VERSION 5.7 ;
BUSBITCHARS "[]" ;
DIVIDERCHAR "/" ;


UNITS
  DATABASE MICRONS 1000 ;
END UNITS


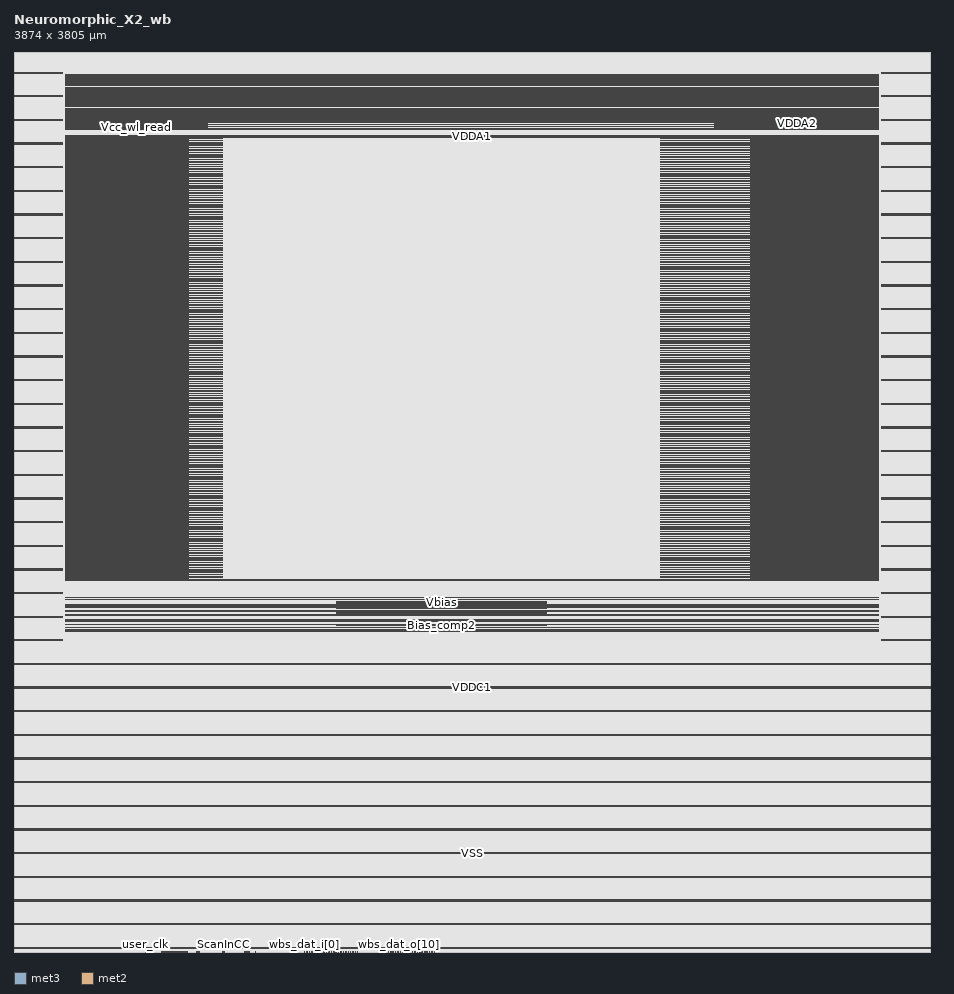
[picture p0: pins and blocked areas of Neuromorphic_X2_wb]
MACRO Neuromorphic_X2_wb
  CLASS BLOCK ;
  ORIGIN 0 0 ;
  FOREIGN Neuromorphic_X2_wb 0 0 ;
  SIZE 3874 BY 3805 ;
  PIN VSS
    DIRECTION INOUT ;
    USE GROUND ;
    PORT
      LAYER met3 ;
        RECT 216.895 3444.195 3656.935 3445.195 ;
    END
    PORT
      LAYER met3 ;
        RECT 216.8 3450.445 3656.84 3451.445 ;
    END
    PORT
      LAYER met3 ;
        RECT 216.99 1575.065 3656.935 1576.065 ;
    END
    PORT
      LAYER met3 ;
        RECT 216.99 1569.495 3656.935 1570.495 ;
    END
    PORT
      LAYER met3 ;
        RECT 0 415 3874 416.8 ;
    END
    PORT
      LAYER met3 ;
        RECT 0 815 3874 816.8 ;
    END
    PORT
      LAYER met3 ;
        RECT 0 915 3874 916.8 ;
    END
    PORT
      LAYER met3 ;
        RECT 0 1015 3874 1016.8 ;
    END
    PORT
      LAYER met3 ;
        RECT 0 1115 3874 1116.8 ;
    END
    PORT
      LAYER met3 ;
        RECT 0 515 3874 516.8 ;
    END
    PORT
      LAYER met3 ;
        RECT 0 615 3874 616.8 ;
    END
    PORT
      LAYER met3 ;
        RECT 0 715 3874 716.8 ;
    END
    PORT
      LAYER met3 ;
        RECT 0 15 3874 16.8 ;
    END
    PORT
      LAYER met3 ;
        RECT 0 115 3874 116.8 ;
    END
    PORT
      LAYER met3 ;
        RECT 0 215 3874 216.8 ;
    END
    PORT
      LAYER met3 ;
        RECT 0 315 3874 316.8 ;
    END
    PORT
      LAYER met3 ;
        RECT 0 3715 205 3716.8 ;
    END
    PORT
      LAYER met3 ;
        RECT 3669 3715 3874 3716.8 ;
    END
    PORT
      LAYER met3 ;
        RECT 0 3615 205 3616.8 ;
    END
    PORT
      LAYER met3 ;
        RECT 3669 3615 3874 3616.8 ;
    END
    PORT
      LAYER met3 ;
        RECT 0 3515 205 3516.8 ;
    END
    PORT
      LAYER met3 ;
        RECT 3669 3515 3874 3516.8 ;
    END
    PORT
      LAYER met3 ;
        RECT 0 3415 205 3416.8 ;
    END
    PORT
      LAYER met3 ;
        RECT 3669 3415 3874 3416.8 ;
    END
    PORT
      LAYER met3 ;
        RECT 0 3315 205 3316.8 ;
    END
    PORT
      LAYER met3 ;
        RECT 3669 3315 3874 3316.8 ;
    END
    PORT
      LAYER met3 ;
        RECT 0 3215 205 3216.8 ;
    END
    PORT
      LAYER met3 ;
        RECT 3669 3215 3874 3216.8 ;
    END
    PORT
      LAYER met3 ;
        RECT 0 3115 205 3116.8 ;
    END
    PORT
      LAYER met3 ;
        RECT 3669 3115 3874 3116.8 ;
    END
    PORT
      LAYER met3 ;
        RECT 0 3015 205 3016.8 ;
    END
    PORT
      LAYER met3 ;
        RECT 3669 3015 3874 3016.8 ;
    END
    PORT
      LAYER met3 ;
        RECT 0 2915 205 2916.8 ;
    END
    PORT
      LAYER met3 ;
        RECT 3669 2915 3874 2916.8 ;
    END
    PORT
      LAYER met3 ;
        RECT 0 2815 205 2816.8 ;
    END
    PORT
      LAYER met3 ;
        RECT 3669 2815 3874 2816.8 ;
    END
    PORT
      LAYER met3 ;
        RECT 0 2715 205 2716.8 ;
    END
    PORT
      LAYER met3 ;
        RECT 3669 2715 3874 2716.8 ;
    END
    PORT
      LAYER met3 ;
        RECT 0 2615 205 2616.8 ;
    END
    PORT
      LAYER met3 ;
        RECT 3669 2615 3874 2616.8 ;
    END
    PORT
      LAYER met3 ;
        RECT 0 2515 205 2516.8 ;
    END
    PORT
      LAYER met3 ;
        RECT 3669 2515 3874 2516.8 ;
    END
    PORT
      LAYER met3 ;
        RECT 0 2415 205 2416.8 ;
    END
    PORT
      LAYER met3 ;
        RECT 3669 2415 3874 2416.8 ;
    END
    PORT
      LAYER met3 ;
        RECT 0 2315 205 2316.8 ;
    END
    PORT
      LAYER met3 ;
        RECT 3669 2315 3874 2316.8 ;
    END
    PORT
      LAYER met3 ;
        RECT 0 2215 205 2216.8 ;
    END
    PORT
      LAYER met3 ;
        RECT 3669 2215 3874 2216.8 ;
    END
    PORT
      LAYER met3 ;
        RECT 0 2115 205 2116.8 ;
    END
    PORT
      LAYER met3 ;
        RECT 3669 2115 3874 2116.8 ;
    END
    PORT
      LAYER met3 ;
        RECT 0 2015 205 2016.8 ;
    END
    PORT
      LAYER met3 ;
        RECT 3669 2015 3874 2016.8 ;
    END
    PORT
      LAYER met3 ;
        RECT 0 1715 205 1716.8 ;
    END
    PORT
      LAYER met3 ;
        RECT 0 1815 205 1816.8 ;
    END
    PORT
      LAYER met3 ;
        RECT 0 1915 205 1916.8 ;
    END
    PORT
      LAYER met3 ;
        RECT 0 1315 205 1316.8 ;
    END
    PORT
      LAYER met3 ;
        RECT 0 1415 205 1416.8 ;
    END
    PORT
      LAYER met3 ;
        RECT 0 1515 205 1516.8 ;
    END
    PORT
      LAYER met3 ;
        RECT 0 1615 205 1616.8 ;
    END
    PORT
      LAYER met3 ;
        RECT 3669 1415 3874 1416.8 ;
    END
    PORT
      LAYER met3 ;
        RECT 3669 1515 3874 1516.8 ;
    END
    PORT
      LAYER met3 ;
        RECT 3669 1615 3874 1616.8 ;
    END
    PORT
      LAYER met3 ;
        RECT 3669 1715 3874 1716.8 ;
    END
    PORT
      LAYER met3 ;
        RECT 3669 1815 3874 1816.8 ;
    END
    PORT
      LAYER met3 ;
        RECT 3669 1915 3874 1916.8 ;
    END
    PORT
      LAYER met3 ;
        RECT 3669 1315 3874 1316.8 ;
    END
    PORT
      LAYER met3 ;
        RECT 0 1215 3874 1216.8 ;
    END
    PORT
      LAYER met3 ;
        RECT 216.99 1465.725 3656.935 1467.225 ;
    END
    PORT
      LAYER met3 ;
        RECT 216.99 1457.28 3656.935 1458.78 ;
    END
    PORT
      LAYER met3 ;
        RECT 216.99 1421.265 3656.935 1422.765 ;
    END
    PORT
      LAYER met3 ;
        RECT 216.99 1357.08 3656.935 1358.58 ;
    END
    PORT
      LAYER met3 ;
        RECT 216.99 1371.215 3656.935 1372.715 ;
    END
    PORT
      LAYER met3 ;
        RECT 216.99 1490.735 3656.935 1492.235 ;
    END
    PORT
      LAYER met3 ;
        RECT 216.99 1497.995 3656.935 1499.495 ;
    END
    PORT
      LAYER met3 ;
        RECT 216.99 1441.55 3656.935 1443.05 ;
    END
    PORT
      LAYER met3 ;
        RECT 216.895 3566.285 3656.84 3567.285 ;
    END
    PORT
      LAYER met3 ;
        RECT 216.895 3586.705 3656.84 3587.705 ;
    END
    PORT
      LAYER met3 ;
        RECT 216.895 3588.705 3656.84 3589.705 ;
    END
    PORT
      LAYER met3 ;
        RECT 216.895 3592.705 3656.84 3593.705 ;
    END
    PORT
      LAYER met3 ;
        RECT 216.895 3594.705 3656.84 3595.705 ;
    END
    PORT
      LAYER met3 ;
        RECT 216.895 3596.705 3656.84 3597.705 ;
    END
    PORT
      LAYER met3 ;
        RECT 216.895 3615.96 3656.84 3616.96 ;
    END
    PORT
      LAYER met3 ;
        RECT 216.895 3617.96 3656.84 3618.96 ;
    END
    PORT
      LAYER met3 ;
        RECT 216.895 3621.96 3656.84 3622.96 ;
    END
    PORT
      LAYER met3 ;
        RECT 216.895 3623.96 3656.84 3624.96 ;
    END
    PORT
      LAYER met3 ;
        RECT 216.895 3625.96 3656.84 3626.96 ;
    END
    PORT
      LAYER met3 ;
        RECT 216.895 3645.495 3656.84 3646.495 ;
    END
    PORT
      LAYER met3 ;
        RECT 216.895 3647.495 3656.84 3648.495 ;
    END
    PORT
      LAYER met3 ;
        RECT 216.895 3649.495 3656.84 3650.495 ;
    END
    PORT
      LAYER met3 ;
        RECT 216.895 3651.495 3656.84 3652.495 ;
    END
    PORT
      LAYER met3 ;
        RECT 216.895 3653.495 3656.84 3654.495 ;
    END
    PORT
      LAYER met3 ;
        RECT 216.895 3663.04 3656.84 3664.04 ;
    END
    PORT
      LAYER met3 ;
        RECT 216.895 3682.355 3656.84 3683.355 ;
    END
    PORT
      LAYER met3 ;
        RECT 216.895 3684.355 3656.84 3685.355 ;
    END
    PORT
      LAYER met3 ;
        RECT 216.895 3686.355 3656.84 3687.355 ;
    END
    PORT
      LAYER met3 ;
        RECT 216.895 3688.355 3656.84 3689.355 ;
    END
    PORT
      LAYER met3 ;
        RECT 216.895 3692.72 3656.84 3693.72 ;
    END
    PORT
      LAYER met3 ;
        RECT 216.895 3696.72 3656.84 3697.72 ;
    END
    PORT
      LAYER met3 ;
        RECT 216.895 3707.535 3656.84 3708.535 ;
    END
    PORT
      LAYER met3 ;
        RECT 216.895 3532.02 3656.84 3533.02 ;
    END
    PORT
      LAYER met3 ;
        RECT 216.895 3534.02 3656.84 3535.02 ;
    END
    PORT
      LAYER met3 ;
        RECT 216.895 3526.02 3656.84 3527.02 ;
    END
    PORT
      LAYER met3 ;
        RECT 216.895 3528.02 3656.84 3529.02 ;
    END
    PORT
      LAYER met3 ;
        RECT 216.895 3556.285 3656.84 3557.285 ;
    END
    PORT
      LAYER met3 ;
        RECT 216.895 3558.285 3656.84 3559.285 ;
    END
    PORT
      LAYER met3 ;
        RECT 216.895 3560.285 3656.84 3561.285 ;
    END
    PORT
      LAYER met3 ;
        RECT 216.895 3564.285 3656.84 3565.285 ;
    END
    PORT
      LAYER met3 ;
        RECT 216.895 3478.52 3656.84 3479.52 ;
    END
    PORT
      LAYER met3 ;
        RECT 216.895 3580.705 3656.84 3581.705 ;
    END
    PORT
      LAYER met3 ;
        RECT 216.895 3582.705 3656.84 3583.705 ;
    END
    PORT
      LAYER met3 ;
        RECT 216.895 3584.705 3656.84 3585.705 ;
    END
    PORT
      LAYER met3 ;
        RECT 216.895 3572.705 3656.84 3573.705 ;
    END
    PORT
      LAYER met3 ;
        RECT 216.895 3544.285 3656.84 3545.285 ;
    END
    PORT
      LAYER met3 ;
        RECT 216.895 3546.285 3656.84 3547.285 ;
    END
    PORT
      LAYER met3 ;
        RECT 216.895 3548.285 3656.84 3549.285 ;
    END
    PORT
      LAYER met3 ;
        RECT 216.895 3552.285 3656.84 3553.285 ;
    END
    PORT
      LAYER met3 ;
        RECT 216.895 3554.285 3656.84 3555.285 ;
    END
    PORT
      LAYER met3 ;
        RECT 216.895 3542.285 3656.84 3543.285 ;
    END
    PORT
      LAYER met3 ;
        RECT 216.895 3514.02 3656.84 3515.02 ;
    END
    PORT
      LAYER met3 ;
        RECT 216.895 3516.02 3656.84 3517.02 ;
    END
    PORT
      LAYER met3 ;
        RECT 216.895 3520.02 3656.84 3521.02 ;
    END
    PORT
      LAYER met3 ;
        RECT 216.895 3522.02 3656.84 3523.02 ;
    END
    PORT
      LAYER met3 ;
        RECT 216.895 3512.02 3656.84 3513.02 ;
    END
    PORT
      LAYER met3 ;
        RECT 216.895 3633.495 3656.84 3634.495 ;
    END
    PORT
      LAYER met3 ;
        RECT 216.895 3635.495 3656.84 3636.495 ;
    END
    PORT
      LAYER met3 ;
        RECT 216.895 3637.495 3656.84 3638.495 ;
    END
    PORT
      LAYER met3 ;
        RECT 216.895 3639.495 3656.84 3640.495 ;
    END
    PORT
      LAYER met3 ;
        RECT 216.895 3641.495 3656.84 3642.495 ;
    END
    PORT
      LAYER met3 ;
        RECT 216.895 3631.495 3656.84 3632.495 ;
    END
    PORT
      LAYER met3 ;
        RECT 216.895 3603.96 3656.84 3604.96 ;
    END
    PORT
      LAYER met3 ;
        RECT 216.895 3605.96 3656.84 3606.96 ;
    END
    PORT
      LAYER met3 ;
        RECT 216.895 3609.96 3656.84 3610.96 ;
    END
    PORT
      LAYER met3 ;
        RECT 216.895 3611.96 3656.84 3612.96 ;
    END
    PORT
      LAYER met3 ;
        RECT 216.895 3613.96 3656.84 3614.96 ;
    END
    PORT
      LAYER met3 ;
        RECT 216.895 3601.96 3656.84 3602.96 ;
    END
    PORT
      LAYER met3 ;
        RECT 216.895 3574.705 3656.84 3575.705 ;
    END
    PORT
      LAYER met3 ;
        RECT 216.895 3576.705 3656.84 3577.705 ;
    END
    PORT
      LAYER met3 ;
        RECT 2731.99 1806.965 3656.935 1807.305 ;
        RECT 2731.99 1923.445 3656.935 1923.785 ;
        RECT 2731.99 2039.925 3656.935 2040.265 ;
        RECT 2731.99 2156.405 3656.935 2156.745 ;
        RECT 2731.99 2272.885 3656.935 2273.225 ;
        RECT 2731.99 2389.365 3656.935 2389.705 ;
        RECT 2731.99 2505.845 3656.935 2506.185 ;
        RECT 2731.99 2622.325 3656.935 2622.665 ;
        RECT 2731.99 2738.805 3656.935 2739.145 ;
        RECT 2731.99 2855.285 3656.935 2855.625 ;
        RECT 2731.99 2971.765 3656.935 2972.105 ;
        RECT 2731.99 3088.245 3656.935 3088.585 ;
        RECT 2731.99 3204.725 3656.935 3205.065 ;
        RECT 2731.99 3321.205 3656.935 3321.545 ;
        RECT 2731.99 3437.685 3656.935 3438.025 ;
    END
    PORT
      LAYER met3 ;
        RECT 2731.99 1799.685 3656.935 1800.025 ;
        RECT 2731.99 1916.165 3656.935 1916.505 ;
        RECT 2731.99 2032.645 3656.935 2032.985 ;
        RECT 2731.99 2149.125 3656.935 2149.465 ;
        RECT 2731.99 2265.605 3656.935 2265.945 ;
        RECT 2731.99 2382.085 3656.935 2382.425 ;
        RECT 2731.99 2498.565 3656.935 2498.905 ;
        RECT 2731.99 2615.045 3656.935 2615.385 ;
        RECT 2731.99 2731.525 3656.935 2731.865 ;
        RECT 2731.99 2848.005 3656.935 2848.345 ;
        RECT 2731.99 2964.485 3656.935 2964.825 ;
        RECT 2731.99 3080.965 3656.935 3081.305 ;
        RECT 2731.99 3197.445 3656.935 3197.785 ;
        RECT 2731.99 3313.925 3656.935 3314.265 ;
        RECT 2731.99 3430.405 3656.935 3430.745 ;
    END
    PORT
      LAYER met3 ;
        RECT 2731.99 1792.405 3656.935 1792.745 ;
        RECT 2731.99 1908.885 3656.935 1909.225 ;
        RECT 2731.99 2025.365 3656.935 2025.705 ;
        RECT 2731.99 2141.845 3656.935 2142.185 ;
        RECT 2731.99 2258.325 3656.935 2258.665 ;
        RECT 2731.99 2374.805 3656.935 2375.145 ;
        RECT 2731.99 2491.285 3656.935 2491.625 ;
        RECT 2731.99 2607.765 3656.935 2608.105 ;
        RECT 2731.99 2724.245 3656.935 2724.585 ;
        RECT 2731.99 2840.725 3656.935 2841.065 ;
        RECT 2731.99 2957.205 3656.935 2957.545 ;
        RECT 2731.99 3073.685 3656.935 3074.025 ;
        RECT 2731.99 3190.165 3656.935 3190.505 ;
        RECT 2731.99 3306.645 3656.935 3306.985 ;
        RECT 2731.99 3423.125 3656.935 3423.465 ;
    END
    PORT
      LAYER met3 ;
        RECT 2731.99 1785.125 3656.935 1785.465 ;
        RECT 2731.99 1901.605 3656.935 1901.945 ;
        RECT 2731.99 2018.085 3656.935 2018.425 ;
        RECT 2731.99 2134.565 3656.935 2134.905 ;
        RECT 2731.99 2251.045 3656.935 2251.385 ;
        RECT 2731.99 2367.525 3656.935 2367.865 ;
        RECT 2731.99 2484.005 3656.935 2484.345 ;
        RECT 2731.99 2600.485 3656.935 2600.825 ;
        RECT 2731.99 2716.965 3656.935 2717.305 ;
        RECT 2731.99 2833.445 3656.935 2833.785 ;
        RECT 2731.99 2949.925 3656.935 2950.265 ;
        RECT 2731.99 3066.405 3656.935 3066.745 ;
        RECT 2731.99 3182.885 3656.935 3183.225 ;
        RECT 2731.99 3299.365 3656.935 3299.705 ;
        RECT 2731.99 3415.845 3656.935 3416.185 ;
    END
    PORT
      LAYER met3 ;
        RECT 2731.99 1777.845 3656.935 1778.185 ;
        RECT 2731.99 1894.325 3656.935 1894.665 ;
        RECT 2731.99 2010.805 3656.935 2011.145 ;
        RECT 2731.99 2127.285 3656.935 2127.625 ;
        RECT 2731.99 2243.765 3656.935 2244.105 ;
        RECT 2731.99 2360.245 3656.935 2360.585 ;
        RECT 2731.99 2476.725 3656.935 2477.065 ;
        RECT 2731.99 2593.205 3656.935 2593.545 ;
        RECT 2731.99 2709.685 3656.935 2710.025 ;
        RECT 2731.99 2826.165 3656.935 2826.505 ;
        RECT 2731.99 2942.645 3656.935 2942.985 ;
        RECT 2731.99 3059.125 3656.935 3059.465 ;
        RECT 2731.99 3175.605 3656.935 3175.945 ;
        RECT 2731.99 3292.085 3656.935 3292.425 ;
        RECT 2731.99 3408.565 3656.935 3408.905 ;
    END
    PORT
      LAYER met3 ;
        RECT 2731.99 1770.565 3656.935 1770.905 ;
        RECT 2731.99 1887.045 3656.935 1887.385 ;
        RECT 2731.99 2003.525 3656.935 2003.865 ;
        RECT 2731.99 2120.005 3656.935 2120.345 ;
        RECT 2731.99 2236.485 3656.935 2236.825 ;
        RECT 2731.99 2352.965 3656.935 2353.305 ;
        RECT 2731.99 2469.445 3656.935 2469.785 ;
        RECT 2731.99 2585.925 3656.935 2586.265 ;
        RECT 2731.99 2702.405 3656.935 2702.745 ;
        RECT 2731.99 2818.885 3656.935 2819.225 ;
        RECT 2731.99 2935.365 3656.935 2935.705 ;
        RECT 2731.99 3051.845 3656.935 3052.185 ;
        RECT 2731.99 3168.325 3656.935 3168.665 ;
        RECT 2731.99 3284.805 3656.935 3285.145 ;
        RECT 2731.99 3401.285 3656.935 3401.625 ;
    END
    PORT
      LAYER met3 ;
        RECT 2731.99 1763.285 3656.935 1763.625 ;
        RECT 2731.99 1879.765 3656.935 1880.105 ;
        RECT 2731.99 1996.245 3656.935 1996.585 ;
        RECT 2731.99 2112.725 3656.935 2113.065 ;
        RECT 2731.99 2229.205 3656.935 2229.545 ;
        RECT 2731.99 2345.685 3656.935 2346.025 ;
        RECT 2731.99 2462.165 3656.935 2462.505 ;
        RECT 2731.99 2578.645 3656.935 2578.985 ;
        RECT 2731.99 2695.125 3656.935 2695.465 ;
        RECT 2731.99 2811.605 3656.935 2811.945 ;
        RECT 2731.99 2928.085 3656.935 2928.425 ;
        RECT 2731.99 3044.565 3656.935 3044.905 ;
        RECT 2731.99 3161.045 3656.935 3161.385 ;
        RECT 2731.99 3277.525 3656.935 3277.865 ;
        RECT 2731.99 3394.005 3656.935 3394.345 ;
    END
    PORT
      LAYER met3 ;
        RECT 2731.99 1756.005 3656.935 1756.345 ;
        RECT 2731.99 1872.485 3656.935 1872.825 ;
        RECT 2731.99 1988.965 3656.935 1989.305 ;
        RECT 2731.99 2105.445 3656.935 2105.785 ;
        RECT 2731.99 2221.925 3656.935 2222.265 ;
        RECT 2731.99 2338.405 3656.935 2338.745 ;
        RECT 2731.99 2454.885 3656.935 2455.225 ;
        RECT 2731.99 2571.365 3656.935 2571.705 ;
        RECT 2731.99 2687.845 3656.935 2688.185 ;
        RECT 2731.99 2804.325 3656.935 2804.665 ;
        RECT 2731.99 2920.805 3656.935 2921.145 ;
        RECT 2731.99 3037.285 3656.935 3037.625 ;
        RECT 2731.99 3153.765 3656.935 3154.105 ;
        RECT 2731.99 3270.245 3656.935 3270.585 ;
        RECT 2731.99 3386.725 3656.935 3387.065 ;
    END
    PORT
      LAYER met3 ;
        RECT 2731.99 1748.725 3656.935 1749.065 ;
        RECT 2731.99 1865.205 3656.935 1865.545 ;
        RECT 2731.99 1981.685 3656.935 1982.025 ;
        RECT 2731.99 2098.165 3656.935 2098.505 ;
        RECT 2731.99 2214.645 3656.935 2214.985 ;
        RECT 2731.99 2331.125 3656.935 2331.465 ;
        RECT 2731.99 2447.605 3656.935 2447.945 ;
        RECT 2731.99 2564.085 3656.935 2564.425 ;
        RECT 2731.99 2680.565 3656.935 2680.905 ;
        RECT 2731.99 2797.045 3656.935 2797.385 ;
        RECT 2731.99 2913.525 3656.935 2913.865 ;
        RECT 2731.99 3030.005 3656.935 3030.345 ;
        RECT 2731.99 3146.485 3656.935 3146.825 ;
        RECT 2731.99 3262.965 3656.935 3263.305 ;
        RECT 2731.99 3379.445 3656.935 3379.785 ;
    END
    PORT
      LAYER met3 ;
        RECT 2731.99 1741.445 3656.935 1741.785 ;
        RECT 2731.99 1857.925 3656.935 1858.265 ;
        RECT 2731.99 1974.405 3656.935 1974.745 ;
        RECT 2731.99 2090.885 3656.935 2091.225 ;
        RECT 2731.99 2207.365 3656.935 2207.705 ;
        RECT 2731.99 2323.845 3656.935 2324.185 ;
        RECT 2731.99 2440.325 3656.935 2440.665 ;
        RECT 2731.99 2556.805 3656.935 2557.145 ;
        RECT 2731.99 2673.285 3656.935 2673.625 ;
        RECT 2731.99 2789.765 3656.935 2790.105 ;
        RECT 2731.99 2906.245 3656.935 2906.585 ;
        RECT 2731.99 3022.725 3656.935 3023.065 ;
        RECT 2731.99 3139.205 3656.935 3139.545 ;
        RECT 2731.99 3255.685 3656.935 3256.025 ;
        RECT 2731.99 3372.165 3656.935 3372.505 ;
    END
    PORT
      LAYER met3 ;
        RECT 2731.99 1734.165 3656.935 1734.505 ;
        RECT 2731.99 1850.645 3656.935 1850.985 ;
        RECT 2731.99 1967.125 3656.935 1967.465 ;
        RECT 2731.99 2083.605 3656.935 2083.945 ;
        RECT 2731.99 2200.085 3656.935 2200.425 ;
        RECT 2731.99 2316.565 3656.935 2316.905 ;
        RECT 2731.99 2433.045 3656.935 2433.385 ;
        RECT 2731.99 2549.525 3656.935 2549.865 ;
        RECT 2731.99 2666.005 3656.935 2666.345 ;
        RECT 2731.99 2782.485 3656.935 2782.825 ;
        RECT 2731.99 2898.965 3656.935 2899.305 ;
        RECT 2731.99 3015.445 3656.935 3015.785 ;
        RECT 2731.99 3131.925 3656.935 3132.265 ;
        RECT 2731.99 3248.405 3656.935 3248.745 ;
        RECT 2731.99 3364.885 3656.935 3365.225 ;
    END
    PORT
      LAYER met3 ;
        RECT 2731.99 1726.885 3656.935 1727.225 ;
        RECT 2731.99 1843.365 3656.935 1843.705 ;
        RECT 2731.99 1959.845 3656.935 1960.185 ;
        RECT 2731.99 2076.325 3656.935 2076.665 ;
        RECT 2731.99 2192.805 3656.935 2193.145 ;
        RECT 2731.99 2309.285 3656.935 2309.625 ;
        RECT 2731.99 2425.765 3656.935 2426.105 ;
        RECT 2731.99 2542.245 3656.935 2542.585 ;
        RECT 2731.99 2658.725 3656.935 2659.065 ;
        RECT 2731.99 2775.205 3656.935 2775.545 ;
        RECT 2731.99 2891.685 3656.935 2892.025 ;
        RECT 2731.99 3008.165 3656.935 3008.505 ;
        RECT 2731.99 3124.645 3656.935 3124.985 ;
        RECT 2731.99 3241.125 3656.935 3241.465 ;
        RECT 2731.99 3357.605 3656.935 3357.945 ;
    END
    PORT
      LAYER met3 ;
        RECT 2731.99 1719.605 3656.935 1719.945 ;
        RECT 2731.99 1836.085 3656.935 1836.425 ;
        RECT 2731.99 1952.565 3656.935 1952.905 ;
        RECT 2731.99 2069.045 3656.935 2069.385 ;
        RECT 2731.99 2185.525 3656.935 2185.865 ;
        RECT 2731.99 2302.005 3656.935 2302.345 ;
        RECT 2731.99 2418.485 3656.935 2418.825 ;
        RECT 2731.99 2534.965 3656.935 2535.305 ;
        RECT 2731.99 2651.445 3656.935 2651.785 ;
        RECT 2731.99 2767.925 3656.935 2768.265 ;
        RECT 2731.99 2884.405 3656.935 2884.745 ;
        RECT 2731.99 3000.885 3656.935 3001.225 ;
        RECT 2731.99 3117.365 3656.935 3117.705 ;
        RECT 2731.99 3233.845 3656.935 3234.185 ;
        RECT 2731.99 3350.325 3656.935 3350.665 ;
    END
    PORT
      LAYER met3 ;
        RECT 2731.99 1712.325 3656.935 1712.665 ;
        RECT 2731.99 1828.805 3656.935 1829.145 ;
        RECT 2731.99 1945.285 3656.935 1945.625 ;
        RECT 2731.99 2061.765 3656.935 2062.105 ;
        RECT 2731.99 2178.245 3656.935 2178.585 ;
        RECT 2731.99 2294.725 3656.935 2295.065 ;
        RECT 2731.99 2411.205 3656.935 2411.545 ;
        RECT 2731.99 2527.685 3656.935 2528.025 ;
        RECT 2731.99 2644.165 3656.935 2644.505 ;
        RECT 2731.99 2760.645 3656.935 2760.985 ;
        RECT 2731.99 2877.125 3656.935 2877.465 ;
        RECT 2731.99 2993.605 3656.935 2993.945 ;
        RECT 2731.99 3110.085 3656.935 3110.425 ;
        RECT 2731.99 3226.565 3656.935 3226.905 ;
        RECT 2731.99 3343.045 3656.935 3343.385 ;
    END
    PORT
      LAYER met3 ;
        RECT 2731.99 1705.045 3656.935 1705.385 ;
        RECT 2731.99 1821.525 3656.935 1821.865 ;
        RECT 2731.99 1938.005 3656.935 1938.345 ;
        RECT 2731.99 2054.485 3656.935 2054.825 ;
        RECT 2731.99 2170.965 3656.935 2171.305 ;
        RECT 2731.99 2287.445 3656.935 2287.785 ;
        RECT 2731.99 2403.925 3656.935 2404.265 ;
        RECT 2731.99 2520.405 3656.935 2520.745 ;
        RECT 2731.99 2636.885 3656.935 2637.225 ;
        RECT 2731.99 2753.365 3656.935 2753.705 ;
        RECT 2731.99 2869.845 3656.935 2870.185 ;
        RECT 2731.99 2986.325 3656.935 2986.665 ;
        RECT 2731.99 3102.805 3656.935 3103.145 ;
        RECT 2731.99 3219.285 3656.935 3219.625 ;
        RECT 2731.99 3335.765 3656.935 3336.105 ;
    END
    PORT
      LAYER met3 ;
        RECT 2731.99 1697.765 3656.935 1698.105 ;
        RECT 2731.99 1814.245 3656.935 1814.585 ;
        RECT 2731.99 1930.725 3656.935 1931.065 ;
        RECT 2731.99 2047.205 3656.935 2047.545 ;
        RECT 2731.99 2163.685 3656.935 2164.025 ;
        RECT 2731.99 2280.165 3656.935 2280.505 ;
        RECT 2731.99 2396.645 3656.935 2396.985 ;
        RECT 2731.99 2513.125 3656.935 2513.465 ;
        RECT 2731.99 2629.605 3656.935 2629.945 ;
        RECT 2731.99 2746.085 3656.935 2746.425 ;
        RECT 2731.99 2862.565 3656.935 2862.905 ;
        RECT 2731.99 2979.045 3656.935 2979.385 ;
        RECT 2731.99 3095.525 3656.935 3095.865 ;
        RECT 2731.99 3212.005 3656.935 3212.345 ;
        RECT 2731.99 3328.485 3656.935 3328.825 ;
    END
    PORT
      LAYER met3 ;
        RECT 216.99 1807.11 881.99 1807.45 ;
        RECT 216.99 1923.59 881.99 1923.93 ;
        RECT 216.99 2040.07 881.99 2040.41 ;
        RECT 216.99 2156.55 881.99 2156.89 ;
        RECT 216.99 2273.03 881.99 2273.37 ;
        RECT 216.99 2389.51 881.99 2389.85 ;
        RECT 216.99 2505.99 881.99 2506.33 ;
        RECT 216.99 2622.47 881.99 2622.81 ;
        RECT 216.99 2738.95 881.99 2739.29 ;
        RECT 216.99 2855.43 881.99 2855.77 ;
        RECT 216.99 2971.91 881.99 2972.25 ;
        RECT 216.99 3088.39 881.99 3088.73 ;
        RECT 216.99 3204.87 881.99 3205.21 ;
        RECT 216.99 3321.35 881.99 3321.69 ;
        RECT 216.99 3437.83 881.99 3438.17 ;
    END
    PORT
      LAYER met3 ;
        RECT 216.99 1799.83 881.99 1800.17 ;
        RECT 216.99 1916.31 881.99 1916.65 ;
        RECT 216.99 2032.79 881.99 2033.13 ;
        RECT 216.99 2149.27 881.99 2149.61 ;
        RECT 216.99 2265.75 881.99 2266.09 ;
        RECT 216.99 2382.23 881.99 2382.57 ;
        RECT 216.99 2498.71 881.99 2499.05 ;
        RECT 216.99 2615.19 881.99 2615.53 ;
        RECT 216.99 2731.67 881.99 2732.01 ;
        RECT 216.99 2848.15 881.99 2848.49 ;
        RECT 216.99 2964.63 881.99 2964.97 ;
        RECT 216.99 3081.11 881.99 3081.45 ;
        RECT 216.99 3197.59 881.99 3197.93 ;
        RECT 216.99 3314.07 881.99 3314.41 ;
        RECT 216.99 3430.55 881.99 3430.89 ;
    END
    PORT
      LAYER met3 ;
        RECT 216.99 1792.55 881.99 1792.89 ;
        RECT 216.99 1909.03 881.99 1909.37 ;
        RECT 216.99 2025.51 881.99 2025.85 ;
        RECT 216.99 2141.99 881.99 2142.33 ;
        RECT 216.99 2258.47 881.99 2258.81 ;
        RECT 216.99 2374.95 881.99 2375.29 ;
        RECT 216.99 2491.43 881.99 2491.77 ;
        RECT 216.99 2607.91 881.99 2608.25 ;
        RECT 216.99 2724.39 881.99 2724.73 ;
        RECT 216.99 2840.87 881.99 2841.21 ;
        RECT 216.99 2957.35 881.99 2957.69 ;
        RECT 216.99 3073.83 881.99 3074.17 ;
        RECT 216.99 3190.31 881.99 3190.65 ;
        RECT 216.99 3306.79 881.99 3307.13 ;
        RECT 216.99 3423.27 881.99 3423.61 ;
    END
    PORT
      LAYER met3 ;
        RECT 216.99 1785.27 881.99 1785.61 ;
        RECT 216.99 1901.75 881.99 1902.09 ;
        RECT 216.99 2018.23 881.99 2018.57 ;
        RECT 216.99 2134.71 881.99 2135.05 ;
        RECT 216.99 2251.19 881.99 2251.53 ;
        RECT 216.99 2367.67 881.99 2368.01 ;
        RECT 216.99 2484.15 881.99 2484.49 ;
        RECT 216.99 2600.63 881.99 2600.97 ;
        RECT 216.99 2717.11 881.99 2717.45 ;
        RECT 216.99 2833.59 881.99 2833.93 ;
        RECT 216.99 2950.07 881.99 2950.41 ;
        RECT 216.99 3066.55 881.99 3066.89 ;
        RECT 216.99 3183.03 881.99 3183.37 ;
        RECT 216.99 3299.51 881.99 3299.85 ;
        RECT 216.99 3415.99 881.99 3416.33 ;
    END
    PORT
      LAYER met3 ;
        RECT 216.99 1777.99 881.99 1778.33 ;
        RECT 216.99 1894.47 881.99 1894.81 ;
        RECT 216.99 2010.95 881.99 2011.29 ;
        RECT 216.99 2127.43 881.99 2127.77 ;
        RECT 216.99 2243.91 881.99 2244.25 ;
        RECT 216.99 2360.39 881.99 2360.73 ;
        RECT 216.99 2476.87 881.99 2477.21 ;
        RECT 216.99 2593.35 881.99 2593.69 ;
        RECT 216.99 2709.83 881.99 2710.17 ;
        RECT 216.99 2826.31 881.99 2826.65 ;
        RECT 216.99 2942.79 881.99 2943.13 ;
        RECT 216.99 3059.27 881.99 3059.61 ;
        RECT 216.99 3175.75 881.99 3176.09 ;
        RECT 216.99 3292.23 881.99 3292.57 ;
        RECT 216.99 3408.71 881.99 3409.05 ;
    END
    PORT
      LAYER met3 ;
        RECT 216.99 1770.71 881.99 1771.05 ;
        RECT 216.99 1887.19 881.99 1887.53 ;
        RECT 216.99 2003.67 881.99 2004.01 ;
        RECT 216.99 2120.15 881.99 2120.49 ;
        RECT 216.99 2236.63 881.99 2236.97 ;
        RECT 216.99 2353.11 881.99 2353.45 ;
        RECT 216.99 2469.59 881.99 2469.93 ;
        RECT 216.99 2586.07 881.99 2586.41 ;
        RECT 216.99 2702.55 881.99 2702.89 ;
        RECT 216.99 2819.03 881.99 2819.37 ;
        RECT 216.99 2935.51 881.99 2935.85 ;
        RECT 216.99 3051.99 881.99 3052.33 ;
        RECT 216.99 3168.47 881.99 3168.81 ;
        RECT 216.99 3284.95 881.99 3285.29 ;
        RECT 216.99 3401.43 881.99 3401.77 ;
    END
    PORT
      LAYER met3 ;
        RECT 216.99 1763.43 881.99 1763.77 ;
        RECT 216.99 1879.91 881.99 1880.25 ;
        RECT 216.99 1996.39 881.99 1996.73 ;
        RECT 216.99 2112.87 881.99 2113.21 ;
        RECT 216.99 2229.35 881.99 2229.69 ;
        RECT 216.99 2345.83 881.99 2346.17 ;
        RECT 216.99 2462.31 881.99 2462.65 ;
        RECT 216.99 2578.79 881.99 2579.13 ;
        RECT 216.99 2695.27 881.99 2695.61 ;
        RECT 216.99 2811.75 881.99 2812.09 ;
        RECT 216.99 2928.23 881.99 2928.57 ;
        RECT 216.99 3044.71 881.99 3045.05 ;
        RECT 216.99 3161.19 881.99 3161.53 ;
        RECT 216.99 3277.67 881.99 3278.01 ;
        RECT 216.99 3394.15 881.99 3394.49 ;
    END
    PORT
      LAYER met3 ;
        RECT 216.99 1756.15 881.99 1756.49 ;
        RECT 216.99 1872.63 881.99 1872.97 ;
        RECT 216.99 1989.11 881.99 1989.45 ;
        RECT 216.99 2105.59 881.99 2105.93 ;
        RECT 216.99 2222.07 881.99 2222.41 ;
        RECT 216.99 2338.55 881.99 2338.89 ;
        RECT 216.99 2455.03 881.99 2455.37 ;
        RECT 216.99 2571.51 881.99 2571.85 ;
        RECT 216.99 2687.99 881.99 2688.33 ;
        RECT 216.99 2804.47 881.99 2804.81 ;
        RECT 216.99 2920.95 881.99 2921.29 ;
        RECT 216.99 3037.43 881.99 3037.77 ;
        RECT 216.99 3153.91 881.99 3154.25 ;
        RECT 216.99 3270.39 881.99 3270.73 ;
        RECT 216.99 3386.87 881.99 3387.21 ;
    END
    PORT
      LAYER met3 ;
        RECT 216.99 1748.87 881.99 1749.21 ;
        RECT 216.99 1865.35 881.99 1865.69 ;
        RECT 216.99 1981.83 881.99 1982.17 ;
        RECT 216.99 2098.31 881.99 2098.65 ;
        RECT 216.99 2214.79 881.99 2215.13 ;
        RECT 216.99 2331.27 881.99 2331.61 ;
        RECT 216.99 2447.75 881.99 2448.09 ;
        RECT 216.99 2564.23 881.99 2564.57 ;
        RECT 216.99 2680.71 881.99 2681.05 ;
        RECT 216.99 2797.19 881.99 2797.53 ;
        RECT 216.99 2913.67 881.99 2914.01 ;
        RECT 216.99 3030.15 881.99 3030.49 ;
        RECT 216.99 3146.63 881.99 3146.97 ;
        RECT 216.99 3263.11 881.99 3263.45 ;
        RECT 216.99 3379.59 881.99 3379.93 ;
    END
    PORT
      LAYER met3 ;
        RECT 216.99 1741.59 881.99 1741.93 ;
        RECT 216.99 1858.07 881.99 1858.41 ;
        RECT 216.99 1974.55 881.99 1974.89 ;
        RECT 216.99 2091.03 881.99 2091.37 ;
        RECT 216.99 2207.51 881.99 2207.85 ;
        RECT 216.99 2323.99 881.99 2324.33 ;
        RECT 216.99 2440.47 881.99 2440.81 ;
        RECT 216.99 2556.95 881.99 2557.29 ;
        RECT 216.99 2673.43 881.99 2673.77 ;
        RECT 216.99 2789.91 881.99 2790.25 ;
        RECT 216.99 2906.39 881.99 2906.73 ;
        RECT 216.99 3022.87 881.99 3023.21 ;
        RECT 216.99 3139.35 881.99 3139.69 ;
        RECT 216.99 3255.83 881.99 3256.17 ;
        RECT 216.99 3372.31 881.99 3372.65 ;
    END
    PORT
      LAYER met3 ;
        RECT 216.99 1734.31 881.99 1734.65 ;
        RECT 216.99 1850.79 881.99 1851.13 ;
        RECT 216.99 1967.27 881.99 1967.61 ;
        RECT 216.99 2083.75 881.99 2084.09 ;
        RECT 216.99 2200.23 881.99 2200.57 ;
        RECT 216.99 2316.71 881.99 2317.05 ;
        RECT 216.99 2433.19 881.99 2433.53 ;
        RECT 216.99 2549.67 881.99 2550.01 ;
        RECT 216.99 2666.15 881.99 2666.49 ;
        RECT 216.99 2782.63 881.99 2782.97 ;
        RECT 216.99 2899.11 881.99 2899.45 ;
        RECT 216.99 3015.59 881.99 3015.93 ;
        RECT 216.99 3132.07 881.99 3132.41 ;
        RECT 216.99 3248.55 881.99 3248.89 ;
        RECT 216.99 3365.03 881.99 3365.37 ;
    END
    PORT
      LAYER met3 ;
        RECT 216.99 1727.03 881.99 1727.37 ;
        RECT 216.99 1843.51 881.99 1843.85 ;
        RECT 216.99 1959.99 881.99 1960.33 ;
        RECT 216.99 2076.47 881.99 2076.81 ;
        RECT 216.99 2192.95 881.99 2193.29 ;
        RECT 216.99 2309.43 881.99 2309.77 ;
        RECT 216.99 2425.91 881.99 2426.25 ;
        RECT 216.99 2542.39 881.99 2542.73 ;
        RECT 216.99 2658.87 881.99 2659.21 ;
        RECT 216.99 2775.35 881.99 2775.69 ;
        RECT 216.99 2891.83 881.99 2892.17 ;
        RECT 216.99 3008.31 881.99 3008.65 ;
        RECT 216.99 3124.79 881.99 3125.13 ;
        RECT 216.99 3241.27 881.99 3241.61 ;
        RECT 216.99 3357.75 881.99 3358.09 ;
    END
    PORT
      LAYER met3 ;
        RECT 216.99 1719.75 881.99 1720.09 ;
        RECT 216.99 1836.23 881.99 1836.57 ;
        RECT 216.99 1952.71 881.99 1953.05 ;
        RECT 216.99 2069.19 881.99 2069.53 ;
        RECT 216.99 2185.67 881.99 2186.01 ;
        RECT 216.99 2302.15 881.99 2302.49 ;
        RECT 216.99 2418.63 881.99 2418.97 ;
        RECT 216.99 2535.11 881.99 2535.45 ;
        RECT 216.99 2651.59 881.99 2651.93 ;
        RECT 216.99 2768.07 881.99 2768.41 ;
        RECT 216.99 2884.55 881.99 2884.89 ;
        RECT 216.99 3001.03 881.99 3001.37 ;
        RECT 216.99 3117.51 881.99 3117.85 ;
        RECT 216.99 3233.99 881.99 3234.33 ;
        RECT 216.99 3350.47 881.99 3350.81 ;
    END
    PORT
      LAYER met3 ;
        RECT 216.99 1712.47 881.99 1712.81 ;
        RECT 216.99 1828.95 881.99 1829.29 ;
        RECT 216.99 1945.43 881.99 1945.77 ;
        RECT 216.99 2061.91 881.99 2062.25 ;
        RECT 216.99 2178.39 881.99 2178.73 ;
        RECT 216.99 2294.87 881.99 2295.21 ;
        RECT 216.99 2411.35 881.99 2411.69 ;
        RECT 216.99 2527.83 881.99 2528.17 ;
        RECT 216.99 2644.31 881.99 2644.65 ;
        RECT 216.99 2760.79 881.99 2761.13 ;
        RECT 216.99 2877.27 881.99 2877.61 ;
        RECT 216.99 2993.75 881.99 2994.09 ;
        RECT 216.99 3110.23 881.99 3110.57 ;
        RECT 216.99 3226.71 881.99 3227.05 ;
        RECT 216.99 3343.19 881.99 3343.53 ;
    END
    PORT
      LAYER met3 ;
        RECT 216.99 1705.19 881.99 1705.53 ;
        RECT 216.99 1821.67 881.99 1822.01 ;
        RECT 216.99 1938.15 881.99 1938.49 ;
        RECT 216.99 2054.63 881.99 2054.97 ;
        RECT 216.99 2171.11 881.99 2171.45 ;
        RECT 216.99 2287.59 881.99 2287.93 ;
        RECT 216.99 2404.07 881.99 2404.41 ;
        RECT 216.99 2520.55 881.99 2520.89 ;
        RECT 216.99 2637.03 881.99 2637.37 ;
        RECT 216.99 2753.51 881.99 2753.85 ;
        RECT 216.99 2869.99 881.99 2870.33 ;
        RECT 216.99 2986.47 881.99 2986.81 ;
        RECT 216.99 3102.95 881.99 3103.29 ;
        RECT 216.99 3219.43 881.99 3219.77 ;
        RECT 216.99 3335.91 881.99 3336.25 ;
    END
    PORT
      LAYER met3 ;
        RECT 216.99 1697.91 881.99 1698.25 ;
        RECT 216.99 1814.39 881.99 1814.73 ;
        RECT 216.99 1930.87 881.99 1931.21 ;
        RECT 216.99 2047.35 881.99 2047.69 ;
        RECT 216.99 2163.83 881.99 2164.17 ;
        RECT 216.99 2280.31 881.99 2280.65 ;
        RECT 216.99 2396.79 881.99 2397.13 ;
        RECT 216.99 2513.27 881.99 2513.61 ;
        RECT 216.99 2629.75 881.99 2630.09 ;
        RECT 216.99 2746.23 881.99 2746.57 ;
        RECT 216.99 2862.71 881.99 2863.05 ;
        RECT 216.99 2979.19 881.99 2979.53 ;
        RECT 216.99 3095.67 881.99 3096.01 ;
        RECT 216.99 3212.15 881.99 3212.49 ;
        RECT 216.99 3328.63 881.99 3328.97 ;
    END
    PORT
      LAYER met3 ;
        RECT 216.99 1690.63 881.99 1690.97 ;
    END
    PORT
      LAYER met3 ;
        RECT 216.99 1654.23 881.99 1654.57 ;
    END
    PORT
      LAYER met3 ;
        RECT 216.99 1676.07 881.99 1676.41 ;
    END
    PORT
      LAYER met3 ;
        RECT 216.99 1668.79 881.99 1669.13 ;
    END
    PORT
      LAYER met3 ;
        RECT 216.99 1683.35 881.99 1683.69 ;
    END
    PORT
      LAYER met3 ;
        RECT 216.99 1617.83 881.99 1618.17 ;
    END
    PORT
      LAYER met3 ;
        RECT 216.99 1610.55 881.99 1610.89 ;
    END
    PORT
      LAYER met3 ;
        RECT 216.99 1632.39 881.99 1632.73 ;
    END
    PORT
      LAYER met3 ;
        RECT 216.99 1625.11 881.99 1625.45 ;
    END
    PORT
      LAYER met3 ;
        RECT 216.99 1646.95 881.99 1647.29 ;
    END
    PORT
      LAYER met3 ;
        RECT 216.99 1639.67 881.99 1640.01 ;
    END
    PORT
      LAYER met3 ;
        RECT 216.99 1661.51 881.99 1661.85 ;
    END
    PORT
      LAYER met3 ;
        RECT 216.99 1588.71 881.99 1589.05 ;
    END
    PORT
      LAYER met3 ;
        RECT 216.99 1581.43 881.99 1581.77 ;
    END
    PORT
      LAYER met3 ;
        RECT 216.99 1603.27 881.99 1603.61 ;
    END
    PORT
      LAYER met3 ;
        RECT 216.99 1595.99 881.99 1596.33 ;
    END
    PORT
      LAYER met3 ;
        RECT 2731.99 1654.085 3656.935 1654.425 ;
    END
    PORT
      LAYER met3 ;
        RECT 2731.99 1661.365 3656.935 1661.705 ;
    END
    PORT
      LAYER met3 ;
        RECT 2731.99 1668.645 3656.935 1668.985 ;
    END
    PORT
      LAYER met3 ;
        RECT 2731.99 1675.925 3656.935 1676.265 ;
    END
    PORT
      LAYER met3 ;
        RECT 2731.99 1683.205 3656.935 1683.545 ;
    END
    PORT
      LAYER met3 ;
        RECT 2731.99 1690.485 3656.935 1690.825 ;
    END
    PORT
      LAYER met3 ;
        RECT 2731.99 1588.565 3656.935 1588.905 ;
    END
    PORT
      LAYER met3 ;
        RECT 2731.99 1595.845 3656.935 1596.185 ;
    END
    PORT
      LAYER met3 ;
        RECT 2731.99 1603.125 3656.935 1603.465 ;
    END
    PORT
      LAYER met3 ;
        RECT 2731.99 1610.405 3656.935 1610.745 ;
    END
    PORT
      LAYER met3 ;
        RECT 2731.99 1617.685 3656.935 1618.025 ;
    END
    PORT
      LAYER met3 ;
        RECT 2731.99 1624.965 3656.935 1625.305 ;
    END
    PORT
      LAYER met3 ;
        RECT 2731.99 1632.245 3656.935 1632.585 ;
    END
    PORT
      LAYER met3 ;
        RECT 2731.99 1639.525 3656.935 1639.865 ;
    END
    PORT
      LAYER met3 ;
        RECT 2731.99 1646.805 3656.935 1647.145 ;
    END
    PORT
      LAYER met3 ;
        RECT 2731.99 1581.285 3656.935 1581.625 ;
    END
  END VSS
  PIN VDDA1
    DIRECTION INOUT ;
    USE POWER ;
    PORT
      LAYER met3 ;
        RECT 216.8 3448.905 3656.84 3449.905 ;
    END
    PORT
      LAYER met3 ;
        RECT 216.99 1573.61 3656.935 1574.61 ;
    END
    PORT
      LAYER met3 ;
        RECT 216.895 3655.495 3656.84 3656.495 ;
    END
    PORT
      LAYER met3 ;
        RECT 216.895 3677.12 3656.84 3678.12 ;
    END
    PORT
      LAYER met3 ;
        RECT 216.895 3480.38 3656.84 3481.38 ;
    END
    PORT
      LAYER met3 ;
        RECT 216.895 3673.12 3656.84 3674.12 ;
    END
    PORT
      LAYER met3 ;
        RECT 216.895 3675.12 3656.84 3676.12 ;
    END
    PORT
      LAYER met3 ;
        RECT 216.895 3506.24 3656.84 3507.24 ;
    END
    PORT
      LAYER met3 ;
        RECT 216.895 3530.02 3656.84 3531.02 ;
    END
    PORT
      LAYER met3 ;
        RECT 216.895 3536.02 3656.84 3537.02 ;
    END
    PORT
      LAYER met3 ;
        RECT 216.895 3562.285 3656.84 3563.285 ;
    END
    PORT
      LAYER met3 ;
        RECT 216.895 3590.705 3656.84 3591.705 ;
    END
    PORT
      LAYER met3 ;
        RECT 216.895 3619.96 3656.84 3620.96 ;
    END
    PORT
      LAYER met3 ;
        RECT 216.895 3667.12 3656.84 3668.12 ;
    END
    PORT
      LAYER met3 ;
        RECT 216.895 3669.12 3656.84 3670.12 ;
    END
    PORT
      LAYER met3 ;
        RECT 216.895 3671.12 3656.84 3672.12 ;
    END
    PORT
      LAYER met3 ;
        RECT 216.895 3578.705 3656.84 3579.705 ;
    END
    PORT
      LAYER met3 ;
        RECT 216.895 3550.285 3656.84 3551.285 ;
    END
    PORT
      LAYER met3 ;
        RECT 216.895 3518.02 3656.84 3519.02 ;
    END
    PORT
      LAYER met3 ;
        RECT 216.895 3524.02 3656.84 3525.02 ;
    END
    PORT
      LAYER met3 ;
        RECT 216.895 3498.24 3656.84 3499.24 ;
    END
    PORT
      LAYER met3 ;
        RECT 216.895 3490.24 3656.84 3491.24 ;
    END
    PORT
      LAYER met3 ;
        RECT 216.895 3482.24 3656.84 3483.24 ;
    END
    PORT
      LAYER met3 ;
        RECT 216.895 3643.495 3656.84 3644.495 ;
    END
    PORT
      LAYER met3 ;
        RECT 216.895 3607.96 3656.84 3608.96 ;
    END
    PORT
      LAYER met3 ;
        RECT 3114.49 1810.605 3656.935 1810.945 ;
        RECT 3114.49 1927.085 3656.935 1927.425 ;
        RECT 3114.49 2043.565 3656.935 2043.905 ;
        RECT 3114.49 2160.045 3656.935 2160.385 ;
        RECT 3114.49 2276.525 3656.935 2276.865 ;
        RECT 3114.49 2393.005 3656.935 2393.345 ;
        RECT 3114.49 2509.485 3656.935 2509.825 ;
        RECT 3114.49 2625.965 3656.935 2626.305 ;
        RECT 3114.49 2742.445 3656.935 2742.785 ;
        RECT 3114.49 2858.925 3656.935 2859.265 ;
        RECT 3114.49 2975.405 3656.935 2975.745 ;
        RECT 3114.49 3091.885 3656.935 3092.225 ;
        RECT 3114.49 3208.365 3656.935 3208.705 ;
        RECT 3114.49 3324.845 3656.935 3325.185 ;
        RECT 3114.49 3441.325 3656.935 3441.665 ;
    END
    PORT
      LAYER met3 ;
        RECT 3114.49 1803.325 3656.935 1803.665 ;
        RECT 3114.49 1919.805 3656.935 1920.145 ;
        RECT 3114.49 2036.285 3656.935 2036.625 ;
        RECT 3114.49 2152.765 3656.935 2153.105 ;
        RECT 3114.49 2269.245 3656.935 2269.585 ;
        RECT 3114.49 2385.725 3656.935 2386.065 ;
        RECT 3114.49 2502.205 3656.935 2502.545 ;
        RECT 3114.49 2618.685 3656.935 2619.025 ;
        RECT 3114.49 2735.165 3656.935 2735.505 ;
        RECT 3114.49 2851.645 3656.935 2851.985 ;
        RECT 3114.49 2968.125 3656.935 2968.465 ;
        RECT 3114.49 3084.605 3656.935 3084.945 ;
        RECT 3114.49 3201.085 3656.935 3201.425 ;
        RECT 3114.49 3317.565 3656.935 3317.905 ;
        RECT 3114.49 3434.045 3656.935 3434.385 ;
    END
    PORT
      LAYER met3 ;
        RECT 3114.49 1796.045 3656.935 1796.385 ;
        RECT 3114.49 1912.525 3656.935 1912.865 ;
        RECT 3114.49 2029.005 3656.935 2029.345 ;
        RECT 3114.49 2145.485 3656.935 2145.825 ;
        RECT 3114.49 2261.965 3656.935 2262.305 ;
        RECT 3114.49 2378.445 3656.935 2378.785 ;
        RECT 3114.49 2494.925 3656.935 2495.265 ;
        RECT 3114.49 2611.405 3656.935 2611.745 ;
        RECT 3114.49 2727.885 3656.935 2728.225 ;
        RECT 3114.49 2844.365 3656.935 2844.705 ;
        RECT 3114.49 2960.845 3656.935 2961.185 ;
        RECT 3114.49 3077.325 3656.935 3077.665 ;
        RECT 3114.49 3193.805 3656.935 3194.145 ;
        RECT 3114.49 3310.285 3656.935 3310.625 ;
        RECT 3114.49 3426.765 3656.935 3427.105 ;
    END
    PORT
      LAYER met3 ;
        RECT 3114.49 1788.765 3656.935 1789.105 ;
        RECT 3114.49 1905.245 3656.935 1905.585 ;
        RECT 3114.49 2021.725 3656.935 2022.065 ;
        RECT 3114.49 2138.205 3656.935 2138.545 ;
        RECT 3114.49 2254.685 3656.935 2255.025 ;
        RECT 3114.49 2371.165 3656.935 2371.505 ;
        RECT 3114.49 2487.645 3656.935 2487.985 ;
        RECT 3114.49 2604.125 3656.935 2604.465 ;
        RECT 3114.49 2720.605 3656.935 2720.945 ;
        RECT 3114.49 2837.085 3656.935 2837.425 ;
        RECT 3114.49 2953.565 3656.935 2953.905 ;
        RECT 3114.49 3070.045 3656.935 3070.385 ;
        RECT 3114.49 3186.525 3656.935 3186.865 ;
        RECT 3114.49 3303.005 3656.935 3303.345 ;
        RECT 3114.49 3419.485 3656.935 3419.825 ;
    END
    PORT
      LAYER met3 ;
        RECT 3114.49 1781.485 3656.935 1781.825 ;
        RECT 3114.49 1897.965 3656.935 1898.305 ;
        RECT 3114.49 2014.445 3656.935 2014.785 ;
        RECT 3114.49 2130.925 3656.935 2131.265 ;
        RECT 3114.49 2247.405 3656.935 2247.745 ;
        RECT 3114.49 2363.885 3656.935 2364.225 ;
        RECT 3114.49 2480.365 3656.935 2480.705 ;
        RECT 3114.49 2596.845 3656.935 2597.185 ;
        RECT 3114.49 2713.325 3656.935 2713.665 ;
        RECT 3114.49 2829.805 3656.935 2830.145 ;
        RECT 3114.49 2946.285 3656.935 2946.625 ;
        RECT 3114.49 3062.765 3656.935 3063.105 ;
        RECT 3114.49 3179.245 3656.935 3179.585 ;
        RECT 3114.49 3295.725 3656.935 3296.065 ;
        RECT 3114.49 3412.205 3656.935 3412.545 ;
    END
    PORT
      LAYER met3 ;
        RECT 3114.49 1774.205 3656.935 1774.545 ;
        RECT 3114.49 1890.685 3656.935 1891.025 ;
        RECT 3114.49 2007.165 3656.935 2007.505 ;
        RECT 3114.49 2123.645 3656.935 2123.985 ;
        RECT 3114.49 2240.125 3656.935 2240.465 ;
        RECT 3114.49 2356.605 3656.935 2356.945 ;
        RECT 3114.49 2473.085 3656.935 2473.425 ;
        RECT 3114.49 2589.565 3656.935 2589.905 ;
        RECT 3114.49 2706.045 3656.935 2706.385 ;
        RECT 3114.49 2822.525 3656.935 2822.865 ;
        RECT 3114.49 2939.005 3656.935 2939.345 ;
        RECT 3114.49 3055.485 3656.935 3055.825 ;
        RECT 3114.49 3171.965 3656.935 3172.305 ;
        RECT 3114.49 3288.445 3656.935 3288.785 ;
        RECT 3114.49 3404.925 3656.935 3405.265 ;
    END
    PORT
      LAYER met3 ;
        RECT 3114.49 1766.925 3656.935 1767.265 ;
        RECT 3114.49 1883.405 3656.935 1883.745 ;
        RECT 3114.49 1999.885 3656.935 2000.225 ;
        RECT 3114.49 2116.365 3656.935 2116.705 ;
        RECT 3114.49 2232.845 3656.935 2233.185 ;
        RECT 3114.49 2349.325 3656.935 2349.665 ;
        RECT 3114.49 2465.805 3656.935 2466.145 ;
        RECT 3114.49 2582.285 3656.935 2582.625 ;
        RECT 3114.49 2698.765 3656.935 2699.105 ;
        RECT 3114.49 2815.245 3656.935 2815.585 ;
        RECT 3114.49 2931.725 3656.935 2932.065 ;
        RECT 3114.49 3048.205 3656.935 3048.545 ;
        RECT 3114.49 3164.685 3656.935 3165.025 ;
        RECT 3114.49 3281.165 3656.935 3281.505 ;
        RECT 3114.49 3397.645 3656.935 3397.985 ;
    END
    PORT
      LAYER met3 ;
        RECT 3114.49 1759.645 3656.935 1759.985 ;
        RECT 3114.49 1876.125 3656.935 1876.465 ;
        RECT 3114.49 1992.605 3656.935 1992.945 ;
        RECT 3114.49 2109.085 3656.935 2109.425 ;
        RECT 3114.49 2225.565 3656.935 2225.905 ;
        RECT 3114.49 2342.045 3656.935 2342.385 ;
        RECT 3114.49 2458.525 3656.935 2458.865 ;
        RECT 3114.49 2575.005 3656.935 2575.345 ;
        RECT 3114.49 2691.485 3656.935 2691.825 ;
        RECT 3114.49 2807.965 3656.935 2808.305 ;
        RECT 3114.49 2924.445 3656.935 2924.785 ;
        RECT 3114.49 3040.925 3656.935 3041.265 ;
        RECT 3114.49 3157.405 3656.935 3157.745 ;
        RECT 3114.49 3273.885 3656.935 3274.225 ;
        RECT 3114.49 3390.365 3656.935 3390.705 ;
    END
    PORT
      LAYER met3 ;
        RECT 3114.49 1752.365 3656.935 1752.705 ;
        RECT 3114.49 1868.845 3656.935 1869.185 ;
        RECT 3114.49 1985.325 3656.935 1985.665 ;
        RECT 3114.49 2101.805 3656.935 2102.145 ;
        RECT 3114.49 2218.285 3656.935 2218.625 ;
        RECT 3114.49 2334.765 3656.935 2335.105 ;
        RECT 3114.49 2451.245 3656.935 2451.585 ;
        RECT 3114.49 2567.725 3656.935 2568.065 ;
        RECT 3114.49 2684.205 3656.935 2684.545 ;
        RECT 3114.49 2800.685 3656.935 2801.025 ;
        RECT 3114.49 2917.165 3656.935 2917.505 ;
        RECT 3114.49 3033.645 3656.935 3033.985 ;
        RECT 3114.49 3150.125 3656.935 3150.465 ;
        RECT 3114.49 3266.605 3656.935 3266.945 ;
        RECT 3114.49 3383.085 3656.935 3383.425 ;
    END
    PORT
      LAYER met3 ;
        RECT 3114.49 1745.085 3656.935 1745.425 ;
        RECT 3114.49 1861.565 3656.935 1861.905 ;
        RECT 3114.49 1978.045 3656.935 1978.385 ;
        RECT 3114.49 2094.525 3656.935 2094.865 ;
        RECT 3114.49 2211.005 3656.935 2211.345 ;
        RECT 3114.49 2327.485 3656.935 2327.825 ;
        RECT 3114.49 2443.965 3656.935 2444.305 ;
        RECT 3114.49 2560.445 3656.935 2560.785 ;
        RECT 3114.49 2676.925 3656.935 2677.265 ;
        RECT 3114.49 2793.405 3656.935 2793.745 ;
        RECT 3114.49 2909.885 3656.935 2910.225 ;
        RECT 3114.49 3026.365 3656.935 3026.705 ;
        RECT 3114.49 3142.845 3656.935 3143.185 ;
        RECT 3114.49 3259.325 3656.935 3259.665 ;
        RECT 3114.49 3375.805 3656.935 3376.145 ;
    END
    PORT
      LAYER met3 ;
        RECT 3114.49 1737.805 3656.935 1738.145 ;
        RECT 3114.49 1854.285 3656.935 1854.625 ;
        RECT 3114.49 1970.765 3656.935 1971.105 ;
        RECT 3114.49 2087.245 3656.935 2087.585 ;
        RECT 3114.49 2203.725 3656.935 2204.065 ;
        RECT 3114.49 2320.205 3656.935 2320.545 ;
        RECT 3114.49 2436.685 3656.935 2437.025 ;
        RECT 3114.49 2553.165 3656.935 2553.505 ;
        RECT 3114.49 2669.645 3656.935 2669.985 ;
        RECT 3114.49 2786.125 3656.935 2786.465 ;
        RECT 3114.49 2902.605 3656.935 2902.945 ;
        RECT 3114.49 3019.085 3656.935 3019.425 ;
        RECT 3114.49 3135.565 3656.935 3135.905 ;
        RECT 3114.49 3252.045 3656.935 3252.385 ;
        RECT 3114.49 3368.525 3656.935 3368.865 ;
    END
    PORT
      LAYER met3 ;
        RECT 3114.49 1730.525 3656.935 1730.865 ;
        RECT 3114.49 1847.005 3656.935 1847.345 ;
        RECT 3114.49 1963.485 3656.935 1963.825 ;
        RECT 3114.49 2079.965 3656.935 2080.305 ;
        RECT 3114.49 2196.445 3656.935 2196.785 ;
        RECT 3114.49 2312.925 3656.935 2313.265 ;
        RECT 3114.49 2429.405 3656.935 2429.745 ;
        RECT 3114.49 2545.885 3656.935 2546.225 ;
        RECT 3114.49 2662.365 3656.935 2662.705 ;
        RECT 3114.49 2778.845 3656.935 2779.185 ;
        RECT 3114.49 2895.325 3656.935 2895.665 ;
        RECT 3114.49 3011.805 3656.935 3012.145 ;
        RECT 3114.49 3128.285 3656.935 3128.625 ;
        RECT 3114.49 3244.765 3656.935 3245.105 ;
        RECT 3114.49 3361.245 3656.935 3361.585 ;
    END
    PORT
      LAYER met3 ;
        RECT 3114.49 1723.245 3656.935 1723.585 ;
        RECT 3114.49 1839.725 3656.935 1840.065 ;
        RECT 3114.49 1956.205 3656.935 1956.545 ;
        RECT 3114.49 2072.685 3656.935 2073.025 ;
        RECT 3114.49 2189.165 3656.935 2189.505 ;
        RECT 3114.49 2305.645 3656.935 2305.985 ;
        RECT 3114.49 2422.125 3656.935 2422.465 ;
        RECT 3114.49 2538.605 3656.935 2538.945 ;
        RECT 3114.49 2655.085 3656.935 2655.425 ;
        RECT 3114.49 2771.565 3656.935 2771.905 ;
        RECT 3114.49 2888.045 3656.935 2888.385 ;
        RECT 3114.49 3004.525 3656.935 3004.865 ;
        RECT 3114.49 3121.005 3656.935 3121.345 ;
        RECT 3114.49 3237.485 3656.935 3237.825 ;
        RECT 3114.49 3353.965 3656.935 3354.305 ;
    END
    PORT
      LAYER met3 ;
        RECT 3114.49 1715.965 3656.935 1716.305 ;
        RECT 3114.49 1832.445 3656.935 1832.785 ;
        RECT 3114.49 1948.925 3656.935 1949.265 ;
        RECT 3114.49 2065.405 3656.935 2065.745 ;
        RECT 3114.49 2181.885 3656.935 2182.225 ;
        RECT 3114.49 2298.365 3656.935 2298.705 ;
        RECT 3114.49 2414.845 3656.935 2415.185 ;
        RECT 3114.49 2531.325 3656.935 2531.665 ;
        RECT 3114.49 2647.805 3656.935 2648.145 ;
        RECT 3114.49 2764.285 3656.935 2764.625 ;
        RECT 3114.49 2880.765 3656.935 2881.105 ;
        RECT 3114.49 2997.245 3656.935 2997.585 ;
        RECT 3114.49 3113.725 3656.935 3114.065 ;
        RECT 3114.49 3230.205 3656.935 3230.545 ;
        RECT 3114.49 3346.685 3656.935 3347.025 ;
    END
    PORT
      LAYER met3 ;
        RECT 3114.49 1708.685 3656.935 1709.025 ;
        RECT 3114.49 1825.165 3656.935 1825.505 ;
        RECT 3114.49 1941.645 3656.935 1941.985 ;
        RECT 3114.49 2058.125 3656.935 2058.465 ;
        RECT 3114.49 2174.605 3656.935 2174.945 ;
        RECT 3114.49 2291.085 3656.935 2291.425 ;
        RECT 3114.49 2407.565 3656.935 2407.905 ;
        RECT 3114.49 2524.045 3656.935 2524.385 ;
        RECT 3114.49 2640.525 3656.935 2640.865 ;
        RECT 3114.49 2757.005 3656.935 2757.345 ;
        RECT 3114.49 2873.485 3656.935 2873.825 ;
        RECT 3114.49 2989.965 3656.935 2990.305 ;
        RECT 3114.49 3106.445 3656.935 3106.785 ;
        RECT 3114.49 3222.925 3656.935 3223.265 ;
        RECT 3114.49 3339.405 3656.935 3339.745 ;
    END
    PORT
      LAYER met3 ;
        RECT 3114.49 1701.405 3656.935 1701.745 ;
        RECT 3114.49 1817.885 3656.935 1818.225 ;
        RECT 3114.49 1934.365 3656.935 1934.705 ;
        RECT 3114.49 2050.845 3656.935 2051.185 ;
        RECT 3114.49 2167.325 3656.935 2167.665 ;
        RECT 3114.49 2283.805 3656.935 2284.145 ;
        RECT 3114.49 2400.285 3656.935 2400.625 ;
        RECT 3114.49 2516.765 3656.935 2517.105 ;
        RECT 3114.49 2633.245 3656.935 2633.585 ;
        RECT 3114.49 2749.725 3656.935 2750.065 ;
        RECT 3114.49 2866.205 3656.935 2866.545 ;
        RECT 3114.49 2982.685 3656.935 2983.025 ;
        RECT 3114.49 3099.165 3656.935 3099.505 ;
        RECT 3114.49 3215.645 3656.935 3215.985 ;
        RECT 3114.49 3332.125 3656.935 3332.465 ;
    END
    PORT
      LAYER met3 ;
        RECT 3114.49 1694.125 3656.935 1694.465 ;
        RECT 3114.49 1810.605 3656.935 1810.945 ;
        RECT 3114.49 1927.085 3656.935 1927.425 ;
        RECT 3114.49 2043.565 3656.935 2043.905 ;
        RECT 3114.49 2160.045 3656.935 2160.385 ;
        RECT 3114.49 2276.525 3656.935 2276.865 ;
        RECT 3114.49 2393.005 3656.935 2393.345 ;
        RECT 3114.49 2509.485 3656.935 2509.825 ;
        RECT 3114.49 2625.965 3656.935 2626.305 ;
        RECT 3114.49 2742.445 3656.935 2742.785 ;
        RECT 3114.49 2858.925 3656.935 2859.265 ;
        RECT 3114.49 2975.405 3656.935 2975.745 ;
        RECT 3114.49 3091.885 3656.935 3092.225 ;
        RECT 3114.49 3208.365 3656.935 3208.705 ;
        RECT 3114.49 3324.845 3656.935 3325.185 ;
    END
    PORT
      LAYER met3 ;
        RECT 216.99 1808.47 739.5 1808.81 ;
        RECT 216.99 1924.95 739.5 1925.29 ;
        RECT 216.99 2041.43 739.5 2041.77 ;
        RECT 216.99 2157.91 739.5 2158.25 ;
        RECT 216.99 2274.39 739.5 2274.73 ;
        RECT 216.99 2390.87 739.5 2391.21 ;
        RECT 216.99 2507.35 739.5 2507.69 ;
        RECT 216.99 2623.83 739.5 2624.17 ;
        RECT 216.99 2740.31 739.5 2740.65 ;
        RECT 216.99 2856.79 739.5 2857.13 ;
        RECT 216.99 2973.27 739.5 2973.61 ;
        RECT 216.99 3089.75 739.5 3090.09 ;
        RECT 216.99 3206.23 739.5 3206.57 ;
        RECT 216.99 3322.71 739.5 3323.05 ;
        RECT 216.99 3439.19 739.5 3439.53 ;
    END
    PORT
      LAYER met3 ;
        RECT 216.99 1805.75 739.5 1806.09 ;
        RECT 216.99 1922.23 739.5 1922.57 ;
        RECT 216.99 2038.71 739.5 2039.05 ;
        RECT 216.99 2155.19 739.5 2155.53 ;
        RECT 216.99 2271.67 739.5 2272.01 ;
        RECT 216.99 2388.15 739.5 2388.49 ;
        RECT 216.99 2504.63 739.5 2504.97 ;
        RECT 216.99 2621.11 739.5 2621.45 ;
        RECT 216.99 2737.59 739.5 2737.93 ;
        RECT 216.99 2854.07 739.5 2854.41 ;
        RECT 216.99 2970.55 739.5 2970.89 ;
        RECT 216.99 3087.03 739.5 3087.37 ;
        RECT 216.99 3203.51 739.5 3203.85 ;
        RECT 216.99 3319.99 739.5 3320.33 ;
        RECT 216.99 3436.47 739.5 3436.81 ;
    END
    PORT
      LAYER met3 ;
        RECT 216.99 1801.19 739.5 1801.53 ;
        RECT 216.99 1917.67 739.5 1918.01 ;
        RECT 216.99 2034.15 739.5 2034.49 ;
        RECT 216.99 2150.63 739.5 2150.97 ;
        RECT 216.99 2267.11 739.5 2267.45 ;
        RECT 216.99 2383.59 739.5 2383.93 ;
        RECT 216.99 2500.07 739.5 2500.41 ;
        RECT 216.99 2616.55 739.5 2616.89 ;
        RECT 216.99 2733.03 739.5 2733.37 ;
        RECT 216.99 2849.51 739.5 2849.85 ;
        RECT 216.99 2965.99 739.5 2966.33 ;
        RECT 216.99 3082.47 739.5 3082.81 ;
        RECT 216.99 3198.95 739.5 3199.29 ;
        RECT 216.99 3315.43 739.5 3315.77 ;
        RECT 216.99 3431.91 739.5 3432.25 ;
    END
    PORT
      LAYER met3 ;
        RECT 216.99 1798.47 739.5 1798.81 ;
        RECT 216.99 1914.95 739.5 1915.29 ;
        RECT 216.99 2031.43 739.5 2031.77 ;
        RECT 216.99 2147.91 739.5 2148.25 ;
        RECT 216.99 2264.39 739.5 2264.73 ;
        RECT 216.99 2380.87 739.5 2381.21 ;
        RECT 216.99 2497.35 739.5 2497.69 ;
        RECT 216.99 2613.83 739.5 2614.17 ;
        RECT 216.99 2730.31 739.5 2730.65 ;
        RECT 216.99 2846.79 739.5 2847.13 ;
        RECT 216.99 2963.27 739.5 2963.61 ;
        RECT 216.99 3079.75 739.5 3080.09 ;
        RECT 216.99 3196.23 739.5 3196.57 ;
        RECT 216.99 3312.71 739.5 3313.05 ;
        RECT 216.99 3429.19 739.5 3429.53 ;
    END
    PORT
      LAYER met3 ;
        RECT 216.99 1793.91 739.5 1794.25 ;
        RECT 216.99 1910.39 739.5 1910.73 ;
        RECT 216.99 2026.87 739.5 2027.21 ;
        RECT 216.99 2143.35 739.5 2143.69 ;
        RECT 216.99 2259.83 739.5 2260.17 ;
        RECT 216.99 2376.31 739.5 2376.65 ;
        RECT 216.99 2492.79 739.5 2493.13 ;
        RECT 216.99 2609.27 739.5 2609.61 ;
        RECT 216.99 2725.75 739.5 2726.09 ;
        RECT 216.99 2842.23 739.5 2842.57 ;
        RECT 216.99 2958.71 739.5 2959.05 ;
        RECT 216.99 3075.19 739.5 3075.53 ;
        RECT 216.99 3191.67 739.5 3192.01 ;
        RECT 216.99 3308.15 739.5 3308.49 ;
        RECT 216.99 3424.63 739.5 3424.97 ;
    END
    PORT
      LAYER met3 ;
        RECT 216.99 1791.19 739.5 1791.53 ;
        RECT 216.99 1907.67 739.5 1908.01 ;
        RECT 216.99 2024.15 739.5 2024.49 ;
        RECT 216.99 2140.63 739.5 2140.97 ;
        RECT 216.99 2257.11 739.5 2257.45 ;
        RECT 216.99 2373.59 739.5 2373.93 ;
        RECT 216.99 2490.07 739.5 2490.41 ;
        RECT 216.99 2606.55 739.5 2606.89 ;
        RECT 216.99 2723.03 739.5 2723.37 ;
        RECT 216.99 2839.51 739.5 2839.85 ;
        RECT 216.99 2955.99 739.5 2956.33 ;
        RECT 216.99 3072.47 739.5 3072.81 ;
        RECT 216.99 3188.95 739.5 3189.29 ;
        RECT 216.99 3305.43 739.5 3305.77 ;
        RECT 216.99 3421.91 739.5 3422.25 ;
    END
    PORT
      LAYER met3 ;
        RECT 216.99 1786.63 739.5 1786.97 ;
        RECT 216.99 1903.11 739.5 1903.45 ;
        RECT 216.99 2019.59 739.5 2019.93 ;
        RECT 216.99 2136.07 739.5 2136.41 ;
        RECT 216.99 2252.55 739.5 2252.89 ;
        RECT 216.99 2369.03 739.5 2369.37 ;
        RECT 216.99 2485.51 739.5 2485.85 ;
        RECT 216.99 2601.99 739.5 2602.33 ;
        RECT 216.99 2718.47 739.5 2718.81 ;
        RECT 216.99 2834.95 739.5 2835.29 ;
        RECT 216.99 2951.43 739.5 2951.77 ;
        RECT 216.99 3067.91 739.5 3068.25 ;
        RECT 216.99 3184.39 739.5 3184.73 ;
        RECT 216.99 3300.87 739.5 3301.21 ;
        RECT 216.99 3417.35 739.5 3417.69 ;
    END
    PORT
      LAYER met3 ;
        RECT 216.99 1783.91 739.5 1784.25 ;
        RECT 216.99 1900.39 739.5 1900.73 ;
        RECT 216.99 2016.87 739.5 2017.21 ;
        RECT 216.99 2133.35 739.5 2133.69 ;
        RECT 216.99 2249.83 739.5 2250.17 ;
        RECT 216.99 2366.31 739.5 2366.65 ;
        RECT 216.99 2482.79 739.5 2483.13 ;
        RECT 216.99 2599.27 739.5 2599.61 ;
        RECT 216.99 2715.75 739.5 2716.09 ;
        RECT 216.99 2832.23 739.5 2832.57 ;
        RECT 216.99 2948.71 739.5 2949.05 ;
        RECT 216.99 3065.19 739.5 3065.53 ;
        RECT 216.99 3181.67 739.5 3182.01 ;
        RECT 216.99 3298.15 739.5 3298.49 ;
        RECT 216.99 3414.63 739.5 3414.97 ;
    END
    PORT
      LAYER met3 ;
        RECT 216.99 1779.35 739.5 1779.69 ;
        RECT 216.99 1895.83 739.5 1896.17 ;
        RECT 216.99 2012.31 739.5 2012.65 ;
        RECT 216.99 2128.79 739.5 2129.13 ;
        RECT 216.99 2245.27 739.5 2245.61 ;
        RECT 216.99 2361.75 739.5 2362.09 ;
        RECT 216.99 2478.23 739.5 2478.57 ;
        RECT 216.99 2594.71 739.5 2595.05 ;
        RECT 216.99 2711.19 739.5 2711.53 ;
        RECT 216.99 2827.67 739.5 2828.01 ;
        RECT 216.99 2944.15 739.5 2944.49 ;
        RECT 216.99 3060.63 739.5 3060.97 ;
        RECT 216.99 3177.11 739.5 3177.45 ;
        RECT 216.99 3293.59 739.5 3293.93 ;
        RECT 216.99 3410.07 739.5 3410.41 ;
    END
    PORT
      LAYER met3 ;
        RECT 216.99 1776.63 739.5 1776.97 ;
        RECT 216.99 1893.11 739.5 1893.45 ;
        RECT 216.99 2009.59 739.5 2009.93 ;
        RECT 216.99 2126.07 739.5 2126.41 ;
        RECT 216.99 2242.55 739.5 2242.89 ;
        RECT 216.99 2359.03 739.5 2359.37 ;
        RECT 216.99 2475.51 739.5 2475.85 ;
        RECT 216.99 2591.99 739.5 2592.33 ;
        RECT 216.99 2708.47 739.5 2708.81 ;
        RECT 216.99 2824.95 739.5 2825.29 ;
        RECT 216.99 2941.43 739.5 2941.77 ;
        RECT 216.99 3057.91 739.5 3058.25 ;
        RECT 216.99 3174.39 739.5 3174.73 ;
        RECT 216.99 3290.87 739.5 3291.21 ;
        RECT 216.99 3407.35 739.5 3407.69 ;
    END
    PORT
      LAYER met3 ;
        RECT 216.99 1772.07 739.5 1772.41 ;
        RECT 216.99 1888.55 739.5 1888.89 ;
        RECT 216.99 2005.03 739.5 2005.37 ;
        RECT 216.99 2121.51 739.5 2121.85 ;
        RECT 216.99 2237.99 739.5 2238.33 ;
        RECT 216.99 2354.47 739.5 2354.81 ;
        RECT 216.99 2470.95 739.5 2471.29 ;
        RECT 216.99 2587.43 739.5 2587.77 ;
        RECT 216.99 2703.91 739.5 2704.25 ;
        RECT 216.99 2820.39 739.5 2820.73 ;
        RECT 216.99 2936.87 739.5 2937.21 ;
        RECT 216.99 3053.35 739.5 3053.69 ;
        RECT 216.99 3169.83 739.5 3170.17 ;
        RECT 216.99 3286.31 739.5 3286.65 ;
        RECT 216.99 3402.79 739.5 3403.13 ;
    END
    PORT
      LAYER met3 ;
        RECT 216.99 1769.35 739.5 1769.69 ;
        RECT 216.99 1885.83 739.5 1886.17 ;
        RECT 216.99 2002.31 739.5 2002.65 ;
        RECT 216.99 2118.79 739.5 2119.13 ;
        RECT 216.99 2235.27 739.5 2235.61 ;
        RECT 216.99 2351.75 739.5 2352.09 ;
        RECT 216.99 2468.23 739.5 2468.57 ;
        RECT 216.99 2584.71 739.5 2585.05 ;
        RECT 216.99 2701.19 739.5 2701.53 ;
        RECT 216.99 2817.67 739.5 2818.01 ;
        RECT 216.99 2934.15 739.5 2934.49 ;
        RECT 216.99 3050.63 739.5 3050.97 ;
        RECT 216.99 3167.11 739.5 3167.45 ;
        RECT 216.99 3283.59 739.5 3283.93 ;
        RECT 216.99 3400.07 739.5 3400.41 ;
    END
    PORT
      LAYER met3 ;
        RECT 216.99 1764.79 739.5 1765.13 ;
        RECT 216.99 1881.27 739.5 1881.61 ;
        RECT 216.99 1997.75 739.5 1998.09 ;
        RECT 216.99 2114.23 739.5 2114.57 ;
        RECT 216.99 2230.71 739.5 2231.05 ;
        RECT 216.99 2347.19 739.5 2347.53 ;
        RECT 216.99 2463.67 739.5 2464.01 ;
        RECT 216.99 2580.15 739.5 2580.49 ;
        RECT 216.99 2696.63 739.5 2696.97 ;
        RECT 216.99 2813.11 739.5 2813.45 ;
        RECT 216.99 2929.59 739.5 2929.93 ;
        RECT 216.99 3046.07 739.5 3046.41 ;
        RECT 216.99 3162.55 739.5 3162.89 ;
        RECT 216.99 3279.03 739.5 3279.37 ;
        RECT 216.99 3395.51 739.5 3395.85 ;
    END
    PORT
      LAYER met3 ;
        RECT 216.99 1762.07 739.5 1762.41 ;
        RECT 216.99 1878.55 739.5 1878.89 ;
        RECT 216.99 1995.03 739.5 1995.37 ;
        RECT 216.99 2111.51 739.5 2111.85 ;
        RECT 216.99 2227.99 739.5 2228.33 ;
        RECT 216.99 2344.47 739.5 2344.81 ;
        RECT 216.99 2460.95 739.5 2461.29 ;
        RECT 216.99 2577.43 739.5 2577.77 ;
        RECT 216.99 2693.91 739.5 2694.25 ;
        RECT 216.99 2810.39 739.5 2810.73 ;
        RECT 216.99 2926.87 739.5 2927.21 ;
        RECT 216.99 3043.35 739.5 3043.69 ;
        RECT 216.99 3159.83 739.5 3160.17 ;
        RECT 216.99 3276.31 739.5 3276.65 ;
        RECT 216.99 3392.79 739.5 3393.13 ;
    END
    PORT
      LAYER met3 ;
        RECT 216.99 1757.51 739.5 1757.85 ;
        RECT 216.99 1873.99 739.5 1874.33 ;
        RECT 216.99 1990.47 739.5 1990.81 ;
        RECT 216.99 2106.95 739.5 2107.29 ;
        RECT 216.99 2223.43 739.5 2223.77 ;
        RECT 216.99 2339.91 739.5 2340.25 ;
        RECT 216.99 2456.39 739.5 2456.73 ;
        RECT 216.99 2572.87 739.5 2573.21 ;
        RECT 216.99 2689.35 739.5 2689.69 ;
        RECT 216.99 2805.83 739.5 2806.17 ;
        RECT 216.99 2922.31 739.5 2922.65 ;
        RECT 216.99 3038.79 739.5 3039.13 ;
        RECT 216.99 3155.27 739.5 3155.61 ;
        RECT 216.99 3271.75 739.5 3272.09 ;
        RECT 216.99 3388.23 739.5 3388.57 ;
    END
    PORT
      LAYER met3 ;
        RECT 216.99 1754.79 739.5 1755.13 ;
        RECT 216.99 1871.27 739.5 1871.61 ;
        RECT 216.99 1987.75 739.5 1988.09 ;
        RECT 216.99 2104.23 739.5 2104.57 ;
        RECT 216.99 2220.71 739.5 2221.05 ;
        RECT 216.99 2337.19 739.5 2337.53 ;
        RECT 216.99 2453.67 739.5 2454.01 ;
        RECT 216.99 2570.15 739.5 2570.49 ;
        RECT 216.99 2686.63 739.5 2686.97 ;
        RECT 216.99 2803.11 739.5 2803.45 ;
        RECT 216.99 2919.59 739.5 2919.93 ;
        RECT 216.99 3036.07 739.5 3036.41 ;
        RECT 216.99 3152.55 739.5 3152.89 ;
        RECT 216.99 3269.03 739.5 3269.37 ;
        RECT 216.99 3385.51 739.5 3385.85 ;
    END
    PORT
      LAYER met3 ;
        RECT 216.99 1750.23 739.5 1750.57 ;
        RECT 216.99 1866.71 739.5 1867.05 ;
        RECT 216.99 1983.19 739.5 1983.53 ;
        RECT 216.99 2099.67 739.5 2100.01 ;
        RECT 216.99 2216.15 739.5 2216.49 ;
        RECT 216.99 2332.63 739.5 2332.97 ;
        RECT 216.99 2449.11 739.5 2449.45 ;
        RECT 216.99 2565.59 739.5 2565.93 ;
        RECT 216.99 2682.07 739.5 2682.41 ;
        RECT 216.99 2798.55 739.5 2798.89 ;
        RECT 216.99 2915.03 739.5 2915.37 ;
        RECT 216.99 3031.51 739.5 3031.85 ;
        RECT 216.99 3147.99 739.5 3148.33 ;
        RECT 216.99 3264.47 739.5 3264.81 ;
        RECT 216.99 3380.95 739.5 3381.29 ;
    END
    PORT
      LAYER met3 ;
        RECT 216.99 1747.51 739.5 1747.85 ;
        RECT 216.99 1863.99 739.5 1864.33 ;
        RECT 216.99 1980.47 739.5 1980.81 ;
        RECT 216.99 2096.95 739.5 2097.29 ;
        RECT 216.99 2213.43 739.5 2213.77 ;
        RECT 216.99 2329.91 739.5 2330.25 ;
        RECT 216.99 2446.39 739.5 2446.73 ;
        RECT 216.99 2562.87 739.5 2563.21 ;
        RECT 216.99 2679.35 739.5 2679.69 ;
        RECT 216.99 2795.83 739.5 2796.17 ;
        RECT 216.99 2912.31 739.5 2912.65 ;
        RECT 216.99 3028.79 739.5 3029.13 ;
        RECT 216.99 3145.27 739.5 3145.61 ;
        RECT 216.99 3261.75 739.5 3262.09 ;
        RECT 216.99 3378.23 739.5 3378.57 ;
    END
    PORT
      LAYER met3 ;
        RECT 216.99 1742.95 739.5 1743.29 ;
        RECT 216.99 1859.43 739.5 1859.77 ;
        RECT 216.99 1975.91 739.5 1976.25 ;
        RECT 216.99 2092.39 739.5 2092.73 ;
        RECT 216.99 2208.87 739.5 2209.21 ;
        RECT 216.99 2325.35 739.5 2325.69 ;
        RECT 216.99 2441.83 739.5 2442.17 ;
        RECT 216.99 2558.31 739.5 2558.65 ;
        RECT 216.99 2674.79 739.5 2675.13 ;
        RECT 216.99 2791.27 739.5 2791.61 ;
        RECT 216.99 2907.75 739.5 2908.09 ;
        RECT 216.99 3024.23 739.5 3024.57 ;
        RECT 216.99 3140.71 739.5 3141.05 ;
        RECT 216.99 3257.19 739.5 3257.53 ;
        RECT 216.99 3373.67 739.5 3374.01 ;
    END
    PORT
      LAYER met3 ;
        RECT 216.99 1740.23 739.5 1740.57 ;
        RECT 216.99 1856.71 739.5 1857.05 ;
        RECT 216.99 1973.19 739.5 1973.53 ;
        RECT 216.99 2089.67 739.5 2090.01 ;
        RECT 216.99 2206.15 739.5 2206.49 ;
        RECT 216.99 2322.63 739.5 2322.97 ;
        RECT 216.99 2439.11 739.5 2439.45 ;
        RECT 216.99 2555.59 739.5 2555.93 ;
        RECT 216.99 2672.07 739.5 2672.41 ;
        RECT 216.99 2788.55 739.5 2788.89 ;
        RECT 216.99 2905.03 739.5 2905.37 ;
        RECT 216.99 3021.51 739.5 3021.85 ;
        RECT 216.99 3137.99 739.5 3138.33 ;
        RECT 216.99 3254.47 739.5 3254.81 ;
        RECT 216.99 3370.95 739.5 3371.29 ;
    END
    PORT
      LAYER met3 ;
        RECT 216.99 1735.67 739.5 1736.01 ;
        RECT 216.99 1852.15 739.5 1852.49 ;
        RECT 216.99 1968.63 739.5 1968.97 ;
        RECT 216.99 2085.11 739.5 2085.45 ;
        RECT 216.99 2201.59 739.5 2201.93 ;
        RECT 216.99 2318.07 739.5 2318.41 ;
        RECT 216.99 2434.55 739.5 2434.89 ;
        RECT 216.99 2551.03 739.5 2551.37 ;
        RECT 216.99 2667.51 739.5 2667.85 ;
        RECT 216.99 2783.99 739.5 2784.33 ;
        RECT 216.99 2900.47 739.5 2900.81 ;
        RECT 216.99 3016.95 739.5 3017.29 ;
        RECT 216.99 3133.43 739.5 3133.77 ;
        RECT 216.99 3249.91 739.5 3250.25 ;
        RECT 216.99 3366.39 739.5 3366.73 ;
    END
    PORT
      LAYER met3 ;
        RECT 216.99 1732.95 739.5 1733.29 ;
        RECT 216.99 1849.43 739.5 1849.77 ;
        RECT 216.99 1965.91 739.5 1966.25 ;
        RECT 216.99 2082.39 739.5 2082.73 ;
        RECT 216.99 2198.87 739.5 2199.21 ;
        RECT 216.99 2315.35 739.5 2315.69 ;
        RECT 216.99 2431.83 739.5 2432.17 ;
        RECT 216.99 2548.31 739.5 2548.65 ;
        RECT 216.99 2664.79 739.5 2665.13 ;
        RECT 216.99 2781.27 739.5 2781.61 ;
        RECT 216.99 2897.75 739.5 2898.09 ;
        RECT 216.99 3014.23 739.5 3014.57 ;
        RECT 216.99 3130.71 739.5 3131.05 ;
        RECT 216.99 3247.19 739.5 3247.53 ;
        RECT 216.99 3363.67 739.5 3364.01 ;
    END
    PORT
      LAYER met3 ;
        RECT 216.99 1728.39 739.5 1728.73 ;
        RECT 216.99 1844.87 739.5 1845.21 ;
        RECT 216.99 1961.35 739.5 1961.69 ;
        RECT 216.99 2077.83 739.5 2078.17 ;
        RECT 216.99 2194.31 739.5 2194.65 ;
        RECT 216.99 2310.79 739.5 2311.13 ;
        RECT 216.99 2427.27 739.5 2427.61 ;
        RECT 216.99 2543.75 739.5 2544.09 ;
        RECT 216.99 2660.23 739.5 2660.57 ;
        RECT 216.99 2776.71 739.5 2777.05 ;
        RECT 216.99 2893.19 739.5 2893.53 ;
        RECT 216.99 3009.67 739.5 3010.01 ;
        RECT 216.99 3126.15 739.5 3126.49 ;
        RECT 216.99 3242.63 739.5 3242.97 ;
        RECT 216.99 3359.11 739.5 3359.45 ;
    END
    PORT
      LAYER met3 ;
        RECT 216.99 1725.67 739.5 1726.01 ;
        RECT 216.99 1842.15 739.5 1842.49 ;
        RECT 216.99 1958.63 739.5 1958.97 ;
        RECT 216.99 2075.11 739.5 2075.45 ;
        RECT 216.99 2191.59 739.5 2191.93 ;
        RECT 216.99 2308.07 739.5 2308.41 ;
        RECT 216.99 2424.55 739.5 2424.89 ;
        RECT 216.99 2541.03 739.5 2541.37 ;
        RECT 216.99 2657.51 739.5 2657.85 ;
        RECT 216.99 2773.99 739.5 2774.33 ;
        RECT 216.99 2890.47 739.5 2890.81 ;
        RECT 216.99 3006.95 739.5 3007.29 ;
        RECT 216.99 3123.43 739.5 3123.77 ;
        RECT 216.99 3239.91 739.5 3240.25 ;
        RECT 216.99 3356.39 739.5 3356.73 ;
    END
    PORT
      LAYER met3 ;
        RECT 216.99 1721.11 739.5 1721.45 ;
        RECT 216.99 1837.59 739.5 1837.93 ;
        RECT 216.99 1954.07 739.5 1954.41 ;
        RECT 216.99 2070.55 739.5 2070.89 ;
        RECT 216.99 2187.03 739.5 2187.37 ;
        RECT 216.99 2303.51 739.5 2303.85 ;
        RECT 216.99 2419.99 739.5 2420.33 ;
        RECT 216.99 2536.47 739.5 2536.81 ;
        RECT 216.99 2652.95 739.5 2653.29 ;
        RECT 216.99 2769.43 739.5 2769.77 ;
        RECT 216.99 2885.91 739.5 2886.25 ;
        RECT 216.99 3002.39 739.5 3002.73 ;
        RECT 216.99 3118.87 739.5 3119.21 ;
        RECT 216.99 3235.35 739.5 3235.69 ;
        RECT 216.99 3351.83 739.5 3352.17 ;
    END
    PORT
      LAYER met3 ;
        RECT 216.99 1718.39 739.5 1718.73 ;
        RECT 216.99 1834.87 739.5 1835.21 ;
        RECT 216.99 1951.35 739.5 1951.69 ;
        RECT 216.99 2067.83 739.5 2068.17 ;
        RECT 216.99 2184.31 739.5 2184.65 ;
        RECT 216.99 2300.79 739.5 2301.13 ;
        RECT 216.99 2417.27 739.5 2417.61 ;
        RECT 216.99 2533.75 739.5 2534.09 ;
        RECT 216.99 2650.23 739.5 2650.57 ;
        RECT 216.99 2766.71 739.5 2767.05 ;
        RECT 216.99 2883.19 739.5 2883.53 ;
        RECT 216.99 2999.67 739.5 3000.01 ;
        RECT 216.99 3116.15 739.5 3116.49 ;
        RECT 216.99 3232.63 739.5 3232.97 ;
        RECT 216.99 3349.11 739.5 3349.45 ;
    END
    PORT
      LAYER met3 ;
        RECT 216.99 1713.83 739.5 1714.17 ;
        RECT 216.99 1830.31 739.5 1830.65 ;
        RECT 216.99 1946.79 739.5 1947.13 ;
        RECT 216.99 2063.27 739.5 2063.61 ;
        RECT 216.99 2179.75 739.5 2180.09 ;
        RECT 216.99 2296.23 739.5 2296.57 ;
        RECT 216.99 2412.71 739.5 2413.05 ;
        RECT 216.99 2529.19 739.5 2529.53 ;
        RECT 216.99 2645.67 739.5 2646.01 ;
        RECT 216.99 2762.15 739.5 2762.49 ;
        RECT 216.99 2878.63 739.5 2878.97 ;
        RECT 216.99 2995.11 739.5 2995.45 ;
        RECT 216.99 3111.59 739.5 3111.93 ;
        RECT 216.99 3228.07 739.5 3228.41 ;
        RECT 216.99 3344.55 739.5 3344.89 ;
    END
    PORT
      LAYER met3 ;
        RECT 216.99 1711.11 739.5 1711.45 ;
        RECT 216.99 1827.59 739.5 1827.93 ;
        RECT 216.99 1944.07 739.5 1944.41 ;
        RECT 216.99 2060.55 739.5 2060.89 ;
        RECT 216.99 2177.03 739.5 2177.37 ;
        RECT 216.99 2293.51 739.5 2293.85 ;
        RECT 216.99 2409.99 739.5 2410.33 ;
        RECT 216.99 2526.47 739.5 2526.81 ;
        RECT 216.99 2642.95 739.5 2643.29 ;
        RECT 216.99 2759.43 739.5 2759.77 ;
        RECT 216.99 2875.91 739.5 2876.25 ;
        RECT 216.99 2992.39 739.5 2992.73 ;
        RECT 216.99 3108.87 739.5 3109.21 ;
        RECT 216.99 3225.35 739.5 3225.69 ;
        RECT 216.99 3341.83 739.5 3342.17 ;
    END
    PORT
      LAYER met3 ;
        RECT 216.99 1706.55 739.5 1706.89 ;
        RECT 216.99 1823.03 739.5 1823.37 ;
        RECT 216.99 1939.51 739.5 1939.85 ;
        RECT 216.99 2055.99 739.5 2056.33 ;
        RECT 216.99 2172.47 739.5 2172.81 ;
        RECT 216.99 2288.95 739.5 2289.29 ;
        RECT 216.99 2405.43 739.5 2405.77 ;
        RECT 216.99 2521.91 739.5 2522.25 ;
        RECT 216.99 2638.39 739.5 2638.73 ;
        RECT 216.99 2754.87 739.5 2755.21 ;
        RECT 216.99 2871.35 739.5 2871.69 ;
        RECT 216.99 2987.83 739.5 2988.17 ;
        RECT 216.99 3104.31 739.5 3104.65 ;
        RECT 216.99 3220.79 739.5 3221.13 ;
        RECT 216.99 3337.27 739.5 3337.61 ;
    END
    PORT
      LAYER met3 ;
        RECT 216.99 1703.83 739.5 1704.17 ;
        RECT 216.99 1820.31 739.5 1820.65 ;
        RECT 216.99 1936.79 739.5 1937.13 ;
        RECT 216.99 2053.27 739.5 2053.61 ;
        RECT 216.99 2169.75 739.5 2170.09 ;
        RECT 216.99 2286.23 739.5 2286.57 ;
        RECT 216.99 2402.71 739.5 2403.05 ;
        RECT 216.99 2519.19 739.5 2519.53 ;
        RECT 216.99 2635.67 739.5 2636.01 ;
        RECT 216.99 2752.15 739.5 2752.49 ;
        RECT 216.99 2868.63 739.5 2868.97 ;
        RECT 216.99 2985.11 739.5 2985.45 ;
        RECT 216.99 3101.59 739.5 3101.93 ;
        RECT 216.99 3218.07 739.5 3218.41 ;
        RECT 216.99 3334.55 739.5 3334.89 ;
    END
    PORT
      LAYER met3 ;
        RECT 216.99 1699.27 739.5 1699.61 ;
        RECT 216.99 1815.75 739.5 1816.09 ;
        RECT 216.99 1932.23 739.5 1932.57 ;
        RECT 216.99 2048.71 739.5 2049.05 ;
        RECT 216.99 2165.19 739.5 2165.53 ;
        RECT 216.99 2281.67 739.5 2282.01 ;
        RECT 216.99 2398.15 739.5 2398.49 ;
        RECT 216.99 2514.63 739.5 2514.97 ;
        RECT 216.99 2631.11 739.5 2631.45 ;
        RECT 216.99 2747.59 739.5 2747.93 ;
        RECT 216.99 2864.07 739.5 2864.41 ;
        RECT 216.99 2980.55 739.5 2980.89 ;
        RECT 216.99 3097.03 739.5 3097.37 ;
        RECT 216.99 3213.51 739.5 3213.85 ;
        RECT 216.99 3329.99 739.5 3330.33 ;
    END
    PORT
      LAYER met3 ;
        RECT 216.99 1696.55 739.5 1696.89 ;
        RECT 216.99 1813.03 739.5 1813.37 ;
        RECT 216.99 1929.51 739.5 1929.85 ;
        RECT 216.99 2045.99 739.5 2046.33 ;
        RECT 216.99 2162.47 739.5 2162.81 ;
        RECT 216.99 2278.95 739.5 2279.29 ;
        RECT 216.99 2395.43 739.5 2395.77 ;
        RECT 216.99 2511.91 739.5 2512.25 ;
        RECT 216.99 2628.39 739.5 2628.73 ;
        RECT 216.99 2744.87 739.5 2745.21 ;
        RECT 216.99 2861.35 739.5 2861.69 ;
        RECT 216.99 2977.83 739.5 2978.17 ;
        RECT 216.99 3094.31 739.5 3094.65 ;
        RECT 216.99 3210.79 739.5 3211.13 ;
        RECT 216.99 3327.27 739.5 3327.61 ;
    END
    PORT
      LAYER met3 ;
        RECT 216.99 1691.99 739.5 1692.33 ;
    END
    PORT
      LAYER met3 ;
        RECT 216.99 1652.87 739.5 1653.21 ;
    END
    PORT
      LAYER met3 ;
        RECT 216.99 1660.15 739.5 1660.49 ;
    END
    PORT
      LAYER met3 ;
        RECT 216.99 1655.59 739.5 1655.93 ;
    END
    PORT
      LAYER met3 ;
        RECT 216.99 1662.87 739.5 1663.21 ;
    END
    PORT
      LAYER met3 ;
        RECT 216.99 1667.43 739.5 1667.77 ;
    END
    PORT
      LAYER met3 ;
        RECT 216.99 1674.71 739.5 1675.05 ;
    END
    PORT
      LAYER met3 ;
        RECT 216.99 1670.15 739.5 1670.49 ;
    END
    PORT
      LAYER met3 ;
        RECT 216.99 1677.43 739.5 1677.77 ;
    END
    PORT
      LAYER met3 ;
        RECT 216.99 1684.71 739.5 1685.05 ;
    END
    PORT
      LAYER met3 ;
        RECT 216.99 1689.27 739.5 1689.61 ;
    END
    PORT
      LAYER met3 ;
        RECT 216.99 1681.99 739.5 1682.33 ;
    END
    PORT
      LAYER met3 ;
        RECT 216.99 1609.19 739.5 1609.53 ;
    END
    PORT
      LAYER met3 ;
        RECT 216.99 1616.47 739.5 1616.81 ;
    END
    PORT
      LAYER met3 ;
        RECT 216.99 1611.91 739.5 1612.25 ;
    END
    PORT
      LAYER met3 ;
        RECT 216.99 1619.19 739.5 1619.53 ;
    END
    PORT
      LAYER met3 ;
        RECT 216.99 1623.75 739.5 1624.09 ;
    END
    PORT
      LAYER met3 ;
        RECT 216.99 1631.03 739.5 1631.37 ;
    END
    PORT
      LAYER met3 ;
        RECT 216.99 1626.47 739.5 1626.81 ;
    END
    PORT
      LAYER met3 ;
        RECT 216.99 1633.75 739.5 1634.09 ;
    END
    PORT
      LAYER met3 ;
        RECT 216.99 1638.31 739.5 1638.65 ;
    END
    PORT
      LAYER met3 ;
        RECT 216.99 1645.59 739.5 1645.93 ;
    END
    PORT
      LAYER met3 ;
        RECT 216.99 1641.03 739.5 1641.37 ;
    END
    PORT
      LAYER met3 ;
        RECT 216.99 1648.31 739.5 1648.65 ;
    END
    PORT
      LAYER met3 ;
        RECT 216.99 1580.07 739.5 1580.41 ;
    END
    PORT
      LAYER met3 ;
        RECT 216.99 1587.35 739.5 1587.69 ;
    END
    PORT
      LAYER met3 ;
        RECT 216.99 1582.79 739.5 1583.13 ;
    END
    PORT
      LAYER met3 ;
        RECT 216.99 1590.07 739.5 1590.41 ;
    END
    PORT
      LAYER met3 ;
        RECT 216.99 1594.63 739.5 1594.97 ;
    END
    PORT
      LAYER met3 ;
        RECT 216.99 1601.91 739.5 1602.25 ;
    END
    PORT
      LAYER met3 ;
        RECT 216.99 1597.35 739.5 1597.69 ;
    END
    PORT
      LAYER met3 ;
        RECT 216.99 1604.63 739.5 1604.97 ;
    END
    PORT
      LAYER met3 ;
        RECT 3114.49 1643.165 3656.935 1643.505 ;
    END
    PORT
      LAYER met3 ;
        RECT 3114.49 1650.445 3656.935 1650.785 ;
    END
    PORT
      LAYER met3 ;
        RECT 3114.49 1657.725 3656.935 1658.065 ;
    END
    PORT
      LAYER met3 ;
        RECT 3114.49 1665.005 3656.935 1665.345 ;
    END
    PORT
      LAYER met3 ;
        RECT 3114.49 1672.285 3656.935 1672.625 ;
    END
    PORT
      LAYER met3 ;
        RECT 3114.49 1686.845 3656.935 1687.185 ;
    END
    PORT
      LAYER met3 ;
        RECT 3114.49 1679.565 3656.935 1679.905 ;
    END
    PORT
      LAYER met3 ;
        RECT 3114.49 1694.125 3656.935 1694.465 ;
    END
    PORT
      LAYER met3 ;
        RECT 3114.49 1577.645 3656.935 1577.985 ;
    END
    PORT
      LAYER met3 ;
        RECT 3114.49 1584.925 3656.935 1585.265 ;
    END
    PORT
      LAYER met3 ;
        RECT 3114.49 1592.205 3656.935 1592.545 ;
    END
    PORT
      LAYER met3 ;
        RECT 3114.49 1599.485 3656.935 1599.825 ;
    END
    PORT
      LAYER met3 ;
        RECT 3114.49 1606.765 3656.935 1607.105 ;
    END
    PORT
      LAYER met3 ;
        RECT 3114.49 1614.045 3656.935 1614.385 ;
    END
    PORT
      LAYER met3 ;
        RECT 3114.49 1621.325 3656.935 1621.665 ;
    END
    PORT
      LAYER met3 ;
        RECT 3114.49 1628.605 3656.935 1628.945 ;
    END
    PORT
      LAYER met3 ;
        RECT 3114.49 1635.885 3656.935 1636.225 ;
    END
  END VDDA1
  PIN VDDC2
    DIRECTION INOUT ;
    USE POWER ;
    PORT
      LAYER met3 ;
        RECT 216.99 1572.01 3656.935 1573.01 ;
    END
    PORT
      LAYER met3 ;
        RECT 216.99 1424.145 3656.935 1425.645 ;
    END
    PORT
      LAYER met3 ;
        RECT 216.99 1426.895 3656.935 1428.395 ;
    END
    PORT
      LAYER met3 ;
        RECT 216.99 1468.13 3656.935 1469.63 ;
    END
    PORT
      LAYER met3 ;
        RECT 216.99 1463.105 3656.935 1464.605 ;
    END
    PORT
      LAYER met3 ;
        RECT 216.99 1398.62 3656.935 1399.62 ;
    END
    PORT
      LAYER met3 ;
        RECT 216.99 1385.695 3656.935 1386.695 ;
    END
    PORT
      LAYER met3 ;
        RECT 216.99 1362.35 3656.935 1363.85 ;
    END
    PORT
      LAYER met3 ;
        RECT 216.99 1460.105 3656.935 1461.605 ;
    END
    PORT
      LAYER met3 ;
        RECT 216.99 1404.27 3656.935 1405.27 ;
    END
    PORT
      LAYER met3 ;
        RECT 216.895 3700.72 3656.84 3701.72 ;
    END
    PORT
      LAYER met3 ;
        RECT 216.895 3698.72 3656.84 3699.72 ;
    END
    PORT
      LAYER met3 ;
        RECT 216.895 3694.72 3656.84 3695.72 ;
    END
    PORT
      LAYER met3 ;
        RECT 216.895 3705.275 3656.84 3706.275 ;
    END
    PORT
      LAYER met3 ;
        RECT 3165.485 1808.325 3656.935 1808.665 ;
        RECT 3165.485 1924.805 3656.935 1925.145 ;
        RECT 3165.485 2041.285 3656.935 2041.625 ;
        RECT 3165.485 2157.765 3656.935 2158.105 ;
        RECT 3165.485 2274.245 3656.935 2274.585 ;
        RECT 3165.485 2390.725 3656.935 2391.065 ;
        RECT 3165.485 2507.205 3656.935 2507.545 ;
        RECT 3165.485 2623.685 3656.935 2624.025 ;
        RECT 3165.485 2740.165 3656.935 2740.505 ;
        RECT 3165.485 2856.645 3656.935 2856.985 ;
        RECT 3165.485 2973.125 3656.935 2973.465 ;
        RECT 3165.485 3089.605 3656.935 3089.945 ;
        RECT 3165.485 3206.085 3656.935 3206.425 ;
        RECT 3165.485 3322.565 3656.935 3322.905 ;
        RECT 3165.485 3439.045 3656.935 3439.385 ;
    END
    PORT
      LAYER met3 ;
        RECT 3165.485 1805.605 3656.935 1805.945 ;
        RECT 3165.485 1922.085 3656.935 1922.425 ;
        RECT 3165.485 2038.565 3656.935 2038.905 ;
        RECT 3165.485 2155.045 3656.935 2155.385 ;
        RECT 3165.485 2271.525 3656.935 2271.865 ;
        RECT 3165.485 2388.005 3656.935 2388.345 ;
        RECT 3165.485 2504.485 3656.935 2504.825 ;
        RECT 3165.485 2620.965 3656.935 2621.305 ;
        RECT 3165.485 2737.445 3656.935 2737.785 ;
        RECT 3165.485 2853.925 3656.935 2854.265 ;
        RECT 3165.485 2970.405 3656.935 2970.745 ;
        RECT 3165.485 3086.885 3656.935 3087.225 ;
        RECT 3165.485 3203.365 3656.935 3203.705 ;
        RECT 3165.485 3319.845 3656.935 3320.185 ;
        RECT 3165.485 3436.325 3656.935 3436.665 ;
    END
    PORT
      LAYER met3 ;
        RECT 3165.485 1801.045 3656.935 1801.385 ;
        RECT 3165.485 1917.525 3656.935 1917.865 ;
        RECT 3165.485 2034.005 3656.935 2034.345 ;
        RECT 3165.485 2150.485 3656.935 2150.825 ;
        RECT 3165.485 2266.965 3656.935 2267.305 ;
        RECT 3165.485 2383.445 3656.935 2383.785 ;
        RECT 3165.485 2499.925 3656.935 2500.265 ;
        RECT 3165.485 2616.405 3656.935 2616.745 ;
        RECT 3165.485 2732.885 3656.935 2733.225 ;
        RECT 3165.485 2849.365 3656.935 2849.705 ;
        RECT 3165.485 2965.845 3656.935 2966.185 ;
        RECT 3165.485 3082.325 3656.935 3082.665 ;
        RECT 3165.485 3198.805 3656.935 3199.145 ;
        RECT 3165.485 3315.285 3656.935 3315.625 ;
        RECT 3165.485 3431.765 3656.935 3432.105 ;
    END
    PORT
      LAYER met3 ;
        RECT 3165.485 1798.325 3656.935 1798.665 ;
        RECT 3165.485 1914.805 3656.935 1915.145 ;
        RECT 3165.485 2031.285 3656.935 2031.625 ;
        RECT 3165.485 2147.765 3656.935 2148.105 ;
        RECT 3165.485 2264.245 3656.935 2264.585 ;
        RECT 3165.485 2380.725 3656.935 2381.065 ;
        RECT 3165.485 2497.205 3656.935 2497.545 ;
        RECT 3165.485 2613.685 3656.935 2614.025 ;
        RECT 3165.485 2730.165 3656.935 2730.505 ;
        RECT 3165.485 2846.645 3656.935 2846.985 ;
        RECT 3165.485 2963.125 3656.935 2963.465 ;
        RECT 3165.485 3079.605 3656.935 3079.945 ;
        RECT 3165.485 3196.085 3656.935 3196.425 ;
        RECT 3165.485 3312.565 3656.935 3312.905 ;
        RECT 3165.485 3429.045 3656.935 3429.385 ;
    END
    PORT
      LAYER met3 ;
        RECT 3165.485 1793.765 3656.935 1794.105 ;
        RECT 3165.485 1910.245 3656.935 1910.585 ;
        RECT 3165.485 2026.725 3656.935 2027.065 ;
        RECT 3165.485 2143.205 3656.935 2143.545 ;
        RECT 3165.485 2259.685 3656.935 2260.025 ;
        RECT 3165.485 2376.165 3656.935 2376.505 ;
        RECT 3165.485 2492.645 3656.935 2492.985 ;
        RECT 3165.485 2609.125 3656.935 2609.465 ;
        RECT 3165.485 2725.605 3656.935 2725.945 ;
        RECT 3165.485 2842.085 3656.935 2842.425 ;
        RECT 3165.485 2958.565 3656.935 2958.905 ;
        RECT 3165.485 3075.045 3656.935 3075.385 ;
        RECT 3165.485 3191.525 3656.935 3191.865 ;
        RECT 3165.485 3308.005 3656.935 3308.345 ;
        RECT 3165.485 3424.485 3656.935 3424.825 ;
    END
    PORT
      LAYER met3 ;
        RECT 3165.485 1791.045 3656.935 1791.385 ;
        RECT 3165.485 1907.525 3656.935 1907.865 ;
        RECT 3165.485 2024.005 3656.935 2024.345 ;
        RECT 3165.485 2140.485 3656.935 2140.825 ;
        RECT 3165.485 2256.965 3656.935 2257.305 ;
        RECT 3165.485 2373.445 3656.935 2373.785 ;
        RECT 3165.485 2489.925 3656.935 2490.265 ;
        RECT 3165.485 2606.405 3656.935 2606.745 ;
        RECT 3165.485 2722.885 3656.935 2723.225 ;
        RECT 3165.485 2839.365 3656.935 2839.705 ;
        RECT 3165.485 2955.845 3656.935 2956.185 ;
        RECT 3165.485 3072.325 3656.935 3072.665 ;
        RECT 3165.485 3188.805 3656.935 3189.145 ;
        RECT 3165.485 3305.285 3656.935 3305.625 ;
        RECT 3165.485 3421.765 3656.935 3422.105 ;
    END
    PORT
      LAYER met3 ;
        RECT 3165.485 1786.485 3656.935 1786.825 ;
        RECT 3165.485 1902.965 3656.935 1903.305 ;
        RECT 3165.485 2019.445 3656.935 2019.785 ;
        RECT 3165.485 2135.925 3656.935 2136.265 ;
        RECT 3165.485 2252.405 3656.935 2252.745 ;
        RECT 3165.485 2368.885 3656.935 2369.225 ;
        RECT 3165.485 2485.365 3656.935 2485.705 ;
        RECT 3165.485 2601.845 3656.935 2602.185 ;
        RECT 3165.485 2718.325 3656.935 2718.665 ;
        RECT 3165.485 2834.805 3656.935 2835.145 ;
        RECT 3165.485 2951.285 3656.935 2951.625 ;
        RECT 3165.485 3067.765 3656.935 3068.105 ;
        RECT 3165.485 3184.245 3656.935 3184.585 ;
        RECT 3165.485 3300.725 3656.935 3301.065 ;
        RECT 3165.485 3417.205 3656.935 3417.545 ;
    END
    PORT
      LAYER met3 ;
        RECT 3165.485 1783.765 3656.935 1784.105 ;
        RECT 3165.485 1900.245 3656.935 1900.585 ;
        RECT 3165.485 2016.725 3656.935 2017.065 ;
        RECT 3165.485 2133.205 3656.935 2133.545 ;
        RECT 3165.485 2249.685 3656.935 2250.025 ;
        RECT 3165.485 2366.165 3656.935 2366.505 ;
        RECT 3165.485 2482.645 3656.935 2482.985 ;
        RECT 3165.485 2599.125 3656.935 2599.465 ;
        RECT 3165.485 2715.605 3656.935 2715.945 ;
        RECT 3165.485 2832.085 3656.935 2832.425 ;
        RECT 3165.485 2948.565 3656.935 2948.905 ;
        RECT 3165.485 3065.045 3656.935 3065.385 ;
        RECT 3165.485 3181.525 3656.935 3181.865 ;
        RECT 3165.485 3298.005 3656.935 3298.345 ;
        RECT 3165.485 3414.485 3656.935 3414.825 ;
    END
    PORT
      LAYER met3 ;
        RECT 3165.485 1779.205 3656.935 1779.545 ;
        RECT 3165.485 1895.685 3656.935 1896.025 ;
        RECT 3165.485 2012.165 3656.935 2012.505 ;
        RECT 3165.485 2128.645 3656.935 2128.985 ;
        RECT 3165.485 2245.125 3656.935 2245.465 ;
        RECT 3165.485 2361.605 3656.935 2361.945 ;
        RECT 3165.485 2478.085 3656.935 2478.425 ;
        RECT 3165.485 2594.565 3656.935 2594.905 ;
        RECT 3165.485 2711.045 3656.935 2711.385 ;
        RECT 3165.485 2827.525 3656.935 2827.865 ;
        RECT 3165.485 2944.005 3656.935 2944.345 ;
        RECT 3165.485 3060.485 3656.935 3060.825 ;
        RECT 3165.485 3176.965 3656.935 3177.305 ;
        RECT 3165.485 3293.445 3656.935 3293.785 ;
        RECT 3165.485 3409.925 3656.935 3410.265 ;
    END
    PORT
      LAYER met3 ;
        RECT 3165.485 1776.485 3656.935 1776.825 ;
        RECT 3165.485 1892.965 3656.935 1893.305 ;
        RECT 3165.485 2009.445 3656.935 2009.785 ;
        RECT 3165.485 2125.925 3656.935 2126.265 ;
        RECT 3165.485 2242.405 3656.935 2242.745 ;
        RECT 3165.485 2358.885 3656.935 2359.225 ;
        RECT 3165.485 2475.365 3656.935 2475.705 ;
        RECT 3165.485 2591.845 3656.935 2592.185 ;
        RECT 3165.485 2708.325 3656.935 2708.665 ;
        RECT 3165.485 2824.805 3656.935 2825.145 ;
        RECT 3165.485 2941.285 3656.935 2941.625 ;
        RECT 3165.485 3057.765 3656.935 3058.105 ;
        RECT 3165.485 3174.245 3656.935 3174.585 ;
        RECT 3165.485 3290.725 3656.935 3291.065 ;
        RECT 3165.485 3407.205 3656.935 3407.545 ;
    END
    PORT
      LAYER met3 ;
        RECT 3165.485 1771.925 3656.935 1772.265 ;
        RECT 3165.485 1888.405 3656.935 1888.745 ;
        RECT 3165.485 2004.885 3656.935 2005.225 ;
        RECT 3165.485 2121.365 3656.935 2121.705 ;
        RECT 3165.485 2237.845 3656.935 2238.185 ;
        RECT 3165.485 2354.325 3656.935 2354.665 ;
        RECT 3165.485 2470.805 3656.935 2471.145 ;
        RECT 3165.485 2587.285 3656.935 2587.625 ;
        RECT 3165.485 2703.765 3656.935 2704.105 ;
        RECT 3165.485 2820.245 3656.935 2820.585 ;
        RECT 3165.485 2936.725 3656.935 2937.065 ;
        RECT 3165.485 3053.205 3656.935 3053.545 ;
        RECT 3165.485 3169.685 3656.935 3170.025 ;
        RECT 3165.485 3286.165 3656.935 3286.505 ;
        RECT 3165.485 3402.645 3656.935 3402.985 ;
    END
    PORT
      LAYER met3 ;
        RECT 3165.485 1769.205 3656.935 1769.545 ;
        RECT 3165.485 1885.685 3656.935 1886.025 ;
        RECT 3165.485 2002.165 3656.935 2002.505 ;
        RECT 3165.485 2118.645 3656.935 2118.985 ;
        RECT 3165.485 2235.125 3656.935 2235.465 ;
        RECT 3165.485 2351.605 3656.935 2351.945 ;
        RECT 3165.485 2468.085 3656.935 2468.425 ;
        RECT 3165.485 2584.565 3656.935 2584.905 ;
        RECT 3165.485 2701.045 3656.935 2701.385 ;
        RECT 3165.485 2817.525 3656.935 2817.865 ;
        RECT 3165.485 2934.005 3656.935 2934.345 ;
        RECT 3165.485 3050.485 3656.935 3050.825 ;
        RECT 3165.485 3166.965 3656.935 3167.305 ;
        RECT 3165.485 3283.445 3656.935 3283.785 ;
        RECT 3165.485 3399.925 3656.935 3400.265 ;
    END
    PORT
      LAYER met3 ;
        RECT 3165.485 1764.645 3656.935 1764.985 ;
        RECT 3165.485 1881.125 3656.935 1881.465 ;
        RECT 3165.485 1997.605 3656.935 1997.945 ;
        RECT 3165.485 2114.085 3656.935 2114.425 ;
        RECT 3165.485 2230.565 3656.935 2230.905 ;
        RECT 3165.485 2347.045 3656.935 2347.385 ;
        RECT 3165.485 2463.525 3656.935 2463.865 ;
        RECT 3165.485 2580.005 3656.935 2580.345 ;
        RECT 3165.485 2696.485 3656.935 2696.825 ;
        RECT 3165.485 2812.965 3656.935 2813.305 ;
        RECT 3165.485 2929.445 3656.935 2929.785 ;
        RECT 3165.485 3045.925 3656.935 3046.265 ;
        RECT 3165.485 3162.405 3656.935 3162.745 ;
        RECT 3165.485 3278.885 3656.935 3279.225 ;
        RECT 3165.485 3395.365 3656.935 3395.705 ;
    END
    PORT
      LAYER met3 ;
        RECT 3165.485 1761.925 3656.935 1762.265 ;
        RECT 3165.485 1878.405 3656.935 1878.745 ;
        RECT 3165.485 1994.885 3656.935 1995.225 ;
        RECT 3165.485 2111.365 3656.935 2111.705 ;
        RECT 3165.485 2227.845 3656.935 2228.185 ;
        RECT 3165.485 2344.325 3656.935 2344.665 ;
        RECT 3165.485 2460.805 3656.935 2461.145 ;
        RECT 3165.485 2577.285 3656.935 2577.625 ;
        RECT 3165.485 2693.765 3656.935 2694.105 ;
        RECT 3165.485 2810.245 3656.935 2810.585 ;
        RECT 3165.485 2926.725 3656.935 2927.065 ;
        RECT 3165.485 3043.205 3656.935 3043.545 ;
        RECT 3165.485 3159.685 3656.935 3160.025 ;
        RECT 3165.485 3276.165 3656.935 3276.505 ;
        RECT 3165.485 3392.645 3656.935 3392.985 ;
    END
    PORT
      LAYER met3 ;
        RECT 3165.485 1757.365 3656.935 1757.705 ;
        RECT 3165.485 1873.845 3656.935 1874.185 ;
        RECT 3165.485 1990.325 3656.935 1990.665 ;
        RECT 3165.485 2106.805 3656.935 2107.145 ;
        RECT 3165.485 2223.285 3656.935 2223.625 ;
        RECT 3165.485 2339.765 3656.935 2340.105 ;
        RECT 3165.485 2456.245 3656.935 2456.585 ;
        RECT 3165.485 2572.725 3656.935 2573.065 ;
        RECT 3165.485 2689.205 3656.935 2689.545 ;
        RECT 3165.485 2805.685 3656.935 2806.025 ;
        RECT 3165.485 2922.165 3656.935 2922.505 ;
        RECT 3165.485 3038.645 3656.935 3038.985 ;
        RECT 3165.485 3155.125 3656.935 3155.465 ;
        RECT 3165.485 3271.605 3656.935 3271.945 ;
        RECT 3165.485 3388.085 3656.935 3388.425 ;
    END
    PORT
      LAYER met3 ;
        RECT 3165.485 1754.645 3656.935 1754.985 ;
        RECT 3165.485 1871.125 3656.935 1871.465 ;
        RECT 3165.485 1987.605 3656.935 1987.945 ;
        RECT 3165.485 2104.085 3656.935 2104.425 ;
        RECT 3165.485 2220.565 3656.935 2220.905 ;
        RECT 3165.485 2337.045 3656.935 2337.385 ;
        RECT 3165.485 2453.525 3656.935 2453.865 ;
        RECT 3165.485 2570.005 3656.935 2570.345 ;
        RECT 3165.485 2686.485 3656.935 2686.825 ;
        RECT 3165.485 2802.965 3656.935 2803.305 ;
        RECT 3165.485 2919.445 3656.935 2919.785 ;
        RECT 3165.485 3035.925 3656.935 3036.265 ;
        RECT 3165.485 3152.405 3656.935 3152.745 ;
        RECT 3165.485 3268.885 3656.935 3269.225 ;
        RECT 3165.485 3385.365 3656.935 3385.705 ;
    END
    PORT
      LAYER met3 ;
        RECT 3165.485 1750.085 3656.935 1750.425 ;
        RECT 3165.485 1866.565 3656.935 1866.905 ;
        RECT 3165.485 1983.045 3656.935 1983.385 ;
        RECT 3165.485 2099.525 3656.935 2099.865 ;
        RECT 3165.485 2216.005 3656.935 2216.345 ;
        RECT 3165.485 2332.485 3656.935 2332.825 ;
        RECT 3165.485 2448.965 3656.935 2449.305 ;
        RECT 3165.485 2565.445 3656.935 2565.785 ;
        RECT 3165.485 2681.925 3656.935 2682.265 ;
        RECT 3165.485 2798.405 3656.935 2798.745 ;
        RECT 3165.485 2914.885 3656.935 2915.225 ;
        RECT 3165.485 3031.365 3656.935 3031.705 ;
        RECT 3165.485 3147.845 3656.935 3148.185 ;
        RECT 3165.485 3264.325 3656.935 3264.665 ;
        RECT 3165.485 3380.805 3656.935 3381.145 ;
    END
    PORT
      LAYER met3 ;
        RECT 3165.485 1747.365 3656.935 1747.705 ;
        RECT 3165.485 1863.845 3656.935 1864.185 ;
        RECT 3165.485 1980.325 3656.935 1980.665 ;
        RECT 3165.485 2096.805 3656.935 2097.145 ;
        RECT 3165.485 2213.285 3656.935 2213.625 ;
        RECT 3165.485 2329.765 3656.935 2330.105 ;
        RECT 3165.485 2446.245 3656.935 2446.585 ;
        RECT 3165.485 2562.725 3656.935 2563.065 ;
        RECT 3165.485 2679.205 3656.935 2679.545 ;
        RECT 3165.485 2795.685 3656.935 2796.025 ;
        RECT 3165.485 2912.165 3656.935 2912.505 ;
        RECT 3165.485 3028.645 3656.935 3028.985 ;
        RECT 3165.485 3145.125 3656.935 3145.465 ;
        RECT 3165.485 3261.605 3656.935 3261.945 ;
        RECT 3165.485 3378.085 3656.935 3378.425 ;
    END
    PORT
      LAYER met3 ;
        RECT 3165.485 1742.805 3656.935 1743.145 ;
        RECT 3165.485 1859.285 3656.935 1859.625 ;
        RECT 3165.485 1975.765 3656.935 1976.105 ;
        RECT 3165.485 2092.245 3656.935 2092.585 ;
        RECT 3165.485 2208.725 3656.935 2209.065 ;
        RECT 3165.485 2325.205 3656.935 2325.545 ;
        RECT 3165.485 2441.685 3656.935 2442.025 ;
        RECT 3165.485 2558.165 3656.935 2558.505 ;
        RECT 3165.485 2674.645 3656.935 2674.985 ;
        RECT 3165.485 2791.125 3656.935 2791.465 ;
        RECT 3165.485 2907.605 3656.935 2907.945 ;
        RECT 3165.485 3024.085 3656.935 3024.425 ;
        RECT 3165.485 3140.565 3656.935 3140.905 ;
        RECT 3165.485 3257.045 3656.935 3257.385 ;
        RECT 3165.485 3373.525 3656.935 3373.865 ;
    END
    PORT
      LAYER met3 ;
        RECT 3165.485 1740.085 3656.935 1740.425 ;
        RECT 3165.485 1856.565 3656.935 1856.905 ;
        RECT 3165.485 1973.045 3656.935 1973.385 ;
        RECT 3165.485 2089.525 3656.935 2089.865 ;
        RECT 3165.485 2206.005 3656.935 2206.345 ;
        RECT 3165.485 2322.485 3656.935 2322.825 ;
        RECT 3165.485 2438.965 3656.935 2439.305 ;
        RECT 3165.485 2555.445 3656.935 2555.785 ;
        RECT 3165.485 2671.925 3656.935 2672.265 ;
        RECT 3165.485 2788.405 3656.935 2788.745 ;
        RECT 3165.485 2904.885 3656.935 2905.225 ;
        RECT 3165.485 3021.365 3656.935 3021.705 ;
        RECT 3165.485 3137.845 3656.935 3138.185 ;
        RECT 3165.485 3254.325 3656.935 3254.665 ;
        RECT 3165.485 3370.805 3656.935 3371.145 ;
    END
    PORT
      LAYER met3 ;
        RECT 3165.485 1735.525 3656.935 1735.865 ;
        RECT 3165.485 1852.005 3656.935 1852.345 ;
        RECT 3165.485 1968.485 3656.935 1968.825 ;
        RECT 3165.485 2084.965 3656.935 2085.305 ;
        RECT 3165.485 2201.445 3656.935 2201.785 ;
        RECT 3165.485 2317.925 3656.935 2318.265 ;
        RECT 3165.485 2434.405 3656.935 2434.745 ;
        RECT 3165.485 2550.885 3656.935 2551.225 ;
        RECT 3165.485 2667.365 3656.935 2667.705 ;
        RECT 3165.485 2783.845 3656.935 2784.185 ;
        RECT 3165.485 2900.325 3656.935 2900.665 ;
        RECT 3165.485 3016.805 3656.935 3017.145 ;
        RECT 3165.485 3133.285 3656.935 3133.625 ;
        RECT 3165.485 3249.765 3656.935 3250.105 ;
        RECT 3165.485 3366.245 3656.935 3366.585 ;
    END
    PORT
      LAYER met3 ;
        RECT 3165.485 1732.805 3656.935 1733.145 ;
        RECT 3165.485 1849.285 3656.935 1849.625 ;
        RECT 3165.485 1965.765 3656.935 1966.105 ;
        RECT 3165.485 2082.245 3656.935 2082.585 ;
        RECT 3165.485 2198.725 3656.935 2199.065 ;
        RECT 3165.485 2315.205 3656.935 2315.545 ;
        RECT 3165.485 2431.685 3656.935 2432.025 ;
        RECT 3165.485 2548.165 3656.935 2548.505 ;
        RECT 3165.485 2664.645 3656.935 2664.985 ;
        RECT 3165.485 2781.125 3656.935 2781.465 ;
        RECT 3165.485 2897.605 3656.935 2897.945 ;
        RECT 3165.485 3014.085 3656.935 3014.425 ;
        RECT 3165.485 3130.565 3656.935 3130.905 ;
        RECT 3165.485 3247.045 3656.935 3247.385 ;
        RECT 3165.485 3363.525 3656.935 3363.865 ;
    END
    PORT
      LAYER met3 ;
        RECT 3165.485 1728.245 3656.935 1728.585 ;
        RECT 3165.485 1844.725 3656.935 1845.065 ;
        RECT 3165.485 1961.205 3656.935 1961.545 ;
        RECT 3165.485 2077.685 3656.935 2078.025 ;
        RECT 3165.485 2194.165 3656.935 2194.505 ;
        RECT 3165.485 2310.645 3656.935 2310.985 ;
        RECT 3165.485 2427.125 3656.935 2427.465 ;
        RECT 3165.485 2543.605 3656.935 2543.945 ;
        RECT 3165.485 2660.085 3656.935 2660.425 ;
        RECT 3165.485 2776.565 3656.935 2776.905 ;
        RECT 3165.485 2893.045 3656.935 2893.385 ;
        RECT 3165.485 3009.525 3656.935 3009.865 ;
        RECT 3165.485 3126.005 3656.935 3126.345 ;
        RECT 3165.485 3242.485 3656.935 3242.825 ;
        RECT 3165.485 3358.965 3656.935 3359.305 ;
    END
    PORT
      LAYER met3 ;
        RECT 3165.485 1725.525 3656.935 1725.865 ;
        RECT 3165.485 1842.005 3656.935 1842.345 ;
        RECT 3165.485 1958.485 3656.935 1958.825 ;
        RECT 3165.485 2074.965 3656.935 2075.305 ;
        RECT 3165.485 2191.445 3656.935 2191.785 ;
        RECT 3165.485 2307.925 3656.935 2308.265 ;
        RECT 3165.485 2424.405 3656.935 2424.745 ;
        RECT 3165.485 2540.885 3656.935 2541.225 ;
        RECT 3165.485 2657.365 3656.935 2657.705 ;
        RECT 3165.485 2773.845 3656.935 2774.185 ;
        RECT 3165.485 2890.325 3656.935 2890.665 ;
        RECT 3165.485 3006.805 3656.935 3007.145 ;
        RECT 3165.485 3123.285 3656.935 3123.625 ;
        RECT 3165.485 3239.765 3656.935 3240.105 ;
        RECT 3165.485 3356.245 3656.935 3356.585 ;
    END
    PORT
      LAYER met3 ;
        RECT 3165.485 1720.965 3656.935 1721.305 ;
        RECT 3165.485 1837.445 3656.935 1837.785 ;
        RECT 3165.485 1953.925 3656.935 1954.265 ;
        RECT 3165.485 2070.405 3656.935 2070.745 ;
        RECT 3165.485 2186.885 3656.935 2187.225 ;
        RECT 3165.485 2303.365 3656.935 2303.705 ;
        RECT 3165.485 2419.845 3656.935 2420.185 ;
        RECT 3165.485 2536.325 3656.935 2536.665 ;
        RECT 3165.485 2652.805 3656.935 2653.145 ;
        RECT 3165.485 2769.285 3656.935 2769.625 ;
        RECT 3165.485 2885.765 3656.935 2886.105 ;
        RECT 3165.485 3002.245 3656.935 3002.585 ;
        RECT 3165.485 3118.725 3656.935 3119.065 ;
        RECT 3165.485 3235.205 3656.935 3235.545 ;
        RECT 3165.485 3351.685 3656.935 3352.025 ;
    END
    PORT
      LAYER met3 ;
        RECT 3165.485 1718.245 3656.935 1718.585 ;
        RECT 3165.485 1834.725 3656.935 1835.065 ;
        RECT 3165.485 1951.205 3656.935 1951.545 ;
        RECT 3165.485 2067.685 3656.935 2068.025 ;
        RECT 3165.485 2184.165 3656.935 2184.505 ;
        RECT 3165.485 2300.645 3656.935 2300.985 ;
        RECT 3165.485 2417.125 3656.935 2417.465 ;
        RECT 3165.485 2533.605 3656.935 2533.945 ;
        RECT 3165.485 2650.085 3656.935 2650.425 ;
        RECT 3165.485 2766.565 3656.935 2766.905 ;
        RECT 3165.485 2883.045 3656.935 2883.385 ;
        RECT 3165.485 2999.525 3656.935 2999.865 ;
        RECT 3165.485 3116.005 3656.935 3116.345 ;
        RECT 3165.485 3232.485 3656.935 3232.825 ;
        RECT 3165.485 3348.965 3656.935 3349.305 ;
    END
    PORT
      LAYER met3 ;
        RECT 3165.485 1713.685 3656.935 1714.025 ;
        RECT 3165.485 1830.165 3656.935 1830.505 ;
        RECT 3165.485 1946.645 3656.935 1946.985 ;
        RECT 3165.485 2063.125 3656.935 2063.465 ;
        RECT 3165.485 2179.605 3656.935 2179.945 ;
        RECT 3165.485 2296.085 3656.935 2296.425 ;
        RECT 3165.485 2412.565 3656.935 2412.905 ;
        RECT 3165.485 2529.045 3656.935 2529.385 ;
        RECT 3165.485 2645.525 3656.935 2645.865 ;
        RECT 3165.485 2762.005 3656.935 2762.345 ;
        RECT 3165.485 2878.485 3656.935 2878.825 ;
        RECT 3165.485 2994.965 3656.935 2995.305 ;
        RECT 3165.485 3111.445 3656.935 3111.785 ;
        RECT 3165.485 3227.925 3656.935 3228.265 ;
        RECT 3165.485 3344.405 3656.935 3344.745 ;
    END
    PORT
      LAYER met3 ;
        RECT 3165.485 1710.965 3656.935 1711.305 ;
        RECT 3165.485 1827.445 3656.935 1827.785 ;
        RECT 3165.485 1943.925 3656.935 1944.265 ;
        RECT 3165.485 2060.405 3656.935 2060.745 ;
        RECT 3165.485 2176.885 3656.935 2177.225 ;
        RECT 3165.485 2293.365 3656.935 2293.705 ;
        RECT 3165.485 2409.845 3656.935 2410.185 ;
        RECT 3165.485 2526.325 3656.935 2526.665 ;
        RECT 3165.485 2642.805 3656.935 2643.145 ;
        RECT 3165.485 2759.285 3656.935 2759.625 ;
        RECT 3165.485 2875.765 3656.935 2876.105 ;
        RECT 3165.485 2992.245 3656.935 2992.585 ;
        RECT 3165.485 3108.725 3656.935 3109.065 ;
        RECT 3165.485 3225.205 3656.935 3225.545 ;
        RECT 3165.485 3341.685 3656.935 3342.025 ;
    END
    PORT
      LAYER met3 ;
        RECT 3165.485 1706.405 3656.935 1706.745 ;
        RECT 3165.485 1822.885 3656.935 1823.225 ;
        RECT 3165.485 1939.365 3656.935 1939.705 ;
        RECT 3165.485 2055.845 3656.935 2056.185 ;
        RECT 3165.485 2172.325 3656.935 2172.665 ;
        RECT 3165.485 2288.805 3656.935 2289.145 ;
        RECT 3165.485 2405.285 3656.935 2405.625 ;
        RECT 3165.485 2521.765 3656.935 2522.105 ;
        RECT 3165.485 2638.245 3656.935 2638.585 ;
        RECT 3165.485 2754.725 3656.935 2755.065 ;
        RECT 3165.485 2871.205 3656.935 2871.545 ;
        RECT 3165.485 2987.685 3656.935 2988.025 ;
        RECT 3165.485 3104.165 3656.935 3104.505 ;
        RECT 3165.485 3220.645 3656.935 3220.985 ;
        RECT 3165.485 3337.125 3656.935 3337.465 ;
    END
    PORT
      LAYER met3 ;
        RECT 3165.485 1703.685 3656.935 1704.025 ;
        RECT 3165.485 1820.165 3656.935 1820.505 ;
        RECT 3165.485 1936.645 3656.935 1936.985 ;
        RECT 3165.485 2053.125 3656.935 2053.465 ;
        RECT 3165.485 2169.605 3656.935 2169.945 ;
        RECT 3165.485 2286.085 3656.935 2286.425 ;
        RECT 3165.485 2402.565 3656.935 2402.905 ;
        RECT 3165.485 2519.045 3656.935 2519.385 ;
        RECT 3165.485 2635.525 3656.935 2635.865 ;
        RECT 3165.485 2752.005 3656.935 2752.345 ;
        RECT 3165.485 2868.485 3656.935 2868.825 ;
        RECT 3165.485 2984.965 3656.935 2985.305 ;
        RECT 3165.485 3101.445 3656.935 3101.785 ;
        RECT 3165.485 3217.925 3656.935 3218.265 ;
        RECT 3165.485 3334.405 3656.935 3334.745 ;
    END
    PORT
      LAYER met3 ;
        RECT 3165.485 1699.125 3656.935 1699.465 ;
        RECT 3165.485 1815.605 3656.935 1815.945 ;
        RECT 3165.485 1932.085 3656.935 1932.425 ;
        RECT 3165.485 2048.565 3656.935 2048.905 ;
        RECT 3165.485 2165.045 3656.935 2165.385 ;
        RECT 3165.485 2281.525 3656.935 2281.865 ;
        RECT 3165.485 2398.005 3656.935 2398.345 ;
        RECT 3165.485 2514.485 3656.935 2514.825 ;
        RECT 3165.485 2630.965 3656.935 2631.305 ;
        RECT 3165.485 2747.445 3656.935 2747.785 ;
        RECT 3165.485 2863.925 3656.935 2864.265 ;
        RECT 3165.485 2980.405 3656.935 2980.745 ;
        RECT 3165.485 3096.885 3656.935 3097.225 ;
        RECT 3165.485 3213.365 3656.935 3213.705 ;
        RECT 3165.485 3329.845 3656.935 3330.185 ;
    END
    PORT
      LAYER met3 ;
        RECT 3165.485 1696.405 3656.935 1696.745 ;
        RECT 3165.485 1812.885 3656.935 1813.225 ;
        RECT 3165.485 1929.365 3656.935 1929.705 ;
        RECT 3165.485 2045.845 3656.935 2046.185 ;
        RECT 3165.485 2162.325 3656.935 2162.665 ;
        RECT 3165.485 2278.805 3656.935 2279.145 ;
        RECT 3165.485 2395.285 3656.935 2395.625 ;
        RECT 3165.485 2511.765 3656.935 2512.105 ;
        RECT 3165.485 2628.245 3656.935 2628.585 ;
        RECT 3165.485 2744.725 3656.935 2745.065 ;
        RECT 3165.485 2861.205 3656.935 2861.545 ;
        RECT 3165.485 2977.685 3656.935 2978.025 ;
        RECT 3165.485 3094.165 3656.935 3094.505 ;
        RECT 3165.485 3210.645 3656.935 3210.985 ;
        RECT 3165.485 3327.125 3656.935 3327.465 ;
    END
    PORT
      LAYER met3 ;
        RECT 216.99 1810.11 691.775 1810.45 ;
        RECT 216.99 1926.59 691.775 1926.93 ;
        RECT 216.99 2043.07 691.775 2043.41 ;
        RECT 216.99 2159.55 691.775 2159.89 ;
        RECT 216.99 2276.03 691.775 2276.37 ;
        RECT 216.99 2392.51 691.775 2392.85 ;
        RECT 216.99 2508.99 691.775 2509.33 ;
        RECT 216.99 2625.47 691.775 2625.81 ;
        RECT 216.99 2741.95 691.775 2742.29 ;
        RECT 216.99 2858.43 691.775 2858.77 ;
        RECT 216.99 2974.91 691.775 2975.25 ;
        RECT 216.99 3091.39 691.775 3091.73 ;
        RECT 216.99 3207.87 691.775 3208.21 ;
        RECT 216.99 3324.35 691.775 3324.69 ;
        RECT 216.99 3440.83 691.775 3441.17 ;
    END
    PORT
      LAYER met3 ;
        RECT 216.99 1804.11 691.775 1804.45 ;
        RECT 216.99 1920.59 691.775 1920.93 ;
        RECT 216.99 2037.07 691.775 2037.41 ;
        RECT 216.99 2153.55 691.775 2153.89 ;
        RECT 216.99 2270.03 691.775 2270.37 ;
        RECT 216.99 2386.51 691.775 2386.85 ;
        RECT 216.99 2502.99 691.775 2503.33 ;
        RECT 216.99 2619.47 691.775 2619.81 ;
        RECT 216.99 2735.95 691.775 2736.29 ;
        RECT 216.99 2852.43 691.775 2852.77 ;
        RECT 216.99 2968.91 691.775 2969.25 ;
        RECT 216.99 3085.39 691.775 3085.73 ;
        RECT 216.99 3201.87 691.775 3202.21 ;
        RECT 216.99 3318.35 691.775 3318.69 ;
        RECT 216.99 3434.83 691.775 3435.17 ;
    END
    PORT
      LAYER met3 ;
        RECT 216.99 1802.83 691.775 1803.17 ;
        RECT 216.99 1919.31 691.775 1919.65 ;
        RECT 216.99 2035.79 691.775 2036.13 ;
        RECT 216.99 2152.27 691.775 2152.61 ;
        RECT 216.99 2268.75 691.775 2269.09 ;
        RECT 216.99 2385.23 691.775 2385.57 ;
        RECT 216.99 2501.71 691.775 2502.05 ;
        RECT 216.99 2618.19 691.775 2618.53 ;
        RECT 216.99 2734.67 691.775 2735.01 ;
        RECT 216.99 2851.15 691.775 2851.49 ;
        RECT 216.99 2967.63 691.775 2967.97 ;
        RECT 216.99 3084.11 691.775 3084.45 ;
        RECT 216.99 3200.59 691.775 3200.93 ;
        RECT 216.99 3317.07 691.775 3317.41 ;
        RECT 216.99 3433.55 691.775 3433.89 ;
    END
    PORT
      LAYER met3 ;
        RECT 216.99 1796.83 691.775 1797.17 ;
        RECT 216.99 1913.31 691.775 1913.65 ;
        RECT 216.99 2029.79 691.775 2030.13 ;
        RECT 216.99 2146.27 691.775 2146.61 ;
        RECT 216.99 2262.75 691.775 2263.09 ;
        RECT 216.99 2379.23 691.775 2379.57 ;
        RECT 216.99 2495.71 691.775 2496.05 ;
        RECT 216.99 2612.19 691.775 2612.53 ;
        RECT 216.99 2728.67 691.775 2729.01 ;
        RECT 216.99 2845.15 691.775 2845.49 ;
        RECT 216.99 2961.63 691.775 2961.97 ;
        RECT 216.99 3078.11 691.775 3078.45 ;
        RECT 216.99 3194.59 691.775 3194.93 ;
        RECT 216.99 3311.07 691.775 3311.41 ;
        RECT 216.99 3427.55 691.775 3427.89 ;
    END
    PORT
      LAYER met3 ;
        RECT 216.99 1795.55 691.775 1795.89 ;
        RECT 216.99 1912.03 691.775 1912.37 ;
        RECT 216.99 2028.51 691.775 2028.85 ;
        RECT 216.99 2144.99 691.775 2145.33 ;
        RECT 216.99 2261.47 691.775 2261.81 ;
        RECT 216.99 2377.95 691.775 2378.29 ;
        RECT 216.99 2494.43 691.775 2494.77 ;
        RECT 216.99 2610.91 691.775 2611.25 ;
        RECT 216.99 2727.39 691.775 2727.73 ;
        RECT 216.99 2843.87 691.775 2844.21 ;
        RECT 216.99 2960.35 691.775 2960.69 ;
        RECT 216.99 3076.83 691.775 3077.17 ;
        RECT 216.99 3193.31 691.775 3193.65 ;
        RECT 216.99 3309.79 691.775 3310.13 ;
        RECT 216.99 3426.27 691.775 3426.61 ;
    END
    PORT
      LAYER met3 ;
        RECT 216.99 1789.55 691.775 1789.89 ;
        RECT 216.99 1906.03 691.775 1906.37 ;
        RECT 216.99 2022.51 691.775 2022.85 ;
        RECT 216.99 2138.99 691.775 2139.33 ;
        RECT 216.99 2255.47 691.775 2255.81 ;
        RECT 216.99 2371.95 691.775 2372.29 ;
        RECT 216.99 2488.43 691.775 2488.77 ;
        RECT 216.99 2604.91 691.775 2605.25 ;
        RECT 216.99 2721.39 691.775 2721.73 ;
        RECT 216.99 2837.87 691.775 2838.21 ;
        RECT 216.99 2954.35 691.775 2954.69 ;
        RECT 216.99 3070.83 691.775 3071.17 ;
        RECT 216.99 3187.31 691.775 3187.65 ;
        RECT 216.99 3303.79 691.775 3304.13 ;
        RECT 216.99 3420.27 691.775 3420.61 ;
    END
    PORT
      LAYER met3 ;
        RECT 216.99 1788.27 691.775 1788.61 ;
        RECT 216.99 1904.75 691.775 1905.09 ;
        RECT 216.99 2021.23 691.775 2021.57 ;
        RECT 216.99 2137.71 691.775 2138.05 ;
        RECT 216.99 2254.19 691.775 2254.53 ;
        RECT 216.99 2370.67 691.775 2371.01 ;
        RECT 216.99 2487.15 691.775 2487.49 ;
        RECT 216.99 2603.63 691.775 2603.97 ;
        RECT 216.99 2720.11 691.775 2720.45 ;
        RECT 216.99 2836.59 691.775 2836.93 ;
        RECT 216.99 2953.07 691.775 2953.41 ;
        RECT 216.99 3069.55 691.775 3069.89 ;
        RECT 216.99 3186.03 691.775 3186.37 ;
        RECT 216.99 3302.51 691.775 3302.85 ;
        RECT 216.99 3418.99 691.775 3419.33 ;
    END
    PORT
      LAYER met3 ;
        RECT 216.99 1782.27 691.775 1782.61 ;
        RECT 216.99 1898.75 691.775 1899.09 ;
        RECT 216.99 2015.23 691.775 2015.57 ;
        RECT 216.99 2131.71 691.775 2132.05 ;
        RECT 216.99 2248.19 691.775 2248.53 ;
        RECT 216.99 2364.67 691.775 2365.01 ;
        RECT 216.99 2481.15 691.775 2481.49 ;
        RECT 216.99 2597.63 691.775 2597.97 ;
        RECT 216.99 2714.11 691.775 2714.45 ;
        RECT 216.99 2830.59 691.775 2830.93 ;
        RECT 216.99 2947.07 691.775 2947.41 ;
        RECT 216.99 3063.55 691.775 3063.89 ;
        RECT 216.99 3180.03 691.775 3180.37 ;
        RECT 216.99 3296.51 691.775 3296.85 ;
        RECT 216.99 3412.99 691.775 3413.33 ;
    END
    PORT
      LAYER met3 ;
        RECT 216.99 1780.99 691.775 1781.33 ;
        RECT 216.99 1897.47 691.775 1897.81 ;
        RECT 216.99 2013.95 691.775 2014.29 ;
        RECT 216.99 2130.43 691.775 2130.77 ;
        RECT 216.99 2246.91 691.775 2247.25 ;
        RECT 216.99 2363.39 691.775 2363.73 ;
        RECT 216.99 2479.87 691.775 2480.21 ;
        RECT 216.99 2596.35 691.775 2596.69 ;
        RECT 216.99 2712.83 691.775 2713.17 ;
        RECT 216.99 2829.31 691.775 2829.65 ;
        RECT 216.99 2945.79 691.775 2946.13 ;
        RECT 216.99 3062.27 691.775 3062.61 ;
        RECT 216.99 3178.75 691.775 3179.09 ;
        RECT 216.99 3295.23 691.775 3295.57 ;
        RECT 216.99 3411.71 691.775 3412.05 ;
    END
    PORT
      LAYER met3 ;
        RECT 216.99 1774.99 691.775 1775.33 ;
        RECT 216.99 1891.47 691.775 1891.81 ;
        RECT 216.99 2007.95 691.775 2008.29 ;
        RECT 216.99 2124.43 691.775 2124.77 ;
        RECT 216.99 2240.91 691.775 2241.25 ;
        RECT 216.99 2357.39 691.775 2357.73 ;
        RECT 216.99 2473.87 691.775 2474.21 ;
        RECT 216.99 2590.35 691.775 2590.69 ;
        RECT 216.99 2706.83 691.775 2707.17 ;
        RECT 216.99 2823.31 691.775 2823.65 ;
        RECT 216.99 2939.79 691.775 2940.13 ;
        RECT 216.99 3056.27 691.775 3056.61 ;
        RECT 216.99 3172.75 691.775 3173.09 ;
        RECT 216.99 3289.23 691.775 3289.57 ;
        RECT 216.99 3405.71 691.775 3406.05 ;
    END
    PORT
      LAYER met3 ;
        RECT 216.99 1773.71 691.775 1774.05 ;
        RECT 216.99 1890.19 691.775 1890.53 ;
        RECT 216.99 2006.67 691.775 2007.01 ;
        RECT 216.99 2123.15 691.775 2123.49 ;
        RECT 216.99 2239.63 691.775 2239.97 ;
        RECT 216.99 2356.11 691.775 2356.45 ;
        RECT 216.99 2472.59 691.775 2472.93 ;
        RECT 216.99 2589.07 691.775 2589.41 ;
        RECT 216.99 2705.55 691.775 2705.89 ;
        RECT 216.99 2822.03 691.775 2822.37 ;
        RECT 216.99 2938.51 691.775 2938.85 ;
        RECT 216.99 3054.99 691.775 3055.33 ;
        RECT 216.99 3171.47 691.775 3171.81 ;
        RECT 216.99 3287.95 691.775 3288.29 ;
        RECT 216.99 3404.43 691.775 3404.77 ;
    END
    PORT
      LAYER met3 ;
        RECT 216.99 1767.71 691.775 1768.05 ;
        RECT 216.99 1884.19 691.775 1884.53 ;
        RECT 216.99 2000.67 691.775 2001.01 ;
        RECT 216.99 2117.15 691.775 2117.49 ;
        RECT 216.99 2233.63 691.775 2233.97 ;
        RECT 216.99 2350.11 691.775 2350.45 ;
        RECT 216.99 2466.59 691.775 2466.93 ;
        RECT 216.99 2583.07 691.775 2583.41 ;
        RECT 216.99 2699.55 691.775 2699.89 ;
        RECT 216.99 2816.03 691.775 2816.37 ;
        RECT 216.99 2932.51 691.775 2932.85 ;
        RECT 216.99 3048.99 691.775 3049.33 ;
        RECT 216.99 3165.47 691.775 3165.81 ;
        RECT 216.99 3281.95 691.775 3282.29 ;
        RECT 216.99 3398.43 691.775 3398.77 ;
    END
    PORT
      LAYER met3 ;
        RECT 216.99 1766.43 691.775 1766.77 ;
        RECT 216.99 1882.91 691.775 1883.25 ;
        RECT 216.99 1999.39 691.775 1999.73 ;
        RECT 216.99 2115.87 691.775 2116.21 ;
        RECT 216.99 2232.35 691.775 2232.69 ;
        RECT 216.99 2348.83 691.775 2349.17 ;
        RECT 216.99 2465.31 691.775 2465.65 ;
        RECT 216.99 2581.79 691.775 2582.13 ;
        RECT 216.99 2698.27 691.775 2698.61 ;
        RECT 216.99 2814.75 691.775 2815.09 ;
        RECT 216.99 2931.23 691.775 2931.57 ;
        RECT 216.99 3047.71 691.775 3048.05 ;
        RECT 216.99 3164.19 691.775 3164.53 ;
        RECT 216.99 3280.67 691.775 3281.01 ;
        RECT 216.99 3397.15 691.775 3397.49 ;
    END
    PORT
      LAYER met3 ;
        RECT 216.99 1760.43 691.775 1760.77 ;
        RECT 216.99 1876.91 691.775 1877.25 ;
        RECT 216.99 1993.39 691.775 1993.73 ;
        RECT 216.99 2109.87 691.775 2110.21 ;
        RECT 216.99 2226.35 691.775 2226.69 ;
        RECT 216.99 2342.83 691.775 2343.17 ;
        RECT 216.99 2459.31 691.775 2459.65 ;
        RECT 216.99 2575.79 691.775 2576.13 ;
        RECT 216.99 2692.27 691.775 2692.61 ;
        RECT 216.99 2808.75 691.775 2809.09 ;
        RECT 216.99 2925.23 691.775 2925.57 ;
        RECT 216.99 3041.71 691.775 3042.05 ;
        RECT 216.99 3158.19 691.775 3158.53 ;
        RECT 216.99 3274.67 691.775 3275.01 ;
        RECT 216.99 3391.15 691.775 3391.49 ;
    END
    PORT
      LAYER met3 ;
        RECT 216.99 1759.15 691.775 1759.49 ;
        RECT 216.99 1875.63 691.775 1875.97 ;
        RECT 216.99 1992.11 691.775 1992.45 ;
        RECT 216.99 2108.59 691.775 2108.93 ;
        RECT 216.99 2225.07 691.775 2225.41 ;
        RECT 216.99 2341.55 691.775 2341.89 ;
        RECT 216.99 2458.03 691.775 2458.37 ;
        RECT 216.99 2574.51 691.775 2574.85 ;
        RECT 216.99 2690.99 691.775 2691.33 ;
        RECT 216.99 2807.47 691.775 2807.81 ;
        RECT 216.99 2923.95 691.775 2924.29 ;
        RECT 216.99 3040.43 691.775 3040.77 ;
        RECT 216.99 3156.91 691.775 3157.25 ;
        RECT 216.99 3273.39 691.775 3273.73 ;
        RECT 216.99 3389.87 691.775 3390.21 ;
    END
    PORT
      LAYER met3 ;
        RECT 216.99 1753.15 691.775 1753.49 ;
        RECT 216.99 1869.63 691.775 1869.97 ;
        RECT 216.99 1986.11 691.775 1986.45 ;
        RECT 216.99 2102.59 691.775 2102.93 ;
        RECT 216.99 2219.07 691.775 2219.41 ;
        RECT 216.99 2335.55 691.775 2335.89 ;
        RECT 216.99 2452.03 691.775 2452.37 ;
        RECT 216.99 2568.51 691.775 2568.85 ;
        RECT 216.99 2684.99 691.775 2685.33 ;
        RECT 216.99 2801.47 691.775 2801.81 ;
        RECT 216.99 2917.95 691.775 2918.29 ;
        RECT 216.99 3034.43 691.775 3034.77 ;
        RECT 216.99 3150.91 691.775 3151.25 ;
        RECT 216.99 3267.39 691.775 3267.73 ;
        RECT 216.99 3383.87 691.775 3384.21 ;
    END
    PORT
      LAYER met3 ;
        RECT 216.99 1751.87 691.775 1752.21 ;
        RECT 216.99 1868.35 691.775 1868.69 ;
        RECT 216.99 1984.83 691.775 1985.17 ;
        RECT 216.99 2101.31 691.775 2101.65 ;
        RECT 216.99 2217.79 691.775 2218.13 ;
        RECT 216.99 2334.27 691.775 2334.61 ;
        RECT 216.99 2450.75 691.775 2451.09 ;
        RECT 216.99 2567.23 691.775 2567.57 ;
        RECT 216.99 2683.71 691.775 2684.05 ;
        RECT 216.99 2800.19 691.775 2800.53 ;
        RECT 216.99 2916.67 691.775 2917.01 ;
        RECT 216.99 3033.15 691.775 3033.49 ;
        RECT 216.99 3149.63 691.775 3149.97 ;
        RECT 216.99 3266.11 691.775 3266.45 ;
        RECT 216.99 3382.59 691.775 3382.93 ;
    END
    PORT
      LAYER met3 ;
        RECT 216.99 1745.87 691.775 1746.21 ;
        RECT 216.99 1862.35 691.775 1862.69 ;
        RECT 216.99 1978.83 691.775 1979.17 ;
        RECT 216.99 2095.31 691.775 2095.65 ;
        RECT 216.99 2211.79 691.775 2212.13 ;
        RECT 216.99 2328.27 691.775 2328.61 ;
        RECT 216.99 2444.75 691.775 2445.09 ;
        RECT 216.99 2561.23 691.775 2561.57 ;
        RECT 216.99 2677.71 691.775 2678.05 ;
        RECT 216.99 2794.19 691.775 2794.53 ;
        RECT 216.99 2910.67 691.775 2911.01 ;
        RECT 216.99 3027.15 691.775 3027.49 ;
        RECT 216.99 3143.63 691.775 3143.97 ;
        RECT 216.99 3260.11 691.775 3260.45 ;
        RECT 216.99 3376.59 691.775 3376.93 ;
    END
    PORT
      LAYER met3 ;
        RECT 216.99 1744.59 691.775 1744.93 ;
        RECT 216.99 1861.07 691.775 1861.41 ;
        RECT 216.99 1977.55 691.775 1977.89 ;
        RECT 216.99 2094.03 691.775 2094.37 ;
        RECT 216.99 2210.51 691.775 2210.85 ;
        RECT 216.99 2326.99 691.775 2327.33 ;
        RECT 216.99 2443.47 691.775 2443.81 ;
        RECT 216.99 2559.95 691.775 2560.29 ;
        RECT 216.99 2676.43 691.775 2676.77 ;
        RECT 216.99 2792.91 691.775 2793.25 ;
        RECT 216.99 2909.39 691.775 2909.73 ;
        RECT 216.99 3025.87 691.775 3026.21 ;
        RECT 216.99 3142.35 691.775 3142.69 ;
        RECT 216.99 3258.83 691.775 3259.17 ;
        RECT 216.99 3375.31 691.775 3375.65 ;
    END
    PORT
      LAYER met3 ;
        RECT 216.99 1738.59 691.775 1738.93 ;
        RECT 216.99 1855.07 691.775 1855.41 ;
        RECT 216.99 1971.55 691.775 1971.89 ;
        RECT 216.99 2088.03 691.775 2088.37 ;
        RECT 216.99 2204.51 691.775 2204.85 ;
        RECT 216.99 2320.99 691.775 2321.33 ;
        RECT 216.99 2437.47 691.775 2437.81 ;
        RECT 216.99 2553.95 691.775 2554.29 ;
        RECT 216.99 2670.43 691.775 2670.77 ;
        RECT 216.99 2786.91 691.775 2787.25 ;
        RECT 216.99 2903.39 691.775 2903.73 ;
        RECT 216.99 3019.87 691.775 3020.21 ;
        RECT 216.99 3136.35 691.775 3136.69 ;
        RECT 216.99 3252.83 691.775 3253.17 ;
        RECT 216.99 3369.31 691.775 3369.65 ;
    END
    PORT
      LAYER met3 ;
        RECT 216.99 1737.31 691.775 1737.65 ;
        RECT 216.99 1853.79 691.775 1854.13 ;
        RECT 216.99 1970.27 691.775 1970.61 ;
        RECT 216.99 2086.75 691.775 2087.09 ;
        RECT 216.99 2203.23 691.775 2203.57 ;
        RECT 216.99 2319.71 691.775 2320.05 ;
        RECT 216.99 2436.19 691.775 2436.53 ;
        RECT 216.99 2552.67 691.775 2553.01 ;
        RECT 216.99 2669.15 691.775 2669.49 ;
        RECT 216.99 2785.63 691.775 2785.97 ;
        RECT 216.99 2902.11 691.775 2902.45 ;
        RECT 216.99 3018.59 691.775 3018.93 ;
        RECT 216.99 3135.07 691.775 3135.41 ;
        RECT 216.99 3251.55 691.775 3251.89 ;
        RECT 216.99 3368.03 691.775 3368.37 ;
    END
    PORT
      LAYER met3 ;
        RECT 216.99 1731.31 691.775 1731.65 ;
        RECT 216.99 1847.79 691.775 1848.13 ;
        RECT 216.99 1964.27 691.775 1964.61 ;
        RECT 216.99 2080.75 691.775 2081.09 ;
        RECT 216.99 2197.23 691.775 2197.57 ;
        RECT 216.99 2313.71 691.775 2314.05 ;
        RECT 216.99 2430.19 691.775 2430.53 ;
        RECT 216.99 2546.67 691.775 2547.01 ;
        RECT 216.99 2663.15 691.775 2663.49 ;
        RECT 216.99 2779.63 691.775 2779.97 ;
        RECT 216.99 2896.11 691.775 2896.45 ;
        RECT 216.99 3012.59 691.775 3012.93 ;
        RECT 216.99 3129.07 691.775 3129.41 ;
        RECT 216.99 3245.55 691.775 3245.89 ;
        RECT 216.99 3362.03 691.775 3362.37 ;
    END
    PORT
      LAYER met3 ;
        RECT 216.99 1730.03 691.775 1730.37 ;
        RECT 216.99 1846.51 691.775 1846.85 ;
        RECT 216.99 1962.99 691.775 1963.33 ;
        RECT 216.99 2079.47 691.775 2079.81 ;
        RECT 216.99 2195.95 691.775 2196.29 ;
        RECT 216.99 2312.43 691.775 2312.77 ;
        RECT 216.99 2428.91 691.775 2429.25 ;
        RECT 216.99 2545.39 691.775 2545.73 ;
        RECT 216.99 2661.87 691.775 2662.21 ;
        RECT 216.99 2778.35 691.775 2778.69 ;
        RECT 216.99 2894.83 691.775 2895.17 ;
        RECT 216.99 3011.31 691.775 3011.65 ;
        RECT 216.99 3127.79 691.775 3128.13 ;
        RECT 216.99 3244.27 691.775 3244.61 ;
        RECT 216.99 3360.75 691.775 3361.09 ;
    END
    PORT
      LAYER met3 ;
        RECT 216.99 1724.03 691.775 1724.37 ;
        RECT 216.99 1840.51 691.775 1840.85 ;
        RECT 216.99 1956.99 691.775 1957.33 ;
        RECT 216.99 2073.47 691.775 2073.81 ;
        RECT 216.99 2189.95 691.775 2190.29 ;
        RECT 216.99 2306.43 691.775 2306.77 ;
        RECT 216.99 2422.91 691.775 2423.25 ;
        RECT 216.99 2539.39 691.775 2539.73 ;
        RECT 216.99 2655.87 691.775 2656.21 ;
        RECT 216.99 2772.35 691.775 2772.69 ;
        RECT 216.99 2888.83 691.775 2889.17 ;
        RECT 216.99 3005.31 691.775 3005.65 ;
        RECT 216.99 3121.79 691.775 3122.13 ;
        RECT 216.99 3238.27 691.775 3238.61 ;
        RECT 216.99 3354.75 691.775 3355.09 ;
    END
    PORT
      LAYER met3 ;
        RECT 216.99 1722.75 691.775 1723.09 ;
        RECT 216.99 1839.23 691.775 1839.57 ;
        RECT 216.99 1955.71 691.775 1956.05 ;
        RECT 216.99 2072.19 691.775 2072.53 ;
        RECT 216.99 2188.67 691.775 2189.01 ;
        RECT 216.99 2305.15 691.775 2305.49 ;
        RECT 216.99 2421.63 691.775 2421.97 ;
        RECT 216.99 2538.11 691.775 2538.45 ;
        RECT 216.99 2654.59 691.775 2654.93 ;
        RECT 216.99 2771.07 691.775 2771.41 ;
        RECT 216.99 2887.55 691.775 2887.89 ;
        RECT 216.99 3004.03 691.775 3004.37 ;
        RECT 216.99 3120.51 691.775 3120.85 ;
        RECT 216.99 3236.99 691.775 3237.33 ;
        RECT 216.99 3353.47 691.775 3353.81 ;
    END
    PORT
      LAYER met3 ;
        RECT 216.99 1716.75 691.775 1717.09 ;
        RECT 216.99 1833.23 691.775 1833.57 ;
        RECT 216.99 1949.71 691.775 1950.05 ;
        RECT 216.99 2066.19 691.775 2066.53 ;
        RECT 216.99 2182.67 691.775 2183.01 ;
        RECT 216.99 2299.15 691.775 2299.49 ;
        RECT 216.99 2415.63 691.775 2415.97 ;
        RECT 216.99 2532.11 691.775 2532.45 ;
        RECT 216.99 2648.59 691.775 2648.93 ;
        RECT 216.99 2765.07 691.775 2765.41 ;
        RECT 216.99 2881.55 691.775 2881.89 ;
        RECT 216.99 2998.03 691.775 2998.37 ;
        RECT 216.99 3114.51 691.775 3114.85 ;
        RECT 216.99 3230.99 691.775 3231.33 ;
        RECT 216.99 3347.47 691.775 3347.81 ;
    END
    PORT
      LAYER met3 ;
        RECT 216.99 1715.47 691.775 1715.81 ;
        RECT 216.99 1831.95 691.775 1832.29 ;
        RECT 216.99 1948.43 691.775 1948.77 ;
        RECT 216.99 2064.91 691.775 2065.25 ;
        RECT 216.99 2181.39 691.775 2181.73 ;
        RECT 216.99 2297.87 691.775 2298.21 ;
        RECT 216.99 2414.35 691.775 2414.69 ;
        RECT 216.99 2530.83 691.775 2531.17 ;
        RECT 216.99 2647.31 691.775 2647.65 ;
        RECT 216.99 2763.79 691.775 2764.13 ;
        RECT 216.99 2880.27 691.775 2880.61 ;
        RECT 216.99 2996.75 691.775 2997.09 ;
        RECT 216.99 3113.23 691.775 3113.57 ;
        RECT 216.99 3229.71 691.775 3230.05 ;
        RECT 216.99 3346.19 691.775 3346.53 ;
    END
    PORT
      LAYER met3 ;
        RECT 216.99 1709.47 691.775 1709.81 ;
        RECT 216.99 1825.95 691.775 1826.29 ;
        RECT 216.99 1942.43 691.775 1942.77 ;
        RECT 216.99 2058.91 691.775 2059.25 ;
        RECT 216.99 2175.39 691.775 2175.73 ;
        RECT 216.99 2291.87 691.775 2292.21 ;
        RECT 216.99 2408.35 691.775 2408.69 ;
        RECT 216.99 2524.83 691.775 2525.17 ;
        RECT 216.99 2641.31 691.775 2641.65 ;
        RECT 216.99 2757.79 691.775 2758.13 ;
        RECT 216.99 2874.27 691.775 2874.61 ;
        RECT 216.99 2990.75 691.775 2991.09 ;
        RECT 216.99 3107.23 691.775 3107.57 ;
        RECT 216.99 3223.71 691.775 3224.05 ;
        RECT 216.99 3340.19 691.775 3340.53 ;
    END
    PORT
      LAYER met3 ;
        RECT 216.99 1708.19 691.775 1708.53 ;
        RECT 216.99 1824.67 691.775 1825.01 ;
        RECT 216.99 1941.15 691.775 1941.49 ;
        RECT 216.99 2057.63 691.775 2057.97 ;
        RECT 216.99 2174.11 691.775 2174.45 ;
        RECT 216.99 2290.59 691.775 2290.93 ;
        RECT 216.99 2407.07 691.775 2407.41 ;
        RECT 216.99 2523.55 691.775 2523.89 ;
        RECT 216.99 2640.03 691.775 2640.37 ;
        RECT 216.99 2756.51 691.775 2756.85 ;
        RECT 216.99 2872.99 691.775 2873.33 ;
        RECT 216.99 2989.47 691.775 2989.81 ;
        RECT 216.99 3105.95 691.775 3106.29 ;
        RECT 216.99 3222.43 691.775 3222.77 ;
        RECT 216.99 3338.91 691.775 3339.25 ;
    END
    PORT
      LAYER met3 ;
        RECT 216.99 1702.19 691.775 1702.53 ;
        RECT 216.99 1818.67 691.775 1819.01 ;
        RECT 216.99 1935.15 691.775 1935.49 ;
        RECT 216.99 2051.63 691.775 2051.97 ;
        RECT 216.99 2168.11 691.775 2168.45 ;
        RECT 216.99 2284.59 691.775 2284.93 ;
        RECT 216.99 2401.07 691.775 2401.41 ;
        RECT 216.99 2517.55 691.775 2517.89 ;
        RECT 216.99 2634.03 691.775 2634.37 ;
        RECT 216.99 2750.51 691.775 2750.85 ;
        RECT 216.99 2866.99 691.775 2867.33 ;
        RECT 216.99 2983.47 691.775 2983.81 ;
        RECT 216.99 3099.95 691.775 3100.29 ;
        RECT 216.99 3216.43 691.775 3216.77 ;
        RECT 216.99 3332.91 691.775 3333.25 ;
    END
    PORT
      LAYER met3 ;
        RECT 216.99 1700.91 691.775 1701.25 ;
        RECT 216.99 1817.39 691.775 1817.73 ;
        RECT 216.99 1933.87 691.775 1934.21 ;
        RECT 216.99 2050.35 691.775 2050.69 ;
        RECT 216.99 2166.83 691.775 2167.17 ;
        RECT 216.99 2283.31 691.775 2283.65 ;
        RECT 216.99 2399.79 691.775 2400.13 ;
        RECT 216.99 2516.27 691.775 2516.61 ;
        RECT 216.99 2632.75 691.775 2633.09 ;
        RECT 216.99 2749.23 691.775 2749.57 ;
        RECT 216.99 2865.71 691.775 2866.05 ;
        RECT 216.99 2982.19 691.775 2982.53 ;
        RECT 216.99 3098.67 691.775 3099.01 ;
        RECT 216.99 3215.15 691.775 3215.49 ;
        RECT 216.99 3331.63 691.775 3331.97 ;
    END
    PORT
      LAYER met3 ;
        RECT 216.99 1694.91 691.775 1695.25 ;
        RECT 216.99 1811.39 691.775 1811.73 ;
        RECT 216.99 1927.87 691.775 1928.21 ;
        RECT 216.99 2044.35 691.775 2044.69 ;
        RECT 216.99 2160.83 691.775 2161.17 ;
        RECT 216.99 2277.31 691.775 2277.65 ;
        RECT 216.99 2393.79 691.775 2394.13 ;
        RECT 216.99 2510.27 691.775 2510.61 ;
        RECT 216.99 2626.75 691.775 2627.09 ;
        RECT 216.99 2743.23 691.775 2743.57 ;
        RECT 216.99 2859.71 691.775 2860.05 ;
        RECT 216.99 2976.19 691.775 2976.53 ;
        RECT 216.99 3092.67 691.775 3093.01 ;
        RECT 216.99 3209.15 691.775 3209.49 ;
        RECT 216.99 3325.63 691.775 3325.97 ;
    END
    PORT
      LAYER met3 ;
        RECT 216.99 1693.63 691.775 1693.97 ;
    END
    PORT
      LAYER met3 ;
        RECT 216.99 1664.51 691.775 1664.85 ;
    END
    PORT
      LAYER met3 ;
        RECT 216.99 1651.23 691.775 1651.57 ;
    END
    PORT
      LAYER met3 ;
        RECT 216.99 1658.51 691.775 1658.85 ;
    END
    PORT
      LAYER met3 ;
        RECT 216.99 1657.23 691.775 1657.57 ;
    END
    PORT
      LAYER met3 ;
        RECT 216.99 1679.07 691.775 1679.41 ;
    END
    PORT
      LAYER met3 ;
        RECT 216.99 1665.79 691.775 1666.13 ;
    END
    PORT
      LAYER met3 ;
        RECT 216.99 1673.07 691.775 1673.41 ;
    END
    PORT
      LAYER met3 ;
        RECT 216.99 1671.79 691.775 1672.13 ;
    END
    PORT
      LAYER met3 ;
        RECT 216.99 1686.35 691.775 1686.69 ;
    END
    PORT
      LAYER met3 ;
        RECT 216.99 1687.63 691.775 1687.97 ;
    END
    PORT
      LAYER met3 ;
        RECT 216.99 1680.35 691.775 1680.69 ;
    END
    PORT
      LAYER met3 ;
        RECT 216.99 1620.83 691.775 1621.17 ;
    END
    PORT
      LAYER met3 ;
        RECT 216.99 1607.55 691.775 1607.89 ;
    END
    PORT
      LAYER met3 ;
        RECT 216.99 1614.83 691.775 1615.17 ;
    END
    PORT
      LAYER met3 ;
        RECT 216.99 1613.55 691.775 1613.89 ;
    END
    PORT
      LAYER met3 ;
        RECT 216.99 1635.39 691.775 1635.73 ;
    END
    PORT
      LAYER met3 ;
        RECT 216.99 1622.11 691.775 1622.45 ;
    END
    PORT
      LAYER met3 ;
        RECT 216.99 1629.39 691.775 1629.73 ;
    END
    PORT
      LAYER met3 ;
        RECT 216.99 1628.11 691.775 1628.45 ;
    END
    PORT
      LAYER met3 ;
        RECT 216.99 1649.95 691.775 1650.29 ;
    END
    PORT
      LAYER met3 ;
        RECT 216.99 1636.67 691.775 1637.01 ;
    END
    PORT
      LAYER met3 ;
        RECT 216.99 1643.95 691.775 1644.29 ;
    END
    PORT
      LAYER met3 ;
        RECT 216.99 1642.67 691.775 1643.01 ;
    END
    PORT
      LAYER met3 ;
        RECT 216.99 1591.71 691.775 1592.05 ;
    END
    PORT
      LAYER met3 ;
        RECT 216.99 1578.43 691.775 1578.77 ;
    END
    PORT
      LAYER met3 ;
        RECT 216.99 1585.71 691.775 1586.05 ;
    END
    PORT
      LAYER met3 ;
        RECT 216.99 1584.43 691.775 1584.77 ;
    END
    PORT
      LAYER met3 ;
        RECT 216.99 1606.27 691.775 1606.61 ;
    END
    PORT
      LAYER met3 ;
        RECT 216.99 1592.99 691.775 1593.33 ;
    END
    PORT
      LAYER met3 ;
        RECT 216.99 1600.27 691.775 1600.61 ;
    END
    PORT
      LAYER met3 ;
        RECT 216.99 1598.99 691.775 1599.33 ;
    END
    PORT
      LAYER met3 ;
        RECT 3165.485 1645.445 3656.935 1645.785 ;
    END
    PORT
      LAYER met3 ;
        RECT 3165.485 1640.885 3656.935 1641.225 ;
    END
    PORT
      LAYER met3 ;
        RECT 3165.485 1638.165 3656.935 1638.505 ;
    END
    PORT
      LAYER met3 ;
        RECT 3165.485 1662.725 3656.935 1663.065 ;
    END
    PORT
      LAYER met3 ;
        RECT 3165.485 1660.005 3656.935 1660.345 ;
    END
    PORT
      LAYER met3 ;
        RECT 3165.485 1655.445 3656.935 1655.785 ;
    END
    PORT
      LAYER met3 ;
        RECT 3165.485 1652.725 3656.935 1653.065 ;
    END
    PORT
      LAYER met3 ;
        RECT 3165.485 1677.285 3656.935 1677.625 ;
    END
    PORT
      LAYER met3 ;
        RECT 3165.485 1674.565 3656.935 1674.905 ;
    END
    PORT
      LAYER met3 ;
        RECT 3165.485 1670.005 3656.935 1670.345 ;
    END
    PORT
      LAYER met3 ;
        RECT 3165.485 1667.285 3656.935 1667.625 ;
    END
    PORT
      LAYER met3 ;
        RECT 3165.485 1684.565 3656.935 1684.905 ;
    END
    PORT
      LAYER met3 ;
        RECT 3165.485 1689.125 3656.935 1689.465 ;
    END
    PORT
      LAYER met3 ;
        RECT 3165.485 1681.845 3656.935 1682.185 ;
    END
    PORT
      LAYER met3 ;
        RECT 3165.485 1691.845 3656.935 1692.185 ;
    END
    PORT
      LAYER met3 ;
        RECT 3165.485 1589.925 3656.935 1590.265 ;
    END
    PORT
      LAYER met3 ;
        RECT 3165.485 1587.205 3656.935 1587.545 ;
    END
    PORT
      LAYER met3 ;
        RECT 3165.485 1582.645 3656.935 1582.985 ;
    END
    PORT
      LAYER met3 ;
        RECT 3165.485 1579.925 3656.935 1580.265 ;
    END
    PORT
      LAYER met3 ;
        RECT 3165.485 1604.485 3656.935 1604.825 ;
    END
    PORT
      LAYER met3 ;
        RECT 3165.485 1601.765 3656.935 1602.105 ;
    END
    PORT
      LAYER met3 ;
        RECT 3165.485 1597.205 3656.935 1597.545 ;
    END
    PORT
      LAYER met3 ;
        RECT 3165.485 1594.485 3656.935 1594.825 ;
    END
    PORT
      LAYER met3 ;
        RECT 3165.485 1619.045 3656.935 1619.385 ;
    END
    PORT
      LAYER met3 ;
        RECT 3165.485 1616.325 3656.935 1616.665 ;
    END
    PORT
      LAYER met3 ;
        RECT 3165.485 1611.765 3656.935 1612.105 ;
    END
    PORT
      LAYER met3 ;
        RECT 3165.485 1609.045 3656.935 1609.385 ;
    END
    PORT
      LAYER met3 ;
        RECT 3165.485 1633.605 3656.935 1633.945 ;
    END
    PORT
      LAYER met3 ;
        RECT 3165.485 1630.885 3656.935 1631.225 ;
    END
    PORT
      LAYER met3 ;
        RECT 3165.485 1626.325 3656.935 1626.665 ;
    END
    PORT
      LAYER met3 ;
        RECT 3165.485 1623.605 3656.935 1623.945 ;
    END
    PORT
      LAYER met3 ;
        RECT 3165.485 1648.165 3656.935 1648.505 ;
    END
  END VDDC2
  PIN Vcc_wl_read
    DIRECTION INPUT ;
    USE SIGNAL ;
    PORT
      LAYER met3 ;
        RECT 216.895 3484.1 816.89 3485.1 ;
    END
    PORT
      LAYER met3 ;
        RECT 216.895 3488.1 816.89 3489.1 ;
    END
    PORT
      LAYER met3 ;
        RECT 216.895 3486.1 816.89 3487.1 ;
    END
  END Vcc_wl_read
  PIN Vcc_wl_set
    DIRECTION INPUT ;
    USE SIGNAL ;
    PORT
      LAYER met3 ;
        RECT 216.895 3492.1 816.89 3493.1 ;
    END
    PORT
      LAYER met3 ;
        RECT 216.895 3496.1 816.89 3497.1 ;
    END
    PORT
      LAYER met3 ;
        RECT 216.895 3494.1 816.89 3495.1 ;
    END
  END Vcc_wl_set
  PIN Vcc_wl_reset
    DIRECTION INPUT ;
    USE SIGNAL ;
    PORT
      LAYER met3 ;
        RECT 216.895 3500.24 816.89 3501.24 ;
    END
    PORT
      LAYER met3 ;
        RECT 216.895 3504.24 816.89 3505.24 ;
    END
    PORT
      LAYER met3 ;
        RECT 216.895 3502.24 816.89 3503.24 ;
    END
  END Vcc_wl_reset
  PIN VDDA2
    DIRECTION INOUT ;
    USE POWER ;
    PORT
      LAYER met3 ;
        RECT 2962.435 3500.38 3656.84 3501.38 ;
    END
    PORT
      LAYER met3 ;
        RECT 2962.435 3504.38 3656.84 3505.38 ;
    END
    PORT
      LAYER met3 ;
        RECT 2962.435 3502.38 3656.84 3503.38 ;
    END
  END VDDA2
  PIN Vcc_set
    DIRECTION INPUT ;
    USE SIGNAL ;
    PORT
      LAYER met3 ;
        RECT 2962.435 3492.24 3656.84 3493.24 ;
    END
    PORT
      LAYER met3 ;
        RECT 2962.435 3496.24 3656.84 3497.24 ;
    END
    PORT
      LAYER met3 ;
        RECT 2962.435 3494.24 3656.84 3495.24 ;
    END
  END Vcc_set
  PIN Vcc_read
    DIRECTION INPUT ;
    USE SIGNAL ;
    PORT
      LAYER met3 ;
        RECT 2962.435 3484.24 3656.84 3485.24 ;
    END
    PORT
      LAYER met3 ;
        RECT 2962.435 3488.24 3656.84 3489.24 ;
    END
    PORT
      LAYER met3 ;
        RECT 2962.435 3486.24 3656.84 3487.24 ;
    END
  END Vcc_read
  PIN dc_bias
    DIRECTION INPUT ;
    USE SIGNAL ;
    PORT
      LAYER met3 ;
        RECT 1362.32 1405.725 2252.74 1406.855 ;
    END
  END dc_bias
  PIN Iref
    DIRECTION INPUT ;
    USE SIGNAL ;
    PORT
      LAYER met3 ;
        RECT 1362.32 1471.96 2252.74 1473.26 ;
    END
    PORT
      LAYER met3 ;
        RECT 1362.32 1473.96 2252.74 1475.26 ;
    END
  END Iref
  PIN Vbias
    DIRECTION INPUT ;
    USE SIGNAL ;
    PORT
      LAYER met3 ;
        RECT 1362.32 1479.98 2252.74 1481.11 ;
    END
    PORT
      LAYER met3 ;
        RECT 1362.32 1478.35 2252.74 1479.48 ;
    END
  END Vbias
  PIN Vcomp
    DIRECTION INPUT ;
    USE SIGNAL ;
    PORT
      LAYER met3 ;
        RECT 1362.32 1432.88 2252.74 1434.01 ;
    END
    PORT
      LAYER met3 ;
        RECT 1362.32 1452.31 2252.74 1453.44 ;
    END
  END Vcomp
  PIN Bias_comp2
    DIRECTION INPUT ;
    USE SIGNAL ;
    PORT
      LAYER met3 ;
        RECT 1362.32 1380.01 2252.74 1381.14 ;
    END
  END Bias_comp2
  PIN VDDC1
    DIRECTION INOUT ;
    USE POWER ;
    PORT
      LAYER met3 ;
        RECT 0 418.6 3874 420.4 ;
    END
    PORT
      LAYER met3 ;
        RECT 0 818.6 3874 820.4 ;
    END
    PORT
      LAYER met3 ;
        RECT 0 918.6 3874 920.4 ;
    END
    PORT
      LAYER met3 ;
        RECT 0 1018.6 3874 1020.4 ;
    END
    PORT
      LAYER met3 ;
        RECT 0 1118.6 3874 1120.4 ;
    END
    PORT
      LAYER met3 ;
        RECT 0 518.6 3874 520.4 ;
    END
    PORT
      LAYER met3 ;
        RECT 0 618.6 3874 620.4 ;
    END
    PORT
      LAYER met3 ;
        RECT 0 718.6 3874 720.4 ;
    END
    PORT
      LAYER met3 ;
        RECT 0 18.6 3874 20.4 ;
    END
    PORT
      LAYER met3 ;
        RECT 0 118.6 3874 120.4 ;
    END
    PORT
      LAYER met3 ;
        RECT 0 218.6 3874 220.4 ;
    END
    PORT
      LAYER met3 ;
        RECT 0 318.6 3874 320.4 ;
    END
    PORT
      LAYER met3 ;
        RECT 0 3718.6 205 3720.4 ;
    END
    PORT
      LAYER met3 ;
        RECT 3669 3718.6 3874 3720.4 ;
    END
    PORT
      LAYER met3 ;
        RECT 0 3618.6 205 3620.4 ;
    END
    PORT
      LAYER met3 ;
        RECT 3669 3618.6 3874 3620.4 ;
    END
    PORT
      LAYER met3 ;
        RECT 0 3518.6 205 3520.4 ;
    END
    PORT
      LAYER met3 ;
        RECT 3669 3518.6 3874 3520.4 ;
    END
    PORT
      LAYER met3 ;
        RECT 0 3418.6 205 3420.4 ;
    END
    PORT
      LAYER met3 ;
        RECT 3669 3418.6 3874 3420.4 ;
    END
    PORT
      LAYER met3 ;
        RECT 0 3318.6 205 3320.4 ;
    END
    PORT
      LAYER met3 ;
        RECT 3669 3318.6 3874 3320.4 ;
    END
    PORT
      LAYER met3 ;
        RECT 0 3218.6 205 3220.4 ;
    END
    PORT
      LAYER met3 ;
        RECT 3669 3218.6 3874 3220.4 ;
    END
    PORT
      LAYER met3 ;
        RECT 0 3118.6 205 3120.4 ;
    END
    PORT
      LAYER met3 ;
        RECT 3669 3118.6 3874 3120.4 ;
    END
    PORT
      LAYER met3 ;
        RECT 0 3018.6 205 3020.4 ;
    END
    PORT
      LAYER met3 ;
        RECT 3669 3018.6 3874 3020.4 ;
    END
    PORT
      LAYER met3 ;
        RECT 0 2918.6 205 2920.4 ;
    END
    PORT
      LAYER met3 ;
        RECT 3669 2918.6 3874 2920.4 ;
    END
    PORT
      LAYER met3 ;
        RECT 0 2818.6 205 2820.4 ;
    END
    PORT
      LAYER met3 ;
        RECT 3669 2818.6 3874 2820.4 ;
    END
    PORT
      LAYER met3 ;
        RECT 0 2718.6 205 2720.4 ;
    END
    PORT
      LAYER met3 ;
        RECT 3669 2718.6 3874 2720.4 ;
    END
    PORT
      LAYER met3 ;
        RECT 0 2618.6 205 2620.4 ;
    END
    PORT
      LAYER met3 ;
        RECT 3669 2618.6 3874 2620.4 ;
    END
    PORT
      LAYER met3 ;
        RECT 0 2518.6 205 2520.4 ;
    END
    PORT
      LAYER met3 ;
        RECT 3669 2518.6 3874 2520.4 ;
    END
    PORT
      LAYER met3 ;
        RECT 0 2418.6 205 2420.4 ;
    END
    PORT
      LAYER met3 ;
        RECT 3669 2418.6 3874 2420.4 ;
    END
    PORT
      LAYER met3 ;
        RECT 0 2318.6 205 2320.4 ;
    END
    PORT
      LAYER met3 ;
        RECT 3669 2318.6 3874 2320.4 ;
    END
    PORT
      LAYER met3 ;
        RECT 0 2218.6 205 2220.4 ;
    END
    PORT
      LAYER met3 ;
        RECT 3669 2218.6 3874 2220.4 ;
    END
    PORT
      LAYER met3 ;
        RECT 0 2118.6 205 2120.4 ;
    END
    PORT
      LAYER met3 ;
        RECT 3669 2118.6 3874 2120.4 ;
    END
    PORT
      LAYER met3 ;
        RECT 0 2018.6 205 2020.4 ;
    END
    PORT
      LAYER met3 ;
        RECT 3669 2018.6 3874 2020.4 ;
    END
    PORT
      LAYER met3 ;
        RECT 0 1718.6 205 1720.4 ;
    END
    PORT
      LAYER met3 ;
        RECT 0 1818.6 205 1820.4 ;
    END
    PORT
      LAYER met3 ;
        RECT 0 1918.6 205 1920.4 ;
    END
    PORT
      LAYER met3 ;
        RECT 0 1318.6 205 1320.4 ;
    END
    PORT
      LAYER met3 ;
        RECT 0 1418.6 205 1420.4 ;
    END
    PORT
      LAYER met3 ;
        RECT 0 1518.6 205 1520.4 ;
    END
    PORT
      LAYER met3 ;
        RECT 0 1618.6 205 1620.4 ;
    END
    PORT
      LAYER met3 ;
        RECT 3669 1418.6 3874 1420.4 ;
    END
    PORT
      LAYER met3 ;
        RECT 3669 1518.6 3874 1520.4 ;
    END
    PORT
      LAYER met3 ;
        RECT 3669 1618.6 3874 1620.4 ;
    END
    PORT
      LAYER met3 ;
        RECT 3669 1718.6 3874 1720.4 ;
    END
    PORT
      LAYER met3 ;
        RECT 3669 1818.6 3874 1820.4 ;
    END
    PORT
      LAYER met3 ;
        RECT 3669 1918.6 3874 1920.4 ;
    END
    PORT
      LAYER met3 ;
        RECT 3669 1318.6 3874 1320.4 ;
    END
    PORT
      LAYER met3 ;
        RECT 0 1218.6 3874 1220.4 ;
    END
  END VDDC1
  PIN wbs_dat_i[8]
    DIRECTION INPUT ;
    USE SIGNAL ;
    PORT
      LAYER met2 ;
        RECT 1284.87 0 1285.17 2.91 ;
    END
  END wbs_dat_i[8]
  PIN wbs_dat_i[9]
    DIRECTION INPUT ;
    USE SIGNAL ;
    PORT
      LAYER met2 ;
        RECT 1292.35 0 1292.65 2.91 ;
    END
  END wbs_dat_i[9]
  PIN wbs_dat_i[10]
    DIRECTION INPUT ;
    USE SIGNAL ;
    PORT
      LAYER met2 ;
        RECT 1299.49 0 1299.79 2.91 ;
    END
  END wbs_dat_i[10]
  PIN wbs_dat_i[11]
    DIRECTION INPUT ;
    USE SIGNAL ;
    PORT
      LAYER met2 ;
        RECT 1306.63 0 1306.93 2.91 ;
    END
  END wbs_dat_i[11]
  PIN wbs_dat_i[12]
    DIRECTION INPUT ;
    USE SIGNAL ;
    PORT
      LAYER met2 ;
        RECT 1313.77 0 1314.07 2.91 ;
    END
  END wbs_dat_i[12]
  PIN wbs_dat_i[13]
    DIRECTION INPUT ;
    USE SIGNAL ;
    PORT
      LAYER met2 ;
        RECT 1320.91 0 1321.21 2.91 ;
    END
  END wbs_dat_i[13]
  PIN wbs_dat_i[14]
    DIRECTION INPUT ;
    USE SIGNAL ;
    PORT
      LAYER met2 ;
        RECT 1328.05 0 1328.35 2.91 ;
    END
  END wbs_dat_i[14]
  PIN wbs_dat_i[15]
    DIRECTION INPUT ;
    USE SIGNAL ;
    PORT
      LAYER met2 ;
        RECT 1335.53 0 1335.83 2.91 ;
    END
  END wbs_dat_i[15]
  PIN wbs_dat_i[16]
    DIRECTION INPUT ;
    USE SIGNAL ;
    PORT
      LAYER met2 ;
        RECT 1342.67 0 1342.97 2.91 ;
    END
  END wbs_dat_i[16]
  PIN wbs_dat_i[17]
    DIRECTION INPUT ;
    USE SIGNAL ;
    PORT
      LAYER met2 ;
        RECT 1349.81 0 1350.11 2.91 ;
    END
  END wbs_dat_i[17]
  PIN wbs_dat_i[18]
    DIRECTION INPUT ;
    USE SIGNAL ;
    PORT
      LAYER met2 ;
        RECT 1356.95 0 1357.25 2.91 ;
    END
  END wbs_dat_i[18]
  PIN wbs_dat_i[19]
    DIRECTION INPUT ;
    USE SIGNAL ;
    PORT
      LAYER met2 ;
        RECT 1364.09 0 1364.39 2.91 ;
    END
  END wbs_dat_i[19]
  PIN wbs_dat_i[20]
    DIRECTION INPUT ;
    USE SIGNAL ;
    PORT
      LAYER met2 ;
        RECT 1371.23 0 1371.53 2.91 ;
    END
  END wbs_dat_i[20]
  PIN wbs_dat_i[21]
    DIRECTION INPUT ;
    USE SIGNAL ;
    PORT
      LAYER met2 ;
        RECT 1378.71 0 1379.01 2.91 ;
    END
  END wbs_dat_i[21]
  PIN wbs_dat_i[22]
    DIRECTION INPUT ;
    USE SIGNAL ;
    PORT
      LAYER met2 ;
        RECT 1385.85 0 1386.15 2.91 ;
    END
  END wbs_dat_i[22]
  PIN wbs_dat_i[23]
    DIRECTION INPUT ;
    USE SIGNAL ;
    PORT
      LAYER met2 ;
        RECT 1392.99 0 1393.29 2.91 ;
    END
  END wbs_dat_i[23]
  PIN wbs_dat_i[24]
    DIRECTION INPUT ;
    USE SIGNAL ;
    PORT
      LAYER met2 ;
        RECT 1400.13 0 1400.43 2.91 ;
    END
  END wbs_dat_i[24]
  PIN wbs_dat_i[25]
    DIRECTION INPUT ;
    USE SIGNAL ;
    PORT
      LAYER met2 ;
        RECT 1407.27 0 1407.57 2.91 ;
    END
  END wbs_dat_i[25]
  PIN wbs_dat_i[26]
    DIRECTION INPUT ;
    USE SIGNAL ;
    PORT
      LAYER met2 ;
        RECT 1414.75 0 1415.05 2.91 ;
    END
  END wbs_dat_i[26]
  PIN wbs_dat_i[27]
    DIRECTION INPUT ;
    USE SIGNAL ;
    PORT
      LAYER met2 ;
        RECT 1421.89 0 1422.19 2.91 ;
    END
  END wbs_dat_i[27]
  PIN wbs_dat_i[28]
    DIRECTION INPUT ;
    USE SIGNAL ;
    PORT
      LAYER met2 ;
        RECT 1429.03 0 1429.33 2.91 ;
    END
  END wbs_dat_i[28]
  PIN wbs_dat_i[29]
    DIRECTION INPUT ;
    USE SIGNAL ;
    PORT
      LAYER met2 ;
        RECT 1436.17 0 1436.47 2.91 ;
    END
  END wbs_dat_i[29]
  PIN wbs_dat_i[30]
    DIRECTION INPUT ;
    USE SIGNAL ;
    PORT
      LAYER met2 ;
        RECT 1443.31 0 1443.61 2.91 ;
    END
  END wbs_dat_i[30]
  PIN wbs_dat_i[31]
    DIRECTION INPUT ;
    USE SIGNAL ;
    PORT
      LAYER met2 ;
        RECT 1450.45 0 1450.75 2.91 ;
    END
  END wbs_dat_i[31]
  PIN wbs_dat_i[0]
    DIRECTION INPUT ;
    USE SIGNAL ;
    PORT
      LAYER met2 ;
        RECT 1227.41 0 1227.71 2.91 ;
    END
  END wbs_dat_i[0]
  PIN ScanOutCC
    DIRECTION OUTPUT ;
    USE SIGNAL ;
    PORT
      LAYER met2 ;
        RECT 890.81 0 891.11 2.91 ;
    END
  END ScanOutCC
  PIN ScanInDR
    DIRECTION INPUT ;
    USE SIGNAL ;
    PORT
      LAYER met2 ;
        RECT 879.93 0 880.23 2.91 ;
    END
  END ScanInDR
  PIN ScanInDL
    DIRECTION INPUT ;
    USE SIGNAL ;
    PORT
      LAYER met2 ;
        RECT 883.33 0 883.63 2.91 ;
    END
  END ScanInDL
  PIN ScanInCC
    DIRECTION INPUT ;
    USE SIGNAL ;
    PORT
      LAYER met2 ;
        RECT 887.07 0 887.37 2.91 ;
    END
  END ScanInCC
  PIN wbs_we_i
    DIRECTION INPUT ;
    USE SIGNAL ;
    PORT
      LAYER met2 ;
        RECT 984.65 0 984.95 2.91 ;
    END
  END wbs_we_i
  PIN TM
    DIRECTION INPUT ;
    USE SIGNAL ;
    PORT
      LAYER met2 ;
        RECT 974.79 0 975.09 2.91 ;
    END
  END TM
  PIN wbs_ack_o
    DIRECTION OUTPUT ;
    USE SIGNAL ;
    PORT
      LAYER met2 ;
        RECT 991.79 0 992.09 2.91 ;
    END
  END wbs_ack_o
  PIN wb_rst_i
    DIRECTION INPUT ;
    USE SIGNAL ;
    PORT
      LAYER met2 ;
        RECT 988.39 0 988.69 2.91 ;
    END
  END wb_rst_i
  PIN wb_clk_i
    DIRECTION INPUT ;
    USE SIGNAL ;
    PORT
      LAYER met2 ;
        RECT 995.53 0 995.83 2.91 ;
    END
  END wb_clk_i
  PIN user_rst
    DIRECTION INPUT ;
    USE SIGNAL ;
    PORT
      LAYER met2 ;
        RECT 1019.33 0 1019.63 2.91 ;
    END
  END user_rst
  PIN user_clk
    DIRECTION INPUT ;
    USE SIGNAL ;
    PORT
      LAYER met2 ;
        RECT 555.91 0 556.21 2.91 ;
    END
  END user_clk
  PIN wbs_dat_o[1]
    DIRECTION OUTPUT ;
    USE SIGNAL ;
    PORT
      LAYER met2 ;
        RECT 1561.97 0 1562.27 2.91 ;
    END
  END wbs_dat_o[1]
  PIN wbs_dat_o[2]
    DIRECTION OUTPUT ;
    USE SIGNAL ;
    PORT
      LAYER met2 ;
        RECT 1569.11 0 1569.41 2.91 ;
    END
  END wbs_dat_o[2]
  PIN wbs_dat_o[3]
    DIRECTION OUTPUT ;
    USE SIGNAL ;
    PORT
      LAYER met2 ;
        RECT 1576.25 0 1576.55 2.91 ;
    END
  END wbs_dat_o[3]
  PIN wbs_dat_o[4]
    DIRECTION OUTPUT ;
    USE SIGNAL ;
    PORT
      LAYER met2 ;
        RECT 1583.39 0 1583.69 2.91 ;
    END
  END wbs_dat_o[4]
  PIN wbs_dat_o[5]
    DIRECTION OUTPUT ;
    USE SIGNAL ;
    PORT
      LAYER met2 ;
        RECT 1590.87 0 1591.17 2.91 ;
    END
  END wbs_dat_o[5]
  PIN wbs_dat_o[6]
    DIRECTION OUTPUT ;
    USE SIGNAL ;
    PORT
      LAYER met2 ;
        RECT 1598.01 0 1598.31 2.91 ;
    END
  END wbs_dat_o[6]
  PIN wbs_dat_o[7]
    DIRECTION OUTPUT ;
    USE SIGNAL ;
    PORT
      LAYER met2 ;
        RECT 1605.15 0 1605.45 2.91 ;
    END
  END wbs_dat_o[7]
  PIN wbs_dat_o[8]
    DIRECTION OUTPUT ;
    USE SIGNAL ;
    PORT
      LAYER met2 ;
        RECT 1612.29 0 1612.59 2.91 ;
    END
  END wbs_dat_o[8]
  PIN wbs_dat_o[9]
    DIRECTION OUTPUT ;
    USE SIGNAL ;
    PORT
      LAYER met2 ;
        RECT 1619.43 0 1619.73 2.91 ;
    END
  END wbs_dat_o[9]
  PIN wbs_dat_o[10]
    DIRECTION OUTPUT ;
    USE SIGNAL ;
    PORT
      LAYER met2 ;
        RECT 1626.91 0 1627.21 2.91 ;
    END
  END wbs_dat_o[10]
  PIN wbs_dat_o[11]
    DIRECTION OUTPUT ;
    USE SIGNAL ;
    PORT
      LAYER met2 ;
        RECT 1634.05 0 1634.35 2.91 ;
    END
  END wbs_dat_o[11]
  PIN wbs_dat_o[12]
    DIRECTION OUTPUT ;
    USE SIGNAL ;
    PORT
      LAYER met2 ;
        RECT 1641.19 0 1641.49 2.91 ;
    END
  END wbs_dat_o[12]
  PIN wbs_dat_o[13]
    DIRECTION OUTPUT ;
    USE SIGNAL ;
    PORT
      LAYER met2 ;
        RECT 1648.33 0 1648.63 2.91 ;
    END
  END wbs_dat_o[13]
  PIN wbs_cyc_i
    DIRECTION INPUT ;
    USE SIGNAL ;
    PORT
      LAYER met2 ;
        RECT 977.85 0 978.15 2.91 ;
    END
  END wbs_cyc_i
  PIN wbs_dat_o[14]
    DIRECTION OUTPUT ;
    USE SIGNAL ;
    PORT
      LAYER met2 ;
        RECT 1655.47 0 1655.77 2.91 ;
    END
  END wbs_dat_o[14]
  PIN wbs_dat_o[15]
    DIRECTION OUTPUT ;
    USE SIGNAL ;
    PORT
      LAYER met2 ;
        RECT 1662.61 0 1662.91 2.91 ;
    END
  END wbs_dat_o[15]
  PIN wbs_dat_o[16]
    DIRECTION OUTPUT ;
    USE SIGNAL ;
    PORT
      LAYER met2 ;
        RECT 1670.09 0 1670.39 2.91 ;
    END
  END wbs_dat_o[16]
  PIN wbs_dat_o[17]
    DIRECTION OUTPUT ;
    USE SIGNAL ;
    PORT
      LAYER met2 ;
        RECT 1677.23 0 1677.53 2.91 ;
    END
  END wbs_dat_o[17]
  PIN wbs_dat_o[18]
    DIRECTION OUTPUT ;
    USE SIGNAL ;
    PORT
      LAYER met2 ;
        RECT 1684.37 0 1684.67 2.91 ;
    END
  END wbs_dat_o[18]
  PIN wbs_dat_o[19]
    DIRECTION OUTPUT ;
    USE SIGNAL ;
    PORT
      LAYER met2 ;
        RECT 1691.51 0 1691.81 2.91 ;
    END
  END wbs_dat_o[19]
  PIN wbs_dat_o[20]
    DIRECTION OUTPUT ;
    USE SIGNAL ;
    PORT
      LAYER met2 ;
        RECT 1698.65 0 1698.95 2.91 ;
    END
  END wbs_dat_o[20]
  PIN wbs_dat_o[21]
    DIRECTION OUTPUT ;
    USE SIGNAL ;
    PORT
      LAYER met2 ;
        RECT 1705.79 0 1706.09 2.91 ;
    END
  END wbs_dat_o[21]
  PIN wbs_dat_o[22]
    DIRECTION OUTPUT ;
    USE SIGNAL ;
    PORT
      LAYER met2 ;
        RECT 1713.27 0 1713.57 2.91 ;
    END
  END wbs_dat_o[22]
  PIN wbs_dat_o[23]
    DIRECTION OUTPUT ;
    USE SIGNAL ;
    PORT
      LAYER met2 ;
        RECT 1720.41 0 1720.71 2.91 ;
    END
  END wbs_dat_o[23]
  PIN wbs_dat_o[24]
    DIRECTION OUTPUT ;
    USE SIGNAL ;
    PORT
      LAYER met2 ;
        RECT 1727.55 0 1727.85 2.91 ;
    END
  END wbs_dat_o[24]
  PIN wbs_dat_o[25]
    DIRECTION OUTPUT ;
    USE SIGNAL ;
    PORT
      LAYER met2 ;
        RECT 1734.69 0 1734.99 2.91 ;
    END
  END wbs_dat_o[25]
  PIN wbs_dat_o[26]
    DIRECTION OUTPUT ;
    USE SIGNAL ;
    PORT
      LAYER met2 ;
        RECT 1741.83 0 1742.13 2.91 ;
    END
  END wbs_dat_o[26]
  PIN wbs_dat_o[27]
    DIRECTION OUTPUT ;
    USE SIGNAL ;
    PORT
      LAYER met2 ;
        RECT 1749.31 0 1749.61 2.91 ;
    END
  END wbs_dat_o[27]
  PIN wbs_dat_o[28]
    DIRECTION OUTPUT ;
    USE SIGNAL ;
    PORT
      LAYER met2 ;
        RECT 1756.45 0 1756.75 2.91 ;
    END
  END wbs_dat_o[28]
  PIN wbs_dat_o[29]
    DIRECTION OUTPUT ;
    USE SIGNAL ;
    PORT
      LAYER met2 ;
        RECT 1763.59 0 1763.89 2.91 ;
    END
  END wbs_dat_o[29]
  PIN wbs_dat_o[30]
    DIRECTION OUTPUT ;
    USE SIGNAL ;
    PORT
      LAYER met2 ;
        RECT 1770.73 0 1771.03 2.91 ;
    END
  END wbs_dat_o[30]
  PIN wbs_dat_o[31]
    DIRECTION OUTPUT ;
    USE SIGNAL ;
    PORT
      LAYER met2 ;
        RECT 1777.87 0 1778.17 2.91 ;
    END
  END wbs_dat_o[31]
  PIN wbs_dat_o[0]
    DIRECTION OUTPUT ;
    USE SIGNAL ;
    PORT
      LAYER met2 ;
        RECT 1554.83 0 1555.13 2.91 ;
    END
  END wbs_dat_o[0]
  PIN wbs_sel_i[1]
    DIRECTION INPUT ;
    USE SIGNAL ;
    PORT
      LAYER met2 ;
        RECT 778.95 0 779.25 2.91 ;
    END
  END wbs_sel_i[1]
  PIN wbs_sel_i[2]
    DIRECTION INPUT ;
    USE SIGNAL ;
    PORT
      LAYER met2 ;
        RECT 775.21 0 775.51 2.91 ;
    END
  END wbs_sel_i[2]
  PIN wbs_sel_i[3]
    DIRECTION INPUT ;
    USE SIGNAL ;
    PORT
      LAYER met2 ;
        RECT 771.47 0 771.77 2.91 ;
    END
  END wbs_sel_i[3]
  PIN wbs_sel_i[0]
    DIRECTION INPUT ;
    USE SIGNAL ;
    PORT
      LAYER met2 ;
        RECT 782.35 0 782.65 2.91 ;
    END
  END wbs_sel_i[0]
  PIN wbs_adr_i[1]
    DIRECTION INPUT ;
    USE SIGNAL ;
    PORT
      LAYER met2 ;
        RECT 627.31 0 627.61 2.91 ;
    END
  END wbs_adr_i[1]
  PIN wbs_adr_i[2]
    DIRECTION INPUT ;
    USE SIGNAL ;
    PORT
      LAYER met2 ;
        RECT 630.71 0 631.01 2.91 ;
    END
  END wbs_adr_i[2]
  PIN wbs_adr_i[3]
    DIRECTION INPUT ;
    USE SIGNAL ;
    PORT
      LAYER met2 ;
        RECT 634.45 0 634.75 2.91 ;
    END
  END wbs_adr_i[3]
  PIN wbs_adr_i[4]
    DIRECTION INPUT ;
    USE SIGNAL ;
    PORT
      LAYER met2 ;
        RECT 637.85 0 638.15 2.91 ;
    END
  END wbs_adr_i[4]
  PIN wbs_adr_i[5]
    DIRECTION INPUT ;
    USE SIGNAL ;
    PORT
      LAYER met2 ;
        RECT 641.59 0 641.89 2.91 ;
    END
  END wbs_adr_i[5]
  PIN wbs_adr_i[6]
    DIRECTION INPUT ;
    USE SIGNAL ;
    PORT
      LAYER met2 ;
        RECT 645.33 0 645.63 2.91 ;
    END
  END wbs_adr_i[6]
  PIN wbs_adr_i[7]
    DIRECTION INPUT ;
    USE SIGNAL ;
    PORT
      LAYER met2 ;
        RECT 648.73 0 649.03 2.91 ;
    END
  END wbs_adr_i[7]
  PIN wbs_adr_i[8]
    DIRECTION INPUT ;
    USE SIGNAL ;
    PORT
      LAYER met2 ;
        RECT 652.47 0 652.77 2.91 ;
    END
  END wbs_adr_i[8]
  PIN wbs_adr_i[9]
    DIRECTION INPUT ;
    USE SIGNAL ;
    PORT
      LAYER met2 ;
        RECT 655.87 0 656.17 2.91 ;
    END
  END wbs_adr_i[9]
  PIN wbs_adr_i[10]
    DIRECTION INPUT ;
    USE SIGNAL ;
    PORT
      LAYER met2 ;
        RECT 659.61 0 659.91 2.91 ;
    END
  END wbs_adr_i[10]
  PIN wbs_adr_i[11]
    DIRECTION INPUT ;
    USE SIGNAL ;
    PORT
      LAYER met2 ;
        RECT 663.35 0 663.65 2.91 ;
    END
  END wbs_adr_i[11]
  PIN wbs_adr_i[12]
    DIRECTION INPUT ;
    USE SIGNAL ;
    PORT
      LAYER met2 ;
        RECT 666.75 0 667.05 2.91 ;
    END
  END wbs_adr_i[12]
  PIN wbs_adr_i[13]
    DIRECTION INPUT ;
    USE SIGNAL ;
    PORT
      LAYER met2 ;
        RECT 670.49 0 670.79 2.91 ;
    END
  END wbs_adr_i[13]
  PIN wbs_stb_i
    DIRECTION INPUT ;
    USE SIGNAL ;
    PORT
      LAYER met2 ;
        RECT 981.59 0 981.89 2.91 ;
    END
  END wbs_stb_i
  PIN wbs_adr_i[14]
    DIRECTION INPUT ;
    USE SIGNAL ;
    PORT
      LAYER met2 ;
        RECT 673.89 0 674.19 2.91 ;
    END
  END wbs_adr_i[14]
  PIN wbs_adr_i[15]
    DIRECTION INPUT ;
    USE SIGNAL ;
    PORT
      LAYER met2 ;
        RECT 677.63 0 677.93 2.91 ;
    END
  END wbs_adr_i[15]
  PIN wbs_adr_i[16]
    DIRECTION INPUT ;
    USE SIGNAL ;
    PORT
      LAYER met2 ;
        RECT 681.03 0 681.33 2.91 ;
    END
  END wbs_adr_i[16]
  PIN wbs_adr_i[17]
    DIRECTION INPUT ;
    USE SIGNAL ;
    PORT
      LAYER met2 ;
        RECT 684.77 0 685.07 2.91 ;
    END
  END wbs_adr_i[17]
  PIN wbs_adr_i[18]
    DIRECTION INPUT ;
    USE SIGNAL ;
    PORT
      LAYER met2 ;
        RECT 688.51 0 688.81 2.91 ;
    END
  END wbs_adr_i[18]
  PIN wbs_adr_i[19]
    DIRECTION INPUT ;
    USE SIGNAL ;
    PORT
      LAYER met2 ;
        RECT 691.91 0 692.21 2.91 ;
    END
  END wbs_adr_i[19]
  PIN wbs_adr_i[20]
    DIRECTION INPUT ;
    USE SIGNAL ;
    PORT
      LAYER met2 ;
        RECT 695.65 0 695.95 2.91 ;
    END
  END wbs_adr_i[20]
  PIN wbs_adr_i[21]
    DIRECTION INPUT ;
    USE SIGNAL ;
    PORT
      LAYER met2 ;
        RECT 699.05 0 699.35 2.91 ;
    END
  END wbs_adr_i[21]
  PIN wbs_adr_i[22]
    DIRECTION INPUT ;
    USE SIGNAL ;
    PORT
      LAYER met2 ;
        RECT 702.79 0 703.09 2.91 ;
    END
  END wbs_adr_i[22]
  PIN wbs_adr_i[23]
    DIRECTION INPUT ;
    USE SIGNAL ;
    PORT
      LAYER met2 ;
        RECT 706.53 0 706.83 2.91 ;
    END
  END wbs_adr_i[23]
  PIN wbs_adr_i[24]
    DIRECTION INPUT ;
    USE SIGNAL ;
    PORT
      LAYER met2 ;
        RECT 709.93 0 710.23 2.91 ;
    END
  END wbs_adr_i[24]
  PIN wbs_adr_i[25]
    DIRECTION INPUT ;
    USE SIGNAL ;
    PORT
      LAYER met2 ;
        RECT 713.67 0 713.97 2.91 ;
    END
  END wbs_adr_i[25]
  PIN wbs_adr_i[26]
    DIRECTION INPUT ;
    USE SIGNAL ;
    PORT
      LAYER met2 ;
        RECT 717.07 0 717.37 2.91 ;
    END
  END wbs_adr_i[26]
  PIN wbs_adr_i[27]
    DIRECTION INPUT ;
    USE SIGNAL ;
    PORT
      LAYER met2 ;
        RECT 720.81 0 721.11 2.91 ;
    END
  END wbs_adr_i[27]
  PIN wbs_adr_i[28]
    DIRECTION INPUT ;
    USE SIGNAL ;
    PORT
      LAYER met2 ;
        RECT 724.55 0 724.85 2.91 ;
    END
  END wbs_adr_i[28]
  PIN wbs_adr_i[29]
    DIRECTION INPUT ;
    USE SIGNAL ;
    PORT
      LAYER met2 ;
        RECT 727.95 0 728.25 2.91 ;
    END
  END wbs_adr_i[29]
  PIN wbs_adr_i[30]
    DIRECTION INPUT ;
    USE SIGNAL ;
    PORT
      LAYER met2 ;
        RECT 731.69 0 731.99 2.91 ;
    END
  END wbs_adr_i[30]
  PIN wbs_adr_i[31]
    DIRECTION INPUT ;
    USE SIGNAL ;
    PORT
      LAYER met2 ;
        RECT 735.09 0 735.39 2.91 ;
    END
  END wbs_adr_i[31]
  PIN wbs_adr_i[0]
    DIRECTION INPUT ;
    USE SIGNAL ;
    PORT
      LAYER met2 ;
        RECT 623.57 0 623.87 2.91 ;
    END
  END wbs_adr_i[0]
  PIN wbs_dat_i[1]
    DIRECTION INPUT ;
    USE SIGNAL ;
    PORT
      LAYER met2 ;
        RECT 1234.55 0 1234.85 2.91 ;
    END
  END wbs_dat_i[1]
  PIN wbs_dat_i[2]
    DIRECTION INPUT ;
    USE SIGNAL ;
    PORT
      LAYER met2 ;
        RECT 1241.69 0 1241.99 2.91 ;
    END
  END wbs_dat_i[2]
  PIN wbs_dat_i[3]
    DIRECTION INPUT ;
    USE SIGNAL ;
    PORT
      LAYER met2 ;
        RECT 1248.83 0 1249.13 2.91 ;
    END
  END wbs_dat_i[3]
  PIN wbs_dat_i[4]
    DIRECTION INPUT ;
    USE SIGNAL ;
    PORT
      LAYER met2 ;
        RECT 1256.31 0 1256.61 2.91 ;
    END
  END wbs_dat_i[4]
  PIN wbs_dat_i[5]
    DIRECTION INPUT ;
    USE SIGNAL ;
    PORT
      LAYER met2 ;
        RECT 1263.45 0 1263.75 2.91 ;
    END
  END wbs_dat_i[5]
  PIN wbs_dat_i[6]
    DIRECTION INPUT ;
    USE SIGNAL ;
    PORT
      LAYER met2 ;
        RECT 1270.59 0 1270.89 2.91 ;
    END
  END wbs_dat_i[6]
  PIN wbs_dat_i[7]
    DIRECTION INPUT ;
    USE SIGNAL ;
    PORT
      LAYER met2 ;
        RECT 1277.73 0 1278.03 2.91 ;
    END
  END wbs_dat_i[7]
  OBS
    LAYER met4 ;
      RECT 1378.56 1312.925 2213.79 1405.225 ;
    LAYER met2 ;
      RECT 0 2 3874 3805 ;
    LAYER li1 ;
      RECT 0 0 3874 3805 ;
    LAYER met1 ;
      RECT 0 0 3874 3805 ;
    LAYER met3 ;
      RECT 0 0 3874 3805 ;
  END
END Neuromorphic_X2_wb

END LIBRARY
